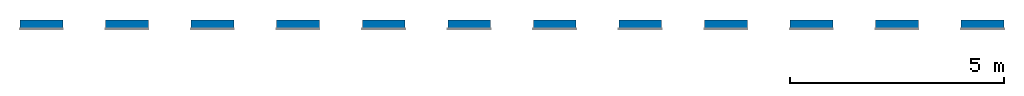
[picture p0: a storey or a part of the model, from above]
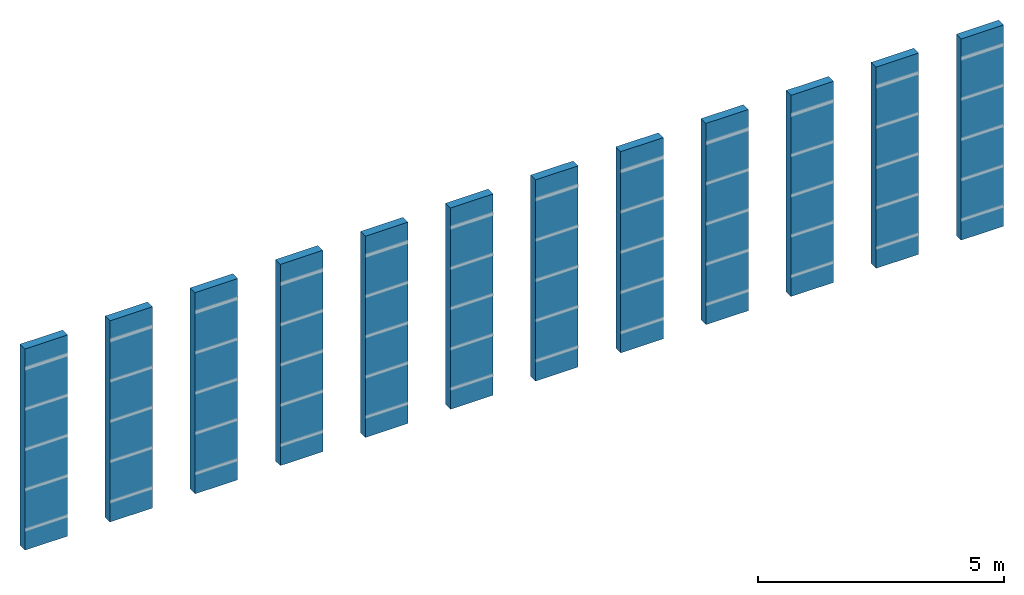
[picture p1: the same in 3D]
Properties of the parts of a building model (IFC2X3), part 1 of 4

# File
Description: ViewDefinition [CoordinationView_V2.0]
Time: 2025-06-20T14:48:50
Written by: The EXPRESS Data Manager Version 5.02.0100.07 : 28 Aug 2013
Made in: 21.1.90.15 - Exporter 21.1.90.15 - Alternate UI 21.1.90.15
Comment: STEP Physical File produced by: The EXPRESS Data Manager Version 5.02.0100.07 : 28 Aug 2013 * Module: EDMstepFileFactory/EDMstandAlone * Creation date: Fri Jun 20 14:48:50 2025 * Host: STB002 * Database: C:\Users\LARISS~1\AppData\Local\Temp\234e31d9-e186-458c-9206-d387dea7a233\7819710d-270b-444c-ba7b-598bd2ec56cc\ifc * Database version: 5507 * Database creation date: Fri Jun 20 14:48:48 2025 * Schema: IFC2X3 * Model: DataRepository.ifc * Model creation date: Fri Jun 20 14:48:49 2025 * Header model: DataRepository.ifc_HeaderModel * Header model creation date: Fri Jun 20 14:48:49 2025 * EDMuser: sdai-user * EDMgroup: sdai-group * License ID and type: 5605 : Permanent license. Expiry date: * EDMstepFileFactory options: 020000

# IfcSite, Default
RefLatitude: 42, 24, 53, 508911; RefLongitude: -71, -15, -29, -58837; RefElevation: 0 mm
Pset_ProductRequirements - Category: Project Information

# IfcBuilding
Pset_BuildingCommon - NumberOfStoreys: 1
Pset_ProductRequirements - Category: Project Information

# IfcBuildingStorey: Level:Level 1, Level 1
LongName: Level 1; Elevation: 0 mm
Pset_AirSideSystemInformation - Name: Level 1
Pset_ProductRequirements - Name: Level 1; Category: Levels

# IfcBuildingElementProxy: Wall Sweep:REVIGRÉS-OMNISTONE-RB-8X120-MATTRECT-BONE, Wall Sweep:REVIGRÉS-OMNISTONE-RB-8X120-MATTRECT-BONE:181677
In: Level 1
Type - Pset_ManufacturerTypeInformation - Manufacturer: REVIGRÉS
Type - Pset_ProductRequirements - Category: Wall Sweeps
Type - IFC.REVIGRÉS-Dados gerais-Wall Sweeps - Nome: REVIGRÉS-OMNISTONE-RB-8X120-MATT RECT-BONE; TipoProduto: Prensado a seco: grupo BIa UGL | Grés porcelânico técnico; NumeroDeRegistoDAP: EPD-REV-20240006-CCC1-EN; ReferenciaDAP: -; UrlDOP: -
Type - IFC.REVIGRÉS-Dados do fabricante-Wall Sweeps - FabricanteURL: https://www.revigres.pt/; ReferenciaModelo: Omnistone; Acabamento: MATT RECT; IdentificadorDoOperadorEconomico: 501840856; UrlFabricanteArtigo: https://www.revigres.pt/colecoes/omnistone; PaisOrigem: Portugal
Type - IFC.REVIGRÉS-Dados de desempenho-Wall Sweeps - Rectilinearidade: ± 0.2% máx.± 0.8 mm; Ortogonalidade: ± 0.2% máx.± 1.5 mm; PlanaridadeDaSuperficie: ± 0.3% máx. ± 1.8 mm; AbsorcaoDeAgua: < 0.05%; ModuloDeRuptura: > 45 N/mm130; ResistenciaAFlexao: ≥ 3500 N; ResistenciaAAbrasaoProfunda: < 120 mm131; DilatacaoTermicaLinear: ≤ 8,0x10-6 °C-1; ResistenciaAoChoqueTermico: Resiste; DurabilidadeResistenciaAoGeloDegelo: Resiste; ResistenciaAoEscorregamentoDIN51130: R10; ResistenciaAoEscorregamentoDIN51097: B; ResistenciaAoEscorregamentoENV51097: B; ResistenciaAoDeslizamentoENV12633: Class 2; ResistenciaAoEscorregamentoBS7976: >36; ResistenciaAoEscorregamentoANSIA1371: ≥0,42; ResistenciaAoEscorregamentoENV12633: Class 2; ResistenciaAoDeslizamentoBS7976: >36; ResistenciaAsManchas: Class 5; ResistenciaABaixasConcentracoesDeAcidosEAlcalis: Classe LA; ResistenciaAAltasConcentracoesDeAcidosEAlcalis: Classe HA; LibertacaoDeCadmio: 0; LibertacaoDeChumbo: 0
Type - IFC.REVIGRÉS-Dados de especificação-Wall Sweeps - VariacaoTonalidade: 3; NivelDeTrafego: 5; EPavimento: Não; ERevestimento: Sim; EExterno: Sim
Type - IFC.REVIGRÉS-Dados geométricos-Wall Sweeps - AlturaNominal: 9.8 mm; ComprimentoNominal: 8 mm; LarguraNominal: 118.6 mm
Type - IFC.REVIGRÉS-Dados de sustentabilidade-Wall Sweeps - ItemEParcialmenteReciclado: 0; PotencialPrivacaoDeAguaConsumoDeAguaPonderado: 4.5; EnergiaTermicaExportada: 0; ItemENovo: Sim; ItemEReciclado: Não; VidaÚtilEsperada: 50; SubstanciasPerigosas: Não; PotencialDeEsgotamentoAbioticoDosRecursosFosseis: 203; PotencialDeEsgotamentoAbioticoDosRecursosNaoFosseisMineraisEMetais: 0.000701; PotencialDeAquecimentoGlobalBiogenico: -0.48; CombustiveisFosseisComPotencialDeAquecimentoGlobal: 13.9; PotencialDeAquecimentoGlobalUsoDoSoloEMudancaDeUsoDoSolo: 0.0246; PotencialDeEutrofizacaoFraccaoDeNutrientesQueAtingemOCompartimentoFinalDeAguaDoce: 0.000189; PotencialDeEutrofizacaoFraccaoDeNutrientesQueAtingemOCompartimentoFinalMarinho: 0.0122; EnergiaRecuperada: 0.00739; ConsumoDeAguaDoce: 0.113; UtilizacaoLiquidaDeAguaDoce: 0.113; ResiduosPerigososEliminados: 0.00221; ResiduosNaoPerigososEliminados: 1.83; MassaTotalDeResiduosRadioactivosEliminados: 0.000394; EnergiaElectricaExportada: 1.55; MateriaisParaRecuperacaoDeEnergia: 0.00739; MateriaisParaReciclagem: 0.0253; UnidadeEPD: 1 m²
Pset_ProvisionForVoid - Shape: Undefined; Width: 1000 mm; Depth: 1000 mm
IFC.REVIGRÉS-Dados do fabricante-Wall Sweeps - Type: Wall Sweep: REVIGRÉS-OMNISTONE-RB-8X120-MATTRECT-BONE
IFC.REVIGRÉS-Dados de desempenho-Wall Sweeps - Type: Wall Sweep: REVIGRÉS-OMNISTONE-RB-8X120-MATTRECT-BONE
IFC.REVIGRÉS-Dados de especificação-Wall Sweeps - Type: Wall Sweep: REVIGRÉS-OMNISTONE-RB-8X120-MATTRECT-BONE
IFC.REVIGRÉS-Dados geométricos-Wall Sweeps - Type: Wall Sweep: REVIGRÉS-OMNISTONE-RB-8X120-MATTRECT-BONE
IFC.REVIGRÉS-Dados de sustentabilidade-Wall Sweeps - Type: Wall Sweep: REVIGRÉS-OMNISTONE-RB-8X120-MATTRECT-BONE

# IfcBuildingElementProxy: Wall Sweep:REVIGRÉS-OMNISTONE-RB-8X120-MATTRECT-ICE, Wall Sweep:REVIGRÉS-OMNISTONE-RB-8X120-MATTRECT-ICE:181689
In: Level 1
Type - Pset_ManufacturerTypeInformation - Manufacturer: REVIGRÉS
Type - Pset_ProductRequirements - Category: Wall Sweeps
Type - IFC.REVIGRÉS-Dados gerais-Wall Sweeps - Nome: REVIGRÉS-OMNISTONE-RB-8X120-MATT RECT-ICE; TipoProduto: Prensado a seco: grupo BIa UGL | Grés porcelânico técnico; NumeroDeRegistoDAP: EPD-REV-20240006-CCC1-EN; ReferenciaDAP: -; UrlDOP: -
Type - IFC.REVIGRÉS-Dados do fabricante-Wall Sweeps - FabricanteURL: https://www.revigres.pt/; ReferenciaModelo: Omnistone; Acabamento: MATT RECT; IdentificadorDoOperadorEconomico: 501840856; UrlFabricanteArtigo: https://www.revigres.pt/colecoes/omnistone; PaisOrigem: Portugal
Type - IFC.REVIGRÉS-Dados de desempenho-Wall Sweeps - Rectilinearidade: ± 0.2% máx.± 0.8 mm; Ortogonalidade: ± 0.2% máx.± 1.5 mm; PlanaridadeDaSuperficie: ± 0.3% máx. ± 1.8 mm; AbsorcaoDeAgua: < 0.05%; ModuloDeRuptura: > 45 N/mm130; ResistenciaAFlexao: ≥ 3500 N; ResistenciaAAbrasaoProfunda: < 120 mm131; DilatacaoTermicaLinear: ≤ 8,0x10-6 °C-1; ResistenciaAoChoqueTermico: Resiste; DurabilidadeResistenciaAoGeloDegelo: Resiste; ResistenciaAoEscorregamentoDIN51130: R10; ResistenciaAoEscorregamentoDIN51097: B; ResistenciaAoEscorregamentoENV51097: B; ResistenciaAoDeslizamentoENV12633: Class 2; ResistenciaAoEscorregamentoBS7976: >36; ResistenciaAoEscorregamentoANSIA1371: ≥0,42; ResistenciaAoEscorregamentoENV12633: Class 2; ResistenciaAoDeslizamentoBS7976: >36; ResistenciaAsManchas: Class 5; ResistenciaABaixasConcentracoesDeAcidosEAlcalis: Classe LA; ResistenciaAAltasConcentracoesDeAcidosEAlcalis: Classe HA; LibertacaoDeCadmio: 0; LibertacaoDeChumbo: 0
Type - IFC.REVIGRÉS-Dados de especificação-Wall Sweeps - VariacaoTonalidade: 3; NivelDeTrafego: 5; EPavimento: Não; ERevestimento: Sim; EExterno: Sim
Type - IFC.REVIGRÉS-Dados geométricos-Wall Sweeps - AlturaNominal: 9.8 mm; ComprimentoNominal: 8 mm; LarguraNominal: 118.6 mm
Type - IFC.REVIGRÉS-Dados de sustentabilidade-Wall Sweeps - ItemEParcialmenteReciclado: 0; PotencialPrivacaoDeAguaConsumoDeAguaPonderado: 4.5; EnergiaTermicaExportada: 0; ItemENovo: Sim; ItemEReciclado: Não; VidaÚtilEsperada: 50; SubstanciasPerigosas: Não; PotencialDeEsgotamentoAbioticoDosRecursosFosseis: 203; PotencialDeEsgotamentoAbioticoDosRecursosNaoFosseisMineraisEMetais: 0.000701; PotencialDeAquecimentoGlobalBiogenico: -0.48; CombustiveisFosseisComPotencialDeAquecimentoGlobal: 13.9; PotencialDeAquecimentoGlobalUsoDoSoloEMudancaDeUsoDoSolo: 0.0246; PotencialDeEutrofizacaoFraccaoDeNutrientesQueAtingemOCompartimentoFinalDeAguaDoce: 0.000189; PotencialDeEutrofizacaoFraccaoDeNutrientesQueAtingemOCompartimentoFinalMarinho: 0.0122; EnergiaRecuperada: 0.00739; ConsumoDeAguaDoce: 0.113; UtilizacaoLiquidaDeAguaDoce: 0.113; ResiduosPerigososEliminados: 0.00221; ResiduosNaoPerigososEliminados: 1.83; MassaTotalDeResiduosRadioactivosEliminados: 0.000394; EnergiaElectricaExportada: 1.55; MateriaisParaRecuperacaoDeEnergia: 0.00739; MateriaisParaReciclagem: 0.0253; UnidadeEPD: 1 m²
Pset_ProvisionForVoid - Shape: Undefined; Width: 1000 mm; Depth: 1000 mm
IFC.REVIGRÉS-Dados do fabricante-Wall Sweeps - Type: Wall Sweep: REVIGRÉS-OMNISTONE-RB-8X120-MATTRECT-ICE
IFC.REVIGRÉS-Dados de desempenho-Wall Sweeps - Type: Wall Sweep: REVIGRÉS-OMNISTONE-RB-8X120-MATTRECT-ICE
IFC.REVIGRÉS-Dados de especificação-Wall Sweeps - Type: Wall Sweep: REVIGRÉS-OMNISTONE-RB-8X120-MATTRECT-ICE
IFC.REVIGRÉS-Dados geométricos-Wall Sweeps - Type: Wall Sweep: REVIGRÉS-OMNISTONE-RB-8X120-MATTRECT-ICE
IFC.REVIGRÉS-Dados de sustentabilidade-Wall Sweeps - Type: Wall Sweep: REVIGRÉS-OMNISTONE-RB-8X120-MATTRECT-ICE

# IfcBuildingElementProxy: Wall Sweep:REVIGRÉS-OMNISTONE-RB-8X120-MATTRECT-IRON, Wall Sweep:REVIGRÉS-OMNISTONE-RB-8X120-MATTRECT-IRON:181701
In: Level 1
Type - Pset_ManufacturerTypeInformation - Manufacturer: REVIGRÉS
Type - Pset_ProductRequirements - Category: Wall Sweeps
Type - IFC.REVIGRÉS-Dados gerais-Wall Sweeps - Nome: REVIGRÉS-OMNISTONE-RB-8X120-MATT RECT-IRON; TipoProduto: Prensado a seco: grupo BIa UGL | Grés porcelânico técnico; NumeroDeRegistoDAP: EPD-REV-20240006-CCC1-EN; ReferenciaDAP: -; UrlDOP: -
Type - IFC.REVIGRÉS-Dados do fabricante-Wall Sweeps - FabricanteURL: https://www.revigres.pt/; ReferenciaModelo: Omnistone; Acabamento: MATT RECT; IdentificadorDoOperadorEconomico: 501840856; UrlFabricanteArtigo: https://www.revigres.pt/colecoes/omnistone; PaisOrigem: Portugal
Type - IFC.REVIGRÉS-Dados de desempenho-Wall Sweeps - Rectilinearidade: ± 0.2% máx.± 0.8 mm; Ortogonalidade: ± 0.2% máx.± 1.5 mm; PlanaridadeDaSuperficie: ± 0.3% máx. ± 1.8 mm; AbsorcaoDeAgua: < 0.05%; ModuloDeRuptura: > 45 N/mm130; ResistenciaAFlexao: ≥ 3500 N; ResistenciaAAbrasaoProfunda: < 120 mm131; DilatacaoTermicaLinear: ≤ 8,0x10-6 °C-1; ResistenciaAoChoqueTermico: Resiste; DurabilidadeResistenciaAoGeloDegelo: Resiste; ResistenciaAoEscorregamentoDIN51130: R10; ResistenciaAoEscorregamentoDIN51097: B; ResistenciaAoEscorregamentoENV51097: B; ResistenciaAoDeslizamentoENV12633: Class 2; ResistenciaAoEscorregamentoBS7976: >36; ResistenciaAoEscorregamentoANSIA1371: ≥0,42; ResistenciaAoEscorregamentoENV12633: Class 2; ResistenciaAoDeslizamentoBS7976: >36; ResistenciaAsManchas: Class 5; ResistenciaABaixasConcentracoesDeAcidosEAlcalis: Classe LA; ResistenciaAAltasConcentracoesDeAcidosEAlcalis: Classe HA; LibertacaoDeCadmio: 0; LibertacaoDeChumbo: 0
Type - IFC.REVIGRÉS-Dados de especificação-Wall Sweeps - VariacaoTonalidade: 3; NivelDeTrafego: 5; EPavimento: Não; ERevestimento: Sim; EExterno: Sim
Type - IFC.REVIGRÉS-Dados geométricos-Wall Sweeps - AlturaNominal: 9.8 mm; ComprimentoNominal: 8 mm; LarguraNominal: 118.6 mm
Type - IFC.REVIGRÉS-Dados de sustentabilidade-Wall Sweeps - PotencialPrivacaoDeAguaConsumoDeAguaPonderado: 4.5; EnergiaTermicaExportada: 0; ItemENovo: Sim; ItemEParcialmenteReciclado: 0.14; ItemEReciclado: Sim; VidaÚtilEsperada: 50; SubstanciasPerigosas: Não; PotencialDeEsgotamentoAbioticoDosRecursosFosseis: 203; PotencialDeEsgotamentoAbioticoDosRecursosNaoFosseisMineraisEMetais: 0.000701; PotencialDeAquecimentoGlobalBiogenico: -0.48; CombustiveisFosseisComPotencialDeAquecimentoGlobal: 13.9; PotencialDeAquecimentoGlobalUsoDoSoloEMudancaDeUsoDoSolo: 0.0246; PotencialDeEutrofizacaoFraccaoDeNutrientesQueAtingemOCompartimentoFinalDeAguaDoce: 0.000189; PotencialDeEutrofizacaoFraccaoDeNutrientesQueAtingemOCompartimentoFinalMarinho: 0.0122; EnergiaRecuperada: 0.00739; ConsumoDeAguaDoce: 0.113; UtilizacaoLiquidaDeAguaDoce: 0.113; ResiduosPerigososEliminados: 0.00221; ResiduosNaoPerigososEliminados: 1.83; MassaTotalDeResiduosRadioactivosEliminados: 0.000394; EnergiaElectricaExportada: 1.55; MateriaisParaRecuperacaoDeEnergia: 0.00739; MateriaisParaReciclagem: 0.0253; UnidadeEPD: 1 m²
Pset_ProvisionForVoid - Shape: Undefined; Width: 1000 mm; Depth: 1000 mm
IFC.REVIGRÉS-Dados do fabricante-Wall Sweeps - Type: Wall Sweep: REVIGRÉS-OMNISTONE-RB-8X120-MATTRECT-IRON
IFC.REVIGRÉS-Dados de desempenho-Wall Sweeps - Type: Wall Sweep: REVIGRÉS-OMNISTONE-RB-8X120-MATTRECT-IRON
IFC.REVIGRÉS-Dados de especificação-Wall Sweeps - Type: Wall Sweep: REVIGRÉS-OMNISTONE-RB-8X120-MATTRECT-IRON
IFC.REVIGRÉS-Dados geométricos-Wall Sweeps - Type: Wall Sweep: REVIGRÉS-OMNISTONE-RB-8X120-MATTRECT-IRON
IFC.REVIGRÉS-Dados de sustentabilidade-Wall Sweeps - Type: Wall Sweep: REVIGRÉS-OMNISTONE-RB-8X120-MATTRECT-IRON

# IfcBuildingElementProxy: Wall Sweep:REVIGRÉS-OMNISTONE-RB-8X120-MATTRECT-JET, Wall Sweep:REVIGRÉS-OMNISTONE-RB-8X120-MATTRECT-JET:181713
In: Level 1
Type - Pset_ManufacturerTypeInformation - Manufacturer: REVIGRÉS
Type - Pset_ProductRequirements - Category: Wall Sweeps
Type - IFC.REVIGRÉS-Dados gerais-Wall Sweeps - Nome: REVIGRÉS-OMNISTONE-RB-8X120-MATT RECT-JET; TipoProduto: Prensado a seco: grupo BIa UGL | Grés porcelânico técnico; NumeroDeRegistoDAP: EPD-REV-20240006-CCC1-EN; ReferenciaDAP: -; UrlDOP: -
Type - IFC.REVIGRÉS-Dados do fabricante-Wall Sweeps - FabricanteURL: https://www.revigres.pt/; ReferenciaModelo: Omnistone; Acabamento: MATT RECT; IdentificadorDoOperadorEconomico: 501840856; UrlFabricanteArtigo: https://www.revigres.pt/colecoes/omnistone; PaisOrigem: Portugal
Type - IFC.REVIGRÉS-Dados de desempenho-Wall Sweeps - Rectilinearidade: ± 0.2% máx.± 0.8 mm; Ortogonalidade: ± 0.2% máx.± 1.5 mm; PlanaridadeDaSuperficie: ± 0.3% máx. ± 1.8 mm; AbsorcaoDeAgua: < 0.05%; ModuloDeRuptura: > 45 N/mm130; ResistenciaAFlexao: ≥ 3500 N; ResistenciaAAbrasaoProfunda: < 120 mm131; DilatacaoTermicaLinear: ≤ 8,0x10-6 °C-1; ResistenciaAoChoqueTermico: Resiste; DurabilidadeResistenciaAoGeloDegelo: Resiste; ResistenciaAoEscorregamentoDIN51130: R10; ResistenciaAoEscorregamentoDIN51097: B; ResistenciaAoEscorregamentoENV51097: B; ResistenciaAoDeslizamentoENV12633: Class 2; ResistenciaAoEscorregamentoBS7976: >36; ResistenciaAoEscorregamentoANSIA1371: ≥0,42; ResistenciaAoEscorregamentoENV12633: Class 2; ResistenciaAoDeslizamentoBS7976: >36; ResistenciaAsManchas: Class 5; ResistenciaABaixasConcentracoesDeAcidosEAlcalis: Classe LA; ResistenciaAAltasConcentracoesDeAcidosEAlcalis: Classe HA; LibertacaoDeCadmio: 0; LibertacaoDeChumbo: 0
Type - IFC.REVIGRÉS-Dados de especificação-Wall Sweeps - VariacaoTonalidade: 3; NivelDeTrafego: 5; EPavimento: Não; ERevestimento: Sim; EExterno: Sim
Type - IFC.REVIGRÉS-Dados geométricos-Wall Sweeps - AlturaNominal: 9.8 mm; ComprimentoNominal: 8 mm; LarguraNominal: 118.6 mm
Type - IFC.REVIGRÉS-Dados de sustentabilidade-Wall Sweeps - ItemEParcialmenteReciclado: 0; PotencialPrivacaoDeAguaConsumoDeAguaPonderado: 4.5; EnergiaTermicaExportada: 0; ItemENovo: Sim; ItemEReciclado: Não; VidaÚtilEsperada: 50; SubstanciasPerigosas: Não; PotencialDeEsgotamentoAbioticoDosRecursosFosseis: 203; PotencialDeEsgotamentoAbioticoDosRecursosNaoFosseisMineraisEMetais: 0.000701; PotencialDeAquecimentoGlobalBiogenico: -0.48; CombustiveisFosseisComPotencialDeAquecimentoGlobal: 13.9; PotencialDeAquecimentoGlobalUsoDoSoloEMudancaDeUsoDoSolo: 0.0246; PotencialDeEutrofizacaoFraccaoDeNutrientesQueAtingemOCompartimentoFinalDeAguaDoce: 0.000189; PotencialDeEutrofizacaoFraccaoDeNutrientesQueAtingemOCompartimentoFinalMarinho: 0.0122; EnergiaRecuperada: 0.00739; ConsumoDeAguaDoce: 0.113; UtilizacaoLiquidaDeAguaDoce: 0.113; ResiduosPerigososEliminados: 0.00221; ResiduosNaoPerigososEliminados: 1.83; MassaTotalDeResiduosRadioactivosEliminados: 0.000394; EnergiaElectricaExportada: 1.55; MateriaisParaRecuperacaoDeEnergia: 0.00739; MateriaisParaReciclagem: 0.0253; UnidadeEPD: 1 m²
Pset_ProvisionForVoid - Shape: Undefined; Width: 1000 mm; Depth: 1000 mm
IFC.REVIGRÉS-Dados do fabricante-Wall Sweeps - Type: Wall Sweep: REVIGRÉS-OMNISTONE-RB-8X120-MATTRECT-JET
IFC.REVIGRÉS-Dados de desempenho-Wall Sweeps - Type: Wall Sweep: REVIGRÉS-OMNISTONE-RB-8X120-MATTRECT-JET
IFC.REVIGRÉS-Dados de especificação-Wall Sweeps - Type: Wall Sweep: REVIGRÉS-OMNISTONE-RB-8X120-MATTRECT-JET
IFC.REVIGRÉS-Dados geométricos-Wall Sweeps - Type: Wall Sweep: REVIGRÉS-OMNISTONE-RB-8X120-MATTRECT-JET
IFC.REVIGRÉS-Dados de sustentabilidade-Wall Sweeps - Type: Wall Sweep: REVIGRÉS-OMNISTONE-RB-8X120-MATTRECT-JET

# IfcBuildingElementProxy: Wall Sweep:REVIGRÉS-OMNISTONE-RB-8X120-MATTRECT-PLATINA, Wall Sweep:REVIGRÉS-OMNISTONE-RB-8X120-MATTRECT-PLATINA:181725
In: Level 1
Type - Pset_ManufacturerTypeInformation - Manufacturer: REVIGRÉS
Type - Pset_ProductRequirements - Category: Wall Sweeps
Type - IFC.REVIGRÉS-Dados gerais-Wall Sweeps - Nome: REVIGRÉS-OMNISTONE-RB-8X120-MATT RECT-PLATINA; TipoProduto: Prensado a seco: grupo BIa UGL | Grés porcelânico técnico; NumeroDeRegistoDAP: EPD-REV-20240006-CCC1-EN; ReferenciaDAP: -; UrlDOP: -
Type - IFC.REVIGRÉS-Dados do fabricante-Wall Sweeps - FabricanteURL: https://www.revigres.pt/; ReferenciaModelo: Omnistone; Acabamento: MATT RECT; IdentificadorDoOperadorEconomico: 501840856; UrlFabricanteArtigo: https://www.revigres.pt/colecoes/omnistone; PaisOrigem: Portugal
Type - IFC.REVIGRÉS-Dados de desempenho-Wall Sweeps - Rectilinearidade: ± 0.2% máx.± 0.8 mm; Ortogonalidade: ± 0.2% máx.± 1.5 mm; PlanaridadeDaSuperficie: ± 0.3% máx. ± 1.8 mm; AbsorcaoDeAgua: < 0.05%; ModuloDeRuptura: > 45 N/mm130; ResistenciaAFlexao: ≥ 3500 N; ResistenciaAAbrasaoProfunda: < 120 mm131; DilatacaoTermicaLinear: ≤ 8,0x10-6 °C-1; ResistenciaAoChoqueTermico: Resiste; DurabilidadeResistenciaAoGeloDegelo: Resiste; ResistenciaAoEscorregamentoDIN51130: R10; ResistenciaAoEscorregamentoDIN51097: B; ResistenciaAoEscorregamentoENV51097: B; ResistenciaAoDeslizamentoENV12633: Class 2; ResistenciaAoEscorregamentoBS7976: >36; ResistenciaAoEscorregamentoANSIA1371: ≥0,42; ResistenciaAoEscorregamentoENV12633: Class 2; ResistenciaAoDeslizamentoBS7976: >36; ResistenciaAsManchas: Class 5; ResistenciaABaixasConcentracoesDeAcidosEAlcalis: Classe LA; ResistenciaAAltasConcentracoesDeAcidosEAlcalis: Classe HA; LibertacaoDeCadmio: 0; LibertacaoDeChumbo: 0
Type - IFC.REVIGRÉS-Dados de especificação-Wall Sweeps - VariacaoTonalidade: 3; NivelDeTrafego: 5; EPavimento: Não; ERevestimento: Sim; EExterno: Sim
Type - IFC.REVIGRÉS-Dados geométricos-Wall Sweeps - AlturaNominal: 9.8 mm; ComprimentoNominal: 8 mm; LarguraNominal: 118.6 mm
Type - IFC.REVIGRÉS-Dados de sustentabilidade-Wall Sweeps - ItemEParcialmenteReciclado: 0; PotencialPrivacaoDeAguaConsumoDeAguaPonderado: 4.5; EnergiaTermicaExportada: 0; ItemENovo: Sim; ItemEReciclado: Não; VidaÚtilEsperada: 50; SubstanciasPerigosas: Não; PotencialDeEsgotamentoAbioticoDosRecursosFosseis: 203; PotencialDeEsgotamentoAbioticoDosRecursosNaoFosseisMineraisEMetais: 0.000701; PotencialDeAquecimentoGlobalBiogenico: -0.48; CombustiveisFosseisComPotencialDeAquecimentoGlobal: 13.9; PotencialDeAquecimentoGlobalUsoDoSoloEMudancaDeUsoDoSolo: 0.0246; PotencialDeEutrofizacaoFraccaoDeNutrientesQueAtingemOCompartimentoFinalDeAguaDoce: 0.000189; PotencialDeEutrofizacaoFraccaoDeNutrientesQueAtingemOCompartimentoFinalMarinho: 0.0122; EnergiaRecuperada: 0.00739; ConsumoDeAguaDoce: 0.113; UtilizacaoLiquidaDeAguaDoce: 0.113; ResiduosPerigososEliminados: 0.00221; ResiduosNaoPerigososEliminados: 1.83; MassaTotalDeResiduosRadioactivosEliminados: 0.000394; EnergiaElectricaExportada: 1.55; MateriaisParaRecuperacaoDeEnergia: 0.00739; MateriaisParaReciclagem: 0.0253; UnidadeEPD: 1 m²
Pset_ProvisionForVoid - Shape: Undefined; Width: 1000 mm; Depth: 1000 mm
IFC.REVIGRÉS-Dados do fabricante-Wall Sweeps - Type: Wall Sweep: REVIGRÉS-OMNISTONE-RB-8X120-MATTRECT-PLATINA
IFC.REVIGRÉS-Dados de desempenho-Wall Sweeps - Type: Wall Sweep: REVIGRÉS-OMNISTONE-RB-8X120-MATTRECT-PLATINA
IFC.REVIGRÉS-Dados de especificação-Wall Sweeps - Type: Wall Sweep: REVIGRÉS-OMNISTONE-RB-8X120-MATTRECT-PLATINA
IFC.REVIGRÉS-Dados geométricos-Wall Sweeps - Type: Wall Sweep: REVIGRÉS-OMNISTONE-RB-8X120-MATTRECT-PLATINA
IFC.REVIGRÉS-Dados de sustentabilidade-Wall Sweeps - Type: Wall Sweep: REVIGRÉS-OMNISTONE-RB-8X120-MATTRECT-PLATINA

# IfcBuildingElementProxy: Wall Sweep:REVIGRÉS-OMNISTONE-RB-8X120-MATTRECT-ROPE, Wall Sweep:REVIGRÉS-OMNISTONE-RB-8X120-MATTRECT-ROPE:181737
In: Level 1
Type - Pset_ManufacturerTypeInformation - Manufacturer: REVIGRÉS
Type - Pset_ProductRequirements - Category: Wall Sweeps
Type - IFC.REVIGRÉS-Dados gerais-Wall Sweeps - Nome: REVIGRÉS-OMNISTONE-RB-8X120-MATT RECT-ROPE; TipoProduto: Prensado a seco: grupo BIa UGL | Grés porcelânico técnico; NumeroDeRegistoDAP: EPD-REV-20240006-CCC1-EN; ReferenciaDAP: -; UrlDOP: -
Type - IFC.REVIGRÉS-Dados do fabricante-Wall Sweeps - FabricanteURL: https://www.revigres.pt/; ReferenciaModelo: Omnistone; Acabamento: MATT RECT; IdentificadorDoOperadorEconomico: 501840856; UrlFabricanteArtigo: https://www.revigres.pt/colecoes/omnistone; PaisOrigem: Portugal
Type - IFC.REVIGRÉS-Dados de desempenho-Wall Sweeps - Rectilinearidade: ± 0.2% máx.± 0.8 mm; Ortogonalidade: ± 0.2% máx.± 1.5 mm; PlanaridadeDaSuperficie: ± 0.3% máx. ± 1.8 mm; AbsorcaoDeAgua: < 0.05%; ModuloDeRuptura: > 45 N/mm130; ResistenciaAFlexao: ≥ 3500 N; ResistenciaAAbrasaoProfunda: < 120 mm131; DilatacaoTermicaLinear: ≤ 8,0x10-6 °C-1; ResistenciaAoChoqueTermico: Resiste; DurabilidadeResistenciaAoGeloDegelo: Resiste; ResistenciaAoEscorregamentoDIN51130: R10; ResistenciaAoEscorregamentoDIN51097: B; ResistenciaAoEscorregamentoENV51097: B; ResistenciaAoDeslizamentoENV12633: Class 2; ResistenciaAoEscorregamentoBS7976: >36; ResistenciaAoEscorregamentoANSIA1371: ≥0,42; ResistenciaAoEscorregamentoENV12633: Class 2; ResistenciaAoDeslizamentoBS7976: >36; ResistenciaAsManchas: Class 5; ResistenciaABaixasConcentracoesDeAcidosEAlcalis: Classe LA; ResistenciaAAltasConcentracoesDeAcidosEAlcalis: Classe HA; LibertacaoDeCadmio: 0; LibertacaoDeChumbo: 0
Type - IFC.REVIGRÉS-Dados de especificação-Wall Sweeps - VariacaoTonalidade: 3; NivelDeTrafego: 5; EPavimento: Não; ERevestimento: Sim; EExterno: Sim
Type - IFC.REVIGRÉS-Dados geométricos-Wall Sweeps - AlturaNominal: 9.8 mm; ComprimentoNominal: 8 mm; LarguraNominal: 118.6 mm
Type - IFC.REVIGRÉS-Dados de sustentabilidade-Wall Sweeps - ItemEParcialmenteReciclado: 0; PotencialPrivacaoDeAguaConsumoDeAguaPonderado: 4.5; EnergiaTermicaExportada: 0; ItemENovo: Sim; ItemEReciclado: Não; VidaÚtilEsperada: 50; SubstanciasPerigosas: Não; PotencialDeEsgotamentoAbioticoDosRecursosFosseis: 203; PotencialDeEsgotamentoAbioticoDosRecursosNaoFosseisMineraisEMetais: 0.000701; PotencialDeAquecimentoGlobalBiogenico: -0.48; CombustiveisFosseisComPotencialDeAquecimentoGlobal: 13.9; PotencialDeAquecimentoGlobalUsoDoSoloEMudancaDeUsoDoSolo: 0.0246; PotencialDeEutrofizacaoFraccaoDeNutrientesQueAtingemOCompartimentoFinalDeAguaDoce: 0.000189; PotencialDeEutrofizacaoFraccaoDeNutrientesQueAtingemOCompartimentoFinalMarinho: 0.0122; EnergiaRecuperada: 0.00739; ConsumoDeAguaDoce: 0.113; UtilizacaoLiquidaDeAguaDoce: 0.113; ResiduosPerigososEliminados: 0.00221; ResiduosNaoPerigososEliminados: 1.83; MassaTotalDeResiduosRadioactivosEliminados: 0.000394; EnergiaElectricaExportada: 1.55; MateriaisParaRecuperacaoDeEnergia: 0.00739; MateriaisParaReciclagem: 0.0253; UnidadeEPD: 1 m²
Pset_ProvisionForVoid - Shape: Undefined; Width: 1000 mm; Depth: 1000 mm
IFC.REVIGRÉS-Dados do fabricante-Wall Sweeps - Type: Wall Sweep: REVIGRÉS-OMNISTONE-RB-8X120-MATTRECT-ROPE
IFC.REVIGRÉS-Dados de desempenho-Wall Sweeps - Type: Wall Sweep: REVIGRÉS-OMNISTONE-RB-8X120-MATTRECT-ROPE
IFC.REVIGRÉS-Dados de especificação-Wall Sweeps - Type: Wall Sweep: REVIGRÉS-OMNISTONE-RB-8X120-MATTRECT-ROPE
IFC.REVIGRÉS-Dados geométricos-Wall Sweeps - Type: Wall Sweep: REVIGRÉS-OMNISTONE-RB-8X120-MATTRECT-ROPE
IFC.REVIGRÉS-Dados de sustentabilidade-Wall Sweeps - Type: Wall Sweep: REVIGRÉS-OMNISTONE-RB-8X120-MATTRECT-ROPE

# IfcBuildingElementProxy: Wall Sweep:REVIGRÉS-OMNISTONE-RB-8X120-SOFT-BONE, Wall Sweep:REVIGRÉS-OMNISTONE-RB-8X120-SOFT-BONE:181683
In: Level 1
Type - Pset_ManufacturerTypeInformation - Manufacturer: REVIGRÉS
Type - Pset_ProductRequirements - Category: Wall Sweeps
Type - IFC.REVIGRÉS-Dados gerais-Wall Sweeps - Nome: REVIGRÉS-OMNISTONE-RB-8X120-SOFT-BONE; TipoProduto: Prensado a seco: grupo BIa UGL | Grés porcelânico técnico; NumeroDeRegistoDAP: EPD-REV-20240006-CCC1-EN; ReferenciaDAP: -; UrlDOP: -
Type - IFC.REVIGRÉS-Dados do fabricante-Wall Sweeps - FabricanteURL: https://www.revigres.pt/; ReferenciaModelo: Omnistone; Acabamento: SOFT; IdentificadorDoOperadorEconomico: 501840856; UrlFabricanteArtigo: https://www.revigres.pt/colecoes/omnistone; PaisOrigem: Portugal
Type - IFC.REVIGRÉS-Dados de desempenho-Wall Sweeps - Rectilinearidade: ± 0.2% máx.± 0.8 mm; Ortogonalidade: ± 0.2% máx.± 1.5 mm; PlanaridadeDaSuperficie: ± 0.3% máx. ± 1.8 mm; AbsorcaoDeAgua: < 0.05%; ModuloDeRuptura: > 45 N/mm130; ResistenciaAFlexao: ≥ 3500 N; ResistenciaAAbrasaoProfunda: < 120 mm131; DilatacaoTermicaLinear: ≤ 8,0x10-6 °C-1; ResistenciaAoChoqueTermico: Resiste; DurabilidadeResistenciaAoGeloDegelo: Resiste; ResistenciaAsManchas: Class 5; ResistenciaABaixasConcentracoesDeAcidosEAlcalis: Classe LA; ResistenciaAAltasConcentracoesDeAcidosEAlcalis: Classe HA; LibertacaoDeCadmio: 0; LibertacaoDeChumbo: 0
Type - IFC.REVIGRÉS-Dados de especificação-Wall Sweeps - VariacaoTonalidade: 3; NivelDeTrafego: 5; EPavimento: Não; ERevestimento: Sim; EExterno: Sim
Type - IFC.REVIGRÉS-Dados geométricos-Wall Sweeps - AlturaNominal: 9.8 mm; ComprimentoNominal: 8 mm; LarguraNominal: 118.6 mm
Type - IFC.REVIGRÉS-Dados de sustentabilidade-Wall Sweeps - ItemEParcialmenteReciclado: 0; PotencialPrivacaoDeAguaConsumoDeAguaPonderado: 4.5; EnergiaTermicaExportada: 0; ItemENovo: Sim; ItemEReciclado: Não; VidaÚtilEsperada: 50; SubstanciasPerigosas: Não; PotencialDeEsgotamentoAbioticoDosRecursosFosseis: 203; PotencialDeEsgotamentoAbioticoDosRecursosNaoFosseisMineraisEMetais: 0.000701; PotencialDeAquecimentoGlobalBiogenico: -0.48; CombustiveisFosseisComPotencialDeAquecimentoGlobal: 13.9; PotencialDeAquecimentoGlobalUsoDoSoloEMudancaDeUsoDoSolo: 0.0246; PotencialDeEutrofizacaoFraccaoDeNutrientesQueAtingemOCompartimentoFinalDeAguaDoce: 0.000189; PotencialDeEutrofizacaoFraccaoDeNutrientesQueAtingemOCompartimentoFinalMarinho: 0.0122; EnergiaRecuperada: 0.00739; ConsumoDeAguaDoce: 0.113; UtilizacaoLiquidaDeAguaDoce: 0.113; ResiduosPerigososEliminados: 0.00221; ResiduosNaoPerigososEliminados: 1.83; MassaTotalDeResiduosRadioactivosEliminados: 0.000394; EnergiaElectricaExportada: 1.55; MateriaisParaRecuperacaoDeEnergia: 0.00739; MateriaisParaReciclagem: 0.0253; UnidadeEPD: 1 m²
Pset_ProvisionForVoid - Shape: Undefined; Width: 1000 mm; Depth: 1000 mm
IFC.REVIGRÉS-Dados do fabricante-Wall Sweeps - Type: Wall Sweep: REVIGRÉS-OMNISTONE-RB-8X120-SOFT-BONE
IFC.REVIGRÉS-Dados de desempenho-Wall Sweeps - Type: Wall Sweep: REVIGRÉS-OMNISTONE-RB-8X120-SOFT-BONE
IFC.REVIGRÉS-Dados de especificação-Wall Sweeps - Type: Wall Sweep: REVIGRÉS-OMNISTONE-RB-8X120-SOFT-BONE
IFC.REVIGRÉS-Dados geométricos-Wall Sweeps - Type: Wall Sweep: REVIGRÉS-OMNISTONE-RB-8X120-SOFT-BONE
IFC.REVIGRÉS-Dados de sustentabilidade-Wall Sweeps - Type: Wall Sweep: REVIGRÉS-OMNISTONE-RB-8X120-SOFT-BONE

# IfcBuildingElementProxy: Wall Sweep:REVIGRÉS-OMNISTONE-RB-8X120-SOFT-ICE, Wall Sweep:REVIGRÉS-OMNISTONE-RB-8X120-SOFT-ICE:181695
In: Level 1
Type - Pset_ManufacturerTypeInformation - Manufacturer: REVIGRÉS
Type - Pset_ProductRequirements - Category: Wall Sweeps
Type - IFC.REVIGRÉS-Dados gerais-Wall Sweeps - Nome: REVIGRÉS-OMNISTONE-RB-8X120-SOFT-ICE; TipoProduto: Prensado a seco: grupo BIa UGL | Grés porcelânico técnico; NumeroDeRegistoDAP: EPD-REV-20240006-CCC1-EN; ReferenciaDAP: -; UrlDOP: -
Type - IFC.REVIGRÉS-Dados do fabricante-Wall Sweeps - FabricanteURL: https://www.revigres.pt/; ReferenciaModelo: Omnistone; Acabamento: SOFT; IdentificadorDoOperadorEconomico: 501840856; UrlFabricanteArtigo: https://www.revigres.pt/colecoes/omnistone; PaisOrigem: Portugal
Type - IFC.REVIGRÉS-Dados de desempenho-Wall Sweeps - Rectilinearidade: ± 0.2% máx.± 0.8 mm; Ortogonalidade: ± 0.2% máx.± 1.5 mm; PlanaridadeDaSuperficie: ± 0.3% máx. ± 1.8 mm; AbsorcaoDeAgua: < 0.05%; ModuloDeRuptura: > 45 N/mm130; ResistenciaAFlexao: ≥ 3500 N; ResistenciaAAbrasaoProfunda: < 120 mm131; DilatacaoTermicaLinear: ≤ 8,0x10-6 °C-1; ResistenciaAoChoqueTermico: Resiste; DurabilidadeResistenciaAoGeloDegelo: Resiste; ResistenciaAsManchas: Class 5; ResistenciaABaixasConcentracoesDeAcidosEAlcalis: Classe LA; ResistenciaAAltasConcentracoesDeAcidosEAlcalis: Classe HA; LibertacaoDeCadmio: 0; LibertacaoDeChumbo: 0
Type - IFC.REVIGRÉS-Dados de especificação-Wall Sweeps - VariacaoTonalidade: 3; NivelDeTrafego: 5; EPavimento: Não; ERevestimento: Sim; EExterno: Sim
Type - IFC.REVIGRÉS-Dados geométricos-Wall Sweeps - AlturaNominal: 9.8 mm; ComprimentoNominal: 8 mm; LarguraNominal: 118.6 mm
Type - IFC.REVIGRÉS-Dados de sustentabilidade-Wall Sweeps - ItemEParcialmenteReciclado: 0; PotencialPrivacaoDeAguaConsumoDeAguaPonderado: 4.5; EnergiaTermicaExportada: 0; ItemENovo: Sim; ItemEReciclado: Não; VidaÚtilEsperada: 50; SubstanciasPerigosas: Não; PotencialDeEsgotamentoAbioticoDosRecursosFosseis: 203; PotencialDeEsgotamentoAbioticoDosRecursosNaoFosseisMineraisEMetais: 0.000701; PotencialDeAquecimentoGlobalBiogenico: -0.48; CombustiveisFosseisComPotencialDeAquecimentoGlobal: 13.9; PotencialDeAquecimentoGlobalUsoDoSoloEMudancaDeUsoDoSolo: 0.0246; PotencialDeEutrofizacaoFraccaoDeNutrientesQueAtingemOCompartimentoFinalDeAguaDoce: 0.000189; PotencialDeEutrofizacaoFraccaoDeNutrientesQueAtingemOCompartimentoFinalMarinho: 0.0122; EnergiaRecuperada: 0.00739; ConsumoDeAguaDoce: 0.113; UtilizacaoLiquidaDeAguaDoce: 0.113; ResiduosPerigososEliminados: 0.00221; ResiduosNaoPerigososEliminados: 1.83; MassaTotalDeResiduosRadioactivosEliminados: 0.000394; EnergiaElectricaExportada: 1.55; MateriaisParaRecuperacaoDeEnergia: 0.00739; MateriaisParaReciclagem: 0.0253; UnidadeEPD: 1 m²
Pset_ProvisionForVoid - Shape: Undefined; Width: 1000 mm; Depth: 1000 mm
IFC.REVIGRÉS-Dados do fabricante-Wall Sweeps - Type: Wall Sweep: REVIGRÉS-OMNISTONE-RB-8X120-SOFT-ICE
IFC.REVIGRÉS-Dados de desempenho-Wall Sweeps - Type: Wall Sweep: REVIGRÉS-OMNISTONE-RB-8X120-SOFT-ICE
IFC.REVIGRÉS-Dados de especificação-Wall Sweeps - Type: Wall Sweep: REVIGRÉS-OMNISTONE-RB-8X120-SOFT-ICE
IFC.REVIGRÉS-Dados geométricos-Wall Sweeps - Type: Wall Sweep: REVIGRÉS-OMNISTONE-RB-8X120-SOFT-ICE
IFC.REVIGRÉS-Dados de sustentabilidade-Wall Sweeps - Type: Wall Sweep: REVIGRÉS-OMNISTONE-RB-8X120-SOFT-ICE

# IfcBuildingElementProxy: Wall Sweep:REVIGRÉS-OMNISTONE-RB-8X120-SOFT-IRON, Wall Sweep:REVIGRÉS-OMNISTONE-RB-8X120-SOFT-IRON:181707
In: Level 1
Type - Pset_ManufacturerTypeInformation - Manufacturer: REVIGRÉS
Type - Pset_ProductRequirements - Category: Wall Sweeps
Type - IFC.REVIGRÉS-Dados gerais-Wall Sweeps - Nome: REVIGRÉS-OMNISTONE-RB-8X120-SOFT-IRON; TipoProduto: Prensado a seco: grupo BIa UGL | Grés porcelânico técnico; NumeroDeRegistoDAP: EPD-REV-20240006-CCC1-EN; ReferenciaDAP: -; UrlDOP: -
Type - IFC.REVIGRÉS-Dados do fabricante-Wall Sweeps - FabricanteURL: https://www.revigres.pt/; ReferenciaModelo: Omnistone; Acabamento: SOFT; IdentificadorDoOperadorEconomico: 501840856; UrlFabricanteArtigo: https://www.revigres.pt/colecoes/omnistone; PaisOrigem: Portugal
Type - IFC.REVIGRÉS-Dados de desempenho-Wall Sweeps - Rectilinearidade: ± 0.2% máx.± 0.8 mm; Ortogonalidade: ± 0.2% máx.± 1.5 mm; PlanaridadeDaSuperficie: ± 0.3% máx. ± 1.8 mm; AbsorcaoDeAgua: < 0.05%; ModuloDeRuptura: > 45 N/mm130; ResistenciaAFlexao: ≥ 3500 N; ResistenciaAAbrasaoProfunda: < 120 mm131; DilatacaoTermicaLinear: ≤ 8,0x10-6 °C-1; ResistenciaAoChoqueTermico: Resiste; DurabilidadeResistenciaAoGeloDegelo: Resiste; ResistenciaAsManchas: Class 5; ResistenciaABaixasConcentracoesDeAcidosEAlcalis: Classe LA; ResistenciaAAltasConcentracoesDeAcidosEAlcalis: Classe HA; LibertacaoDeCadmio: 0; LibertacaoDeChumbo: 0
Type - IFC.REVIGRÉS-Dados de especificação-Wall Sweeps - VariacaoTonalidade: 3; NivelDeTrafego: 5; EPavimento: Não; ERevestimento: Sim; EExterno: Sim
Type - IFC.REVIGRÉS-Dados geométricos-Wall Sweeps - AlturaNominal: 9.8 mm; ComprimentoNominal: 8 mm; LarguraNominal: 118.6 mm
Type - IFC.REVIGRÉS-Dados de sustentabilidade-Wall Sweeps - PotencialPrivacaoDeAguaConsumoDeAguaPonderado: 4.5; EnergiaTermicaExportada: 0; ItemENovo: Sim; ItemEParcialmenteReciclado: 0.14; ItemEReciclado: Sim; VidaÚtilEsperada: 50; SubstanciasPerigosas: Não; PotencialDeEsgotamentoAbioticoDosRecursosFosseis: 203; PotencialDeEsgotamentoAbioticoDosRecursosNaoFosseisMineraisEMetais: 0.000701; PotencialDeAquecimentoGlobalBiogenico: -0.48; CombustiveisFosseisComPotencialDeAquecimentoGlobal: 13.9; PotencialDeAquecimentoGlobalUsoDoSoloEMudancaDeUsoDoSolo: 0.0246; PotencialDeEutrofizacaoFraccaoDeNutrientesQueAtingemOCompartimentoFinalDeAguaDoce: 0.000189; PotencialDeEutrofizacaoFraccaoDeNutrientesQueAtingemOCompartimentoFinalMarinho: 0.0122; EnergiaRecuperada: 0.00739; ConsumoDeAguaDoce: 0.113; UtilizacaoLiquidaDeAguaDoce: 0.113; ResiduosPerigososEliminados: 0.00221; ResiduosNaoPerigososEliminados: 1.83; MassaTotalDeResiduosRadioactivosEliminados: 0.000394; EnergiaElectricaExportada: 1.55; MateriaisParaRecuperacaoDeEnergia: 0.00739; MateriaisParaReciclagem: 0.0253; UnidadeEPD: 1 m²
Pset_ProvisionForVoid - Shape: Undefined; Width: 1000 mm; Depth: 1000 mm
IFC.REVIGRÉS-Dados do fabricante-Wall Sweeps - Type: Wall Sweep: REVIGRÉS-OMNISTONE-RB-8X120-SOFT-IRON
IFC.REVIGRÉS-Dados de desempenho-Wall Sweeps - Type: Wall Sweep: REVIGRÉS-OMNISTONE-RB-8X120-SOFT-IRON
IFC.REVIGRÉS-Dados de especificação-Wall Sweeps - Type: Wall Sweep: REVIGRÉS-OMNISTONE-RB-8X120-SOFT-IRON
IFC.REVIGRÉS-Dados geométricos-Wall Sweeps - Type: Wall Sweep: REVIGRÉS-OMNISTONE-RB-8X120-SOFT-IRON
IFC.REVIGRÉS-Dados de sustentabilidade-Wall Sweeps - Type: Wall Sweep: REVIGRÉS-OMNISTONE-RB-8X120-SOFT-IRON

# IfcBuildingElementProxy: Wall Sweep:REVIGRÉS-OMNISTONE-RB-8X120-SOFT-JET, Wall Sweep:REVIGRÉS-OMNISTONE-RB-8X120-SOFT-JET:181719
In: Level 1
Type - Pset_ManufacturerTypeInformation - Manufacturer: REVIGRÉS
Type - Pset_ProductRequirements - Category: Wall Sweeps
Type - IFC.REVIGRÉS-Dados gerais-Wall Sweeps - Nome: REVIGRÉS-OMNISTONE-RB-8X120-SOFT-JET; TipoProduto: Prensado a seco: grupo BIa UGL | Grés porcelânico técnico; NumeroDeRegistoDAP: EPD-REV-20240006-CCC1-EN; ReferenciaDAP: -; UrlDOP: -
Type - IFC.REVIGRÉS-Dados do fabricante-Wall Sweeps - FabricanteURL: https://www.revigres.pt/; ReferenciaModelo: Omnistone; Acabamento: SOFT; IdentificadorDoOperadorEconomico: 501840856; UrlFabricanteArtigo: https://www.revigres.pt/colecoes/omnistone; PaisOrigem: Portugal
Type - IFC.REVIGRÉS-Dados de desempenho-Wall Sweeps - Rectilinearidade: ± 0.2% máx.± 0.8 mm; Ortogonalidade: ± 0.2% máx.± 1.5 mm; PlanaridadeDaSuperficie: ± 0.3% máx. ± 1.8 mm; AbsorcaoDeAgua: < 0.05%; ModuloDeRuptura: > 45 N/mm130; ResistenciaAFlexao: ≥ 3500 N; ResistenciaAAbrasaoProfunda: < 120 mm131; DilatacaoTermicaLinear: ≤ 8,0x10-6 °C-1; ResistenciaAoChoqueTermico: Resiste; DurabilidadeResistenciaAoGeloDegelo: Resiste; ResistenciaAsManchas: Class 5; ResistenciaABaixasConcentracoesDeAcidosEAlcalis: Classe LA; ResistenciaAAltasConcentracoesDeAcidosEAlcalis: Classe HA; LibertacaoDeCadmio: 0; LibertacaoDeChumbo: 0
Type - IFC.REVIGRÉS-Dados de especificação-Wall Sweeps - VariacaoTonalidade: 3; NivelDeTrafego: 5; EPavimento: Não; ERevestimento: Sim; EExterno: Sim
Type - IFC.REVIGRÉS-Dados geométricos-Wall Sweeps - AlturaNominal: 9.8 mm; ComprimentoNominal: 8 mm; LarguraNominal: 118.6 mm
Type - IFC.REVIGRÉS-Dados de sustentabilidade-Wall Sweeps - ItemEParcialmenteReciclado: 0; PotencialPrivacaoDeAguaConsumoDeAguaPonderado: 4.5; EnergiaTermicaExportada: 0; ItemENovo: Sim; ItemEReciclado: Não; VidaÚtilEsperada: 50; SubstanciasPerigosas: Não; PotencialDeEsgotamentoAbioticoDosRecursosFosseis: 203; PotencialDeEsgotamentoAbioticoDosRecursosNaoFosseisMineraisEMetais: 0.000701; PotencialDeAquecimentoGlobalBiogenico: -0.48; CombustiveisFosseisComPotencialDeAquecimentoGlobal: 13.9; PotencialDeAquecimentoGlobalUsoDoSoloEMudancaDeUsoDoSolo: 0.0246; PotencialDeEutrofizacaoFraccaoDeNutrientesQueAtingemOCompartimentoFinalDeAguaDoce: 0.000189; PotencialDeEutrofizacaoFraccaoDeNutrientesQueAtingemOCompartimentoFinalMarinho: 0.0122; EnergiaRecuperada: 0.00739; ConsumoDeAguaDoce: 0.113; UtilizacaoLiquidaDeAguaDoce: 0.113; ResiduosPerigososEliminados: 0.00221; ResiduosNaoPerigososEliminados: 1.83; MassaTotalDeResiduosRadioactivosEliminados: 0.000394; EnergiaElectricaExportada: 1.55; MateriaisParaRecuperacaoDeEnergia: 0.00739; MateriaisParaReciclagem: 0.0253; UnidadeEPD: 1 m²
Pset_ProvisionForVoid - Shape: Undefined; Width: 1000 mm; Depth: 1000 mm
IFC.REVIGRÉS-Dados do fabricante-Wall Sweeps - Type: Wall Sweep: REVIGRÉS-OMNISTONE-RB-8X120-SOFT-JET
IFC.REVIGRÉS-Dados de desempenho-Wall Sweeps - Type: Wall Sweep: REVIGRÉS-OMNISTONE-RB-8X120-SOFT-JET
IFC.REVIGRÉS-Dados de especificação-Wall Sweeps - Type: Wall Sweep: REVIGRÉS-OMNISTONE-RB-8X120-SOFT-JET
IFC.REVIGRÉS-Dados geométricos-Wall Sweeps - Type: Wall Sweep: REVIGRÉS-OMNISTONE-RB-8X120-SOFT-JET
IFC.REVIGRÉS-Dados de sustentabilidade-Wall Sweeps - Type: Wall Sweep: REVIGRÉS-OMNISTONE-RB-8X120-SOFT-JET

# IfcBuildingElementProxy: Wall Sweep:REVIGRÉS-OMNISTONE-RB-8X120-SOFT-PLATINA, Wall Sweep:REVIGRÉS-OMNISTONE-RB-8X120-SOFT-PLATINA:181731
In: Level 1
Type - Pset_ManufacturerTypeInformation - Manufacturer: REVIGRÉS
Type - Pset_ProductRequirements - Category: Wall Sweeps
Type - IFC.REVIGRÉS-Dados gerais-Wall Sweeps - Nome: REVIGRÉS-OMNISTONE-RB-8X120-SOFT-PLATINA; TipoProduto: Prensado a seco: grupo BIa UGL | Grés porcelânico técnico; NumeroDeRegistoDAP: EPD-REV-20240006-CCC1-EN; ReferenciaDAP: -; UrlDOP: -
Type - IFC.REVIGRÉS-Dados do fabricante-Wall Sweeps - FabricanteURL: https://www.revigres.pt/; ReferenciaModelo: Omnistone; Acabamento: SOFT; IdentificadorDoOperadorEconomico: 501840856; UrlFabricanteArtigo: https://www.revigres.pt/colecoes/omnistone; PaisOrigem: Portugal
Type - IFC.REVIGRÉS-Dados de desempenho-Wall Sweeps - Rectilinearidade: ± 0.2% máx.± 0.8 mm; Ortogonalidade: ± 0.2% máx.± 1.5 mm; PlanaridadeDaSuperficie: ± 0.3% máx. ± 1.8 mm; AbsorcaoDeAgua: < 0.05%; ModuloDeRuptura: > 45 N/mm130; ResistenciaAFlexao: ≥ 3500 N; ResistenciaAAbrasaoProfunda: < 120 mm131; DilatacaoTermicaLinear: ≤ 8,0x10-6 °C-1; ResistenciaAoChoqueTermico: Resiste; DurabilidadeResistenciaAoGeloDegelo: Resiste; ResistenciaAsManchas: Class 5; ResistenciaABaixasConcentracoesDeAcidosEAlcalis: Classe LA; ResistenciaAAltasConcentracoesDeAcidosEAlcalis: Classe HA; LibertacaoDeCadmio: 0; LibertacaoDeChumbo: 0
Type - IFC.REVIGRÉS-Dados de especificação-Wall Sweeps - VariacaoTonalidade: 3; NivelDeTrafego: 5; EPavimento: Não; ERevestimento: Sim; EExterno: Sim
Type - IFC.REVIGRÉS-Dados geométricos-Wall Sweeps - AlturaNominal: 9.8 mm; ComprimentoNominal: 8 mm; LarguraNominal: 118.6 mm
Type - IFC.REVIGRÉS-Dados de sustentabilidade-Wall Sweeps - ItemEParcialmenteReciclado: 0; PotencialPrivacaoDeAguaConsumoDeAguaPonderado: 4.5; EnergiaTermicaExportada: 0; ItemENovo: Sim; ItemEReciclado: Não; VidaÚtilEsperada: 50; SubstanciasPerigosas: Não; PotencialDeEsgotamentoAbioticoDosRecursosFosseis: 203; PotencialDeEsgotamentoAbioticoDosRecursosNaoFosseisMineraisEMetais: 0.000701; PotencialDeAquecimentoGlobalBiogenico: -0.48; CombustiveisFosseisComPotencialDeAquecimentoGlobal: 13.9; PotencialDeAquecimentoGlobalUsoDoSoloEMudancaDeUsoDoSolo: 0.0246; PotencialDeEutrofizacaoFraccaoDeNutrientesQueAtingemOCompartimentoFinalDeAguaDoce: 0.000189; PotencialDeEutrofizacaoFraccaoDeNutrientesQueAtingemOCompartimentoFinalMarinho: 0.0122; EnergiaRecuperada: 0.00739; ConsumoDeAguaDoce: 0.113; UtilizacaoLiquidaDeAguaDoce: 0.113; ResiduosPerigososEliminados: 0.00221; ResiduosNaoPerigososEliminados: 1.83; MassaTotalDeResiduosRadioactivosEliminados: 0.000394; EnergiaElectricaExportada: 1.55; MateriaisParaRecuperacaoDeEnergia: 0.00739; MateriaisParaReciclagem: 0.0253; UnidadeEPD: 1 m²
Pset_ProvisionForVoid - Shape: Undefined; Width: 1000 mm; Depth: 1000 mm
IFC.REVIGRÉS-Dados do fabricante-Wall Sweeps - Type: Wall Sweep: REVIGRÉS-OMNISTONE-RB-8X120-SOFT-PLATINA
IFC.REVIGRÉS-Dados de desempenho-Wall Sweeps - Type: Wall Sweep: REVIGRÉS-OMNISTONE-RB-8X120-SOFT-PLATINA
IFC.REVIGRÉS-Dados de especificação-Wall Sweeps - Type: Wall Sweep: REVIGRÉS-OMNISTONE-RB-8X120-SOFT-PLATINA
IFC.REVIGRÉS-Dados geométricos-Wall Sweeps - Type: Wall Sweep: REVIGRÉS-OMNISTONE-RB-8X120-SOFT-PLATINA
IFC.REVIGRÉS-Dados de sustentabilidade-Wall Sweeps - Type: Wall Sweep: REVIGRÉS-OMNISTONE-RB-8X120-SOFT-PLATINA

# IfcBuildingElementProxy: Wall Sweep:REVIGRÉS-OMNISTONE-RB-8X120-SOFT-ROPE, Wall Sweep:REVIGRÉS-OMNISTONE-RB-8X120-SOFT-ROPE:181743
In: Level 1
Type - Pset_ManufacturerTypeInformation - Manufacturer: REVIGRÉS
Type - Pset_ProductRequirements - Category: Wall Sweeps
Type - IFC.REVIGRÉS-Dados gerais-Wall Sweeps - Nome: REVIGRÉS-OMNISTONE-RB-8X120-SOFT-ROPE; TipoProduto: Prensado a seco: grupo BIa UGL | Grés porcelânico técnico; NumeroDeRegistoDAP: EPD-REV-20240006-CCC1-EN; ReferenciaDAP: -; UrlDOP: -
Type - IFC.REVIGRÉS-Dados do fabricante-Wall Sweeps - FabricanteURL: https://www.revigres.pt/; ReferenciaModelo: Omnistone; Acabamento: SOFT; IdentificadorDoOperadorEconomico: 501840856; UrlFabricanteArtigo: https://www.revigres.pt/colecoes/omnistone; PaisOrigem: Portugal
Type - IFC.REVIGRÉS-Dados de desempenho-Wall Sweeps - Rectilinearidade: ± 0.2% máx.± 0.8 mm; Ortogonalidade: ± 0.2% máx.± 1.5 mm; PlanaridadeDaSuperficie: ± 0.3% máx. ± 1.8 mm; AbsorcaoDeAgua: < 0.05%; ModuloDeRuptura: > 45 N/mm130; ResistenciaAFlexao: ≥ 3500 N; ResistenciaAAbrasaoProfunda: < 120 mm131; DilatacaoTermicaLinear: ≤ 8,0x10-6 °C-1; ResistenciaAoChoqueTermico: Resiste; DurabilidadeResistenciaAoGeloDegelo: Resiste; ResistenciaAsManchas: Class 5; ResistenciaABaixasConcentracoesDeAcidosEAlcalis: Classe LA; ResistenciaAAltasConcentracoesDeAcidosEAlcalis: Classe HA; LibertacaoDeCadmio: 0; LibertacaoDeChumbo: 0
Type - IFC.REVIGRÉS-Dados de especificação-Wall Sweeps - VariacaoTonalidade: 3; NivelDeTrafego: 5; EPavimento: Não; ERevestimento: Sim; EExterno: Sim
Type - IFC.REVIGRÉS-Dados geométricos-Wall Sweeps - AlturaNominal: 9.8 mm; ComprimentoNominal: 8 mm; LarguraNominal: 118.6 mm
Type - IFC.REVIGRÉS-Dados de sustentabilidade-Wall Sweeps - ItemEParcialmenteReciclado: 0; PotencialPrivacaoDeAguaConsumoDeAguaPonderado: 4.5; EnergiaTermicaExportada: 0; ItemENovo: Sim; ItemEReciclado: Não; VidaÚtilEsperada: 50; SubstanciasPerigosas: Não; PotencialDeEsgotamentoAbioticoDosRecursosFosseis: 203; PotencialDeEsgotamentoAbioticoDosRecursosNaoFosseisMineraisEMetais: 0.000701; PotencialDeAquecimentoGlobalBiogenico: -0.48; CombustiveisFosseisComPotencialDeAquecimentoGlobal: 13.9; PotencialDeAquecimentoGlobalUsoDoSoloEMudancaDeUsoDoSolo: 0.0246; PotencialDeEutrofizacaoFraccaoDeNutrientesQueAtingemOCompartimentoFinalDeAguaDoce: 0.000189; PotencialDeEutrofizacaoFraccaoDeNutrientesQueAtingemOCompartimentoFinalMarinho: 0.0122; EnergiaRecuperada: 0.00739; ConsumoDeAguaDoce: 0.113; UtilizacaoLiquidaDeAguaDoce: 0.113; ResiduosPerigososEliminados: 0.00221; ResiduosNaoPerigososEliminados: 1.83; MassaTotalDeResiduosRadioactivosEliminados: 0.000394; EnergiaElectricaExportada: 1.55; MateriaisParaRecuperacaoDeEnergia: 0.00739; MateriaisParaReciclagem: 0.0253; UnidadeEPD: 1 m²
Pset_ProvisionForVoid - Shape: Undefined; Width: 1000 mm; Depth: 1000 mm
IFC.REVIGRÉS-Dados do fabricante-Wall Sweeps - Type: Wall Sweep: REVIGRÉS-OMNISTONE-RB-8X120-SOFT-ROPE
IFC.REVIGRÉS-Dados de desempenho-Wall Sweeps - Type: Wall Sweep: REVIGRÉS-OMNISTONE-RB-8X120-SOFT-ROPE
IFC.REVIGRÉS-Dados de especificação-Wall Sweeps - Type: Wall Sweep: REVIGRÉS-OMNISTONE-RB-8X120-SOFT-ROPE
IFC.REVIGRÉS-Dados geométricos-Wall Sweeps - Type: Wall Sweep: REVIGRÉS-OMNISTONE-RB-8X120-SOFT-ROPE
IFC.REVIGRÉS-Dados de sustentabilidade-Wall Sweeps - Type: Wall Sweep: REVIGRÉS-OMNISTONE-RB-8X120-SOFT-ROPE

# IfcBuildingElementProxy: Wall Sweep:REVIGRÉS-OMNISTONE-RB-8X45-MATTRECT-BONE, Wall Sweep:REVIGRÉS-OMNISTONE-RB-8X45-MATTRECT-BONE:181576
In: Level 1
Type - Pset_ManufacturerTypeInformation - Manufacturer: REVIGRÉS
Type - Pset_ProductRequirements - Category: Wall Sweeps
Type - IFC.REVIGRÉS-Dados gerais-Wall Sweeps - Nome: REVIGRÉS-OMNISTONE-RB-8X45-MATT RECT-BONE; TipoProduto: Prensado a seco: grupo BIa UGL | Grés porcelânico técnico; NumeroDeRegistoDAP: EPD-REV-20240006-CCC1-EN; ReferenciaDAP: -; UrlDOP: -
Type - IFC.REVIGRÉS-Dados do fabricante-Wall Sweeps - FabricanteURL: https://www.revigres.pt/; ReferenciaModelo: Omnistone; Acabamento: MATT RECT; IdentificadorDoOperadorEconomico: 501840856; UrlFabricanteArtigo: https://www.revigres.pt/colecoes/omnistone; PaisOrigem: Portugal
Type - IFC.REVIGRÉS-Dados de desempenho-Wall Sweeps - Rectilinearidade: ± 0.2% máx.± 0.8 mm; Ortogonalidade: ± 0.2% máx.± 1.5 mm; PlanaridadeDaSuperficie: ± 0.3% máx. ± 1.8 mm; AbsorcaoDeAgua: < 0.05%; ModuloDeRuptura: > 45 N/mm²; ResistenciaAFlexao: ≥ 3500 N; ResistenciaAAbrasaoProfunda: < 120 mm³; DilatacaoTermicaLinear: ≤ 8,0x10-6 °C-1; ResistenciaAoChoqueTermico: Resiste; DurabilidadeResistenciaAoGeloDegelo: Resiste; ResistenciaAoEscorregamentoDIN51130: R10; ResistenciaAoEscorregamentoDIN51097: B; ResistenciaAoEscorregamentoENV51097: B; ResistenciaAoDeslizamentoENV12633: Class 2; ResistenciaAoEscorregamentoBS7976: >36; ResistenciaAoEscorregamentoANSIA1371: ≥0,42; ResistenciaAoEscorregamentoENV12633: Class 2; ResistenciaAoDeslizamentoBS7976: >36; ResistenciaAsManchas: Class 5; ResistenciaABaixasConcentracoesDeAcidosEAlcalis: Classe LA; ResistenciaAAltasConcentracoesDeAcidosEAlcalis: Classe HA; LibertacaoDeCadmio: 0; LibertacaoDeChumbo: 0
Type - IFC.REVIGRÉS-Dados de especificação-Wall Sweeps - VariacaoTonalidade: 3; NivelDeTrafego: 5; EPavimento: Não; ERevestimento: Sim; EExterno: Sim
Type - IFC.REVIGRÉS-Dados geométricos-Wall Sweeps - AlturaNominal: 10.5 mm; ComprimentoNominal: 8 mm; LarguraNominal: 44.35 mm
Type - IFC.REVIGRÉS-Dados de sustentabilidade-Wall Sweeps - ItemEParcialmenteReciclado: 0; PotencialPrivacaoDeAguaConsumoDeAguaPonderado: 4.5; EnergiaTermicaExportada: 0; ItemENovo: Sim; ItemEReciclado: Não; VidaÚtilEsperada: 50; SubstanciasPerigosas: Não; PotencialDeEsgotamentoAbioticoDosRecursosFosseis: 203; PotencialDeEsgotamentoAbioticoDosRecursosNaoFosseisMineraisEMetais: 0.000701; PotencialDeAquecimentoGlobalBiogenico: -0.48; CombustiveisFosseisComPotencialDeAquecimentoGlobal: 13.9; PotencialDeAquecimentoGlobalUsoDoSoloEMudancaDeUsoDoSolo: 0.0246; PotencialDeEutrofizacaoFraccaoDeNutrientesQueAtingemOCompartimentoFinalDeAguaDoce: 0.000189; PotencialDeEutrofizacaoFraccaoDeNutrientesQueAtingemOCompartimentoFinalMarinho: 0.0122; EnergiaRecuperada: 0.00739; ConsumoDeAguaDoce: 0.113; UtilizacaoLiquidaDeAguaDoce: 0.113; ResiduosPerigososEliminados: 0.00221; ResiduosNaoPerigososEliminados: 1.83; MassaTotalDeResiduosRadioactivosEliminados: 0.000394; EnergiaElectricaExportada: 1.55; MateriaisParaRecuperacaoDeEnergia: 0.00739; MateriaisParaReciclagem: 0.0253; UnidadeEPD: 1 m²
Pset_ProvisionForVoid - Shape: Undefined; Width: 1000 mm; Depth: 1000 mm
IFC.REVIGRÉS-Dados do fabricante-Wall Sweeps - Type: Wall Sweep: REVIGRÉS-OMNISTONE-RB-8X45-MATTRECT-BONE
IFC.REVIGRÉS-Dados de desempenho-Wall Sweeps - Type: Wall Sweep: REVIGRÉS-OMNISTONE-RB-8X45-MATTRECT-BONE
IFC.REVIGRÉS-Dados de especificação-Wall Sweeps - Type: Wall Sweep: REVIGRÉS-OMNISTONE-RB-8X45-MATTRECT-BONE
IFC.REVIGRÉS-Dados geométricos-Wall Sweeps - Type: Wall Sweep: REVIGRÉS-OMNISTONE-RB-8X45-MATTRECT-BONE
IFC.REVIGRÉS-Dados de sustentabilidade-Wall Sweeps - Type: Wall Sweep: REVIGRÉS-OMNISTONE-RB-8X45-MATTRECT-BONE

# IfcBuildingElementProxy: Wall Sweep:REVIGRÉS-OMNISTONE-RB-8X45-MATTRECT-ICE, Wall Sweep:REVIGRÉS-OMNISTONE-RB-8X45-MATTRECT-ICE:181686
In: Level 1
Type - Pset_ManufacturerTypeInformation - Manufacturer: REVIGRÉS
Type - Pset_ProductRequirements - Category: Wall Sweeps
Type - IFC.REVIGRÉS-Dados gerais-Wall Sweeps - Nome: REVIGRÉS-OMNISTONE-RB-8X45-MATT RECT-ICE; TipoProduto: Prensado a seco: grupo BIa UGL | Grés porcelânico técnico; NumeroDeRegistoDAP: EPD-REV-20240006-CCC1-EN; ReferenciaDAP: -; UrlDOP: -
Type - IFC.REVIGRÉS-Dados do fabricante-Wall Sweeps - FabricanteURL: https://www.revigres.pt/; ReferenciaModelo: Omnistone; Acabamento: MATT RECT; IdentificadorDoOperadorEconomico: 501840856; UrlFabricanteArtigo: https://www.revigres.pt/colecoes/omnistone; PaisOrigem: Portugal
Type - IFC.REVIGRÉS-Dados de desempenho-Wall Sweeps - Rectilinearidade: ± 0.2% máx.± 0.8 mm; Ortogonalidade: ± 0.2% máx.± 1.5 mm; PlanaridadeDaSuperficie: ± 0.3% máx. ± 1.8 mm; AbsorcaoDeAgua: < 0.05%; ModuloDeRuptura: > 45 N/mm²; ResistenciaAFlexao: ≥ 3500 N; ResistenciaAAbrasaoProfunda: < 120 mm³; DilatacaoTermicaLinear: ≤ 8,0x10-6 °C-1; ResistenciaAoChoqueTermico: Resiste; DurabilidadeResistenciaAoGeloDegelo: Resiste; ResistenciaAoEscorregamentoDIN51130: R10; ResistenciaAoEscorregamentoDIN51097: B; ResistenciaAoEscorregamentoENV51097: B; ResistenciaAoDeslizamentoENV12633: Class 2; ResistenciaAoEscorregamentoBS7976: >36; ResistenciaAoEscorregamentoANSIA1371: ≥0,42; ResistenciaAoEscorregamentoENV12633: Class 2; ResistenciaAoDeslizamentoBS7976: >36; ResistenciaAsManchas: Class 5; ResistenciaABaixasConcentracoesDeAcidosEAlcalis: Classe LA; ResistenciaAAltasConcentracoesDeAcidosEAlcalis: Classe HA; LibertacaoDeCadmio: 0; LibertacaoDeChumbo: 0
Type - IFC.REVIGRÉS-Dados de especificação-Wall Sweeps - VariacaoTonalidade: 3; NivelDeTrafego: 5; EPavimento: Não; ERevestimento: Sim; EExterno: Sim
Type - IFC.REVIGRÉS-Dados geométricos-Wall Sweeps - AlturaNominal: 10.5 mm; ComprimentoNominal: 8 mm; LarguraNominal: 44.35 mm
Type - IFC.REVIGRÉS-Dados de sustentabilidade-Wall Sweeps - ItemEParcialmenteReciclado: 0; PotencialPrivacaoDeAguaConsumoDeAguaPonderado: 4.5; EnergiaTermicaExportada: 0; ItemENovo: Sim; ItemEReciclado: Não; VidaÚtilEsperada: 50; SubstanciasPerigosas: Não; PotencialDeEsgotamentoAbioticoDosRecursosFosseis: 203; PotencialDeEsgotamentoAbioticoDosRecursosNaoFosseisMineraisEMetais: 0.000701; PotencialDeAquecimentoGlobalBiogenico: -0.48; CombustiveisFosseisComPotencialDeAquecimentoGlobal: 13.9; PotencialDeAquecimentoGlobalUsoDoSoloEMudancaDeUsoDoSolo: 0.0246; PotencialDeEutrofizacaoFraccaoDeNutrientesQueAtingemOCompartimentoFinalDeAguaDoce: 0.000189; PotencialDeEutrofizacaoFraccaoDeNutrientesQueAtingemOCompartimentoFinalMarinho: 0.0122; EnergiaRecuperada: 0.00739; ConsumoDeAguaDoce: 0.113; UtilizacaoLiquidaDeAguaDoce: 0.113; ResiduosPerigososEliminados: 0.00221; ResiduosNaoPerigososEliminados: 1.83; MassaTotalDeResiduosRadioactivosEliminados: 0.000394; EnergiaElectricaExportada: 1.55; MateriaisParaRecuperacaoDeEnergia: 0.00739; MateriaisParaReciclagem: 0.0253; UnidadeEPD: 1 m²
Pset_ProvisionForVoid - Shape: Undefined; Width: 1000 mm; Depth: 1000 mm
IFC.REVIGRÉS-Dados do fabricante-Wall Sweeps - Type: Wall Sweep: REVIGRÉS-OMNISTONE-RB-8X45-MATTRECT-ICE
IFC.REVIGRÉS-Dados de desempenho-Wall Sweeps - Type: Wall Sweep: REVIGRÉS-OMNISTONE-RB-8X45-MATTRECT-ICE
IFC.REVIGRÉS-Dados de especificação-Wall Sweeps - Type: Wall Sweep: REVIGRÉS-OMNISTONE-RB-8X45-MATTRECT-ICE
IFC.REVIGRÉS-Dados geométricos-Wall Sweeps - Type: Wall Sweep: REVIGRÉS-OMNISTONE-RB-8X45-MATTRECT-ICE
IFC.REVIGRÉS-Dados de sustentabilidade-Wall Sweeps - Type: Wall Sweep: REVIGRÉS-OMNISTONE-RB-8X45-MATTRECT-ICE

# IfcBuildingElementProxy: Wall Sweep:REVIGRÉS-OMNISTONE-RB-8X45-MATTRECT-IRON, Wall Sweep:REVIGRÉS-OMNISTONE-RB-8X45-MATTRECT-IRON:181698
In: Level 1
Type - Pset_ManufacturerTypeInformation - Manufacturer: REVIGRÉS
Type - Pset_ProductRequirements - Category: Wall Sweeps
Type - IFC.REVIGRÉS-Dados gerais-Wall Sweeps - Nome: REVIGRÉS-OMNISTONE-RB-8X45-MATT RECT-IRON; TipoProduto: Prensado a seco: grupo BIa UGL | Grés porcelânico técnico; NumeroDeRegistoDAP: EPD-REV-20240006-CCC1-EN; ReferenciaDAP: -; UrlDOP: -
Type - IFC.REVIGRÉS-Dados do fabricante-Wall Sweeps - FabricanteURL: https://www.revigres.pt/; ReferenciaModelo: Omnistone; Acabamento: MATT RECT; IdentificadorDoOperadorEconomico: 501840856; UrlFabricanteArtigo: https://www.revigres.pt/colecoes/omnistone; PaisOrigem: Portugal
Type - IFC.REVIGRÉS-Dados de desempenho-Wall Sweeps - Rectilinearidade: ± 0.2% máx.± 0.8 mm; Ortogonalidade: ± 0.2% máx.± 1.5 mm; PlanaridadeDaSuperficie: ± 0.3% máx. ± 1.8 mm; AbsorcaoDeAgua: < 0.05%; ModuloDeRuptura: > 45 N/mm²; ResistenciaAFlexao: ≥ 3500 N; ResistenciaAAbrasaoProfunda: < 120 mm³; DilatacaoTermicaLinear: ≤ 8,0x10-6 °C-1; ResistenciaAoChoqueTermico: Resiste; DurabilidadeResistenciaAoGeloDegelo: Resiste; ResistenciaAoEscorregamentoDIN51130: R10; ResistenciaAoEscorregamentoDIN51097: B; ResistenciaAoEscorregamentoENV51097: B; ResistenciaAoDeslizamentoENV12633: Class 2; ResistenciaAoEscorregamentoBS7976: >36; ResistenciaAoEscorregamentoANSIA1371: ≥0,42; ResistenciaAoEscorregamentoENV12633: Class 2; ResistenciaAoDeslizamentoBS7976: >36; ResistenciaAsManchas: Class 5; ResistenciaABaixasConcentracoesDeAcidosEAlcalis: Classe LA; ResistenciaAAltasConcentracoesDeAcidosEAlcalis: Classe HA; LibertacaoDeCadmio: 0; LibertacaoDeChumbo: 0
Type - IFC.REVIGRÉS-Dados de especificação-Wall Sweeps - VariacaoTonalidade: 3; NivelDeTrafego: 5; EPavimento: Não; ERevestimento: Sim; EExterno: Sim
Type - IFC.REVIGRÉS-Dados geométricos-Wall Sweeps - AlturaNominal: 10.5 mm; ComprimentoNominal: 8 mm; LarguraNominal: 44.35 mm
Type - IFC.REVIGRÉS-Dados de sustentabilidade-Wall Sweeps - PotencialPrivacaoDeAguaConsumoDeAguaPonderado: 4.5; EnergiaTermicaExportada: 0; ItemENovo: Sim; ItemEParcialmenteReciclado: 0.14; ItemEReciclado: Sim; VidaÚtilEsperada: 50; SubstanciasPerigosas: Não; PotencialDeEsgotamentoAbioticoDosRecursosFosseis: 203; PotencialDeEsgotamentoAbioticoDosRecursosNaoFosseisMineraisEMetais: 0.000701; PotencialDeAquecimentoGlobalBiogenico: -0.48; CombustiveisFosseisComPotencialDeAquecimentoGlobal: 13.9; PotencialDeAquecimentoGlobalUsoDoSoloEMudancaDeUsoDoSolo: 0.0246; PotencialDeEutrofizacaoFraccaoDeNutrientesQueAtingemOCompartimentoFinalDeAguaDoce: 0.000189; PotencialDeEutrofizacaoFraccaoDeNutrientesQueAtingemOCompartimentoFinalMarinho: 0.0122; EnergiaRecuperada: 0.00739; ConsumoDeAguaDoce: 0.113; UtilizacaoLiquidaDeAguaDoce: 0.113; ResiduosPerigososEliminados: 0.00221; ResiduosNaoPerigososEliminados: 1.83; MassaTotalDeResiduosRadioactivosEliminados: 0.000394; EnergiaElectricaExportada: 1.55; MateriaisParaRecuperacaoDeEnergia: 0.00739; MateriaisParaReciclagem: 0.0253; UnidadeEPD: 1 m²
Pset_ProvisionForVoid - Shape: Undefined; Width: 1000 mm; Depth: 1000 mm
IFC.REVIGRÉS-Dados do fabricante-Wall Sweeps - Type: Wall Sweep: REVIGRÉS-OMNISTONE-RB-8X45-MATTRECT-IRON
IFC.REVIGRÉS-Dados de desempenho-Wall Sweeps - Type: Wall Sweep: REVIGRÉS-OMNISTONE-RB-8X45-MATTRECT-IRON
IFC.REVIGRÉS-Dados de especificação-Wall Sweeps - Type: Wall Sweep: REVIGRÉS-OMNISTONE-RB-8X45-MATTRECT-IRON
IFC.REVIGRÉS-Dados geométricos-Wall Sweeps - Type: Wall Sweep: REVIGRÉS-OMNISTONE-RB-8X45-MATTRECT-IRON
IFC.REVIGRÉS-Dados de sustentabilidade-Wall Sweeps - Type: Wall Sweep: REVIGRÉS-OMNISTONE-RB-8X45-MATTRECT-IRON

# IfcBuildingElementProxy: Wall Sweep:REVIGRÉS-OMNISTONE-RB-8X45-MATTRECT-JET, Wall Sweep:REVIGRÉS-OMNISTONE-RB-8X45-MATTRECT-JET:181710
In: Level 1
Type - Pset_ManufacturerTypeInformation - Manufacturer: REVIGRÉS
Type - Pset_ProductRequirements - Category: Wall Sweeps
Type - IFC.REVIGRÉS-Dados gerais-Wall Sweeps - Nome: REVIGRÉS-OMNISTONE-RB-8X45-MATT RECT-JET; TipoProduto: Prensado a seco: grupo BIa UGL | Grés porcelânico técnico; NumeroDeRegistoDAP: EPD-REV-20240006-CCC1-EN; ReferenciaDAP: -; UrlDOP: -
Type - IFC.REVIGRÉS-Dados do fabricante-Wall Sweeps - FabricanteURL: https://www.revigres.pt/; ReferenciaModelo: Omnistone; Acabamento: MATT RECT; IdentificadorDoOperadorEconomico: 501840856; UrlFabricanteArtigo: https://www.revigres.pt/colecoes/omnistone; PaisOrigem: Portugal
Type - IFC.REVIGRÉS-Dados de desempenho-Wall Sweeps - Rectilinearidade: ± 0.2% máx.± 0.8 mm; Ortogonalidade: ± 0.2% máx.± 1.5 mm; PlanaridadeDaSuperficie: ± 0.3% máx. ± 1.8 mm; AbsorcaoDeAgua: < 0.05%; ModuloDeRuptura: > 45 N/mm²; ResistenciaAFlexao: ≥ 3500 N; ResistenciaAAbrasaoProfunda: < 120 mm³; DilatacaoTermicaLinear: ≤ 8,0x10-6 °C-1; ResistenciaAoChoqueTermico: Resiste; DurabilidadeResistenciaAoGeloDegelo: Resiste; ResistenciaAoEscorregamentoDIN51130: R10; ResistenciaAoEscorregamentoDIN51097: B; ResistenciaAoEscorregamentoENV51097: B; ResistenciaAoDeslizamentoENV12633: Class 2; ResistenciaAoEscorregamentoBS7976: >36; ResistenciaAoEscorregamentoANSIA1371: ≥0,42; ResistenciaAoEscorregamentoENV12633: Class 2; ResistenciaAoDeslizamentoBS7976: >36; ResistenciaAsManchas: Class 5; ResistenciaABaixasConcentracoesDeAcidosEAlcalis: Classe LA; ResistenciaAAltasConcentracoesDeAcidosEAlcalis: Classe HA; LibertacaoDeCadmio: 0; LibertacaoDeChumbo: 0
Type - IFC.REVIGRÉS-Dados de especificação-Wall Sweeps - VariacaoTonalidade: 3; NivelDeTrafego: 5; EPavimento: Não; ERevestimento: Sim; EExterno: Sim
Type - IFC.REVIGRÉS-Dados geométricos-Wall Sweeps - AlturaNominal: 10.5 mm; ComprimentoNominal: 8 mm; LarguraNominal: 44.35 mm
Type - IFC.REVIGRÉS-Dados de sustentabilidade-Wall Sweeps - ItemEParcialmenteReciclado: 0; PotencialPrivacaoDeAguaConsumoDeAguaPonderado: 4.5; EnergiaTermicaExportada: 0; ItemENovo: Sim; ItemEReciclado: Não; VidaÚtilEsperada: 50; SubstanciasPerigosas: Não; PotencialDeEsgotamentoAbioticoDosRecursosFosseis: 203; PotencialDeEsgotamentoAbioticoDosRecursosNaoFosseisMineraisEMetais: 0.000701; PotencialDeAquecimentoGlobalBiogenico: -0.48; CombustiveisFosseisComPotencialDeAquecimentoGlobal: 13.9; PotencialDeAquecimentoGlobalUsoDoSoloEMudancaDeUsoDoSolo: 0.0246; PotencialDeEutrofizacaoFraccaoDeNutrientesQueAtingemOCompartimentoFinalDeAguaDoce: 0.000189; PotencialDeEutrofizacaoFraccaoDeNutrientesQueAtingemOCompartimentoFinalMarinho: 0.0122; EnergiaRecuperada: 0.00739; ConsumoDeAguaDoce: 0.113; UtilizacaoLiquidaDeAguaDoce: 0.113; ResiduosPerigososEliminados: 0.00221; ResiduosNaoPerigososEliminados: 1.83; MassaTotalDeResiduosRadioactivosEliminados: 0.000394; EnergiaElectricaExportada: 1.55; MateriaisParaRecuperacaoDeEnergia: 0.00739; MateriaisParaReciclagem: 0.0253; UnidadeEPD: 1 m²
Pset_ProvisionForVoid - Shape: Undefined; Width: 1000 mm; Depth: 1000 mm
IFC.REVIGRÉS-Dados do fabricante-Wall Sweeps - Type: Wall Sweep: REVIGRÉS-OMNISTONE-RB-8X45-MATTRECT-JET
IFC.REVIGRÉS-Dados de desempenho-Wall Sweeps - Type: Wall Sweep: REVIGRÉS-OMNISTONE-RB-8X45-MATTRECT-JET
IFC.REVIGRÉS-Dados de especificação-Wall Sweeps - Type: Wall Sweep: REVIGRÉS-OMNISTONE-RB-8X45-MATTRECT-JET
IFC.REVIGRÉS-Dados geométricos-Wall Sweeps - Type: Wall Sweep: REVIGRÉS-OMNISTONE-RB-8X45-MATTRECT-JET
IFC.REVIGRÉS-Dados de sustentabilidade-Wall Sweeps - Type: Wall Sweep: REVIGRÉS-OMNISTONE-RB-8X45-MATTRECT-JET

# IfcBuildingElementProxy: Wall Sweep:REVIGRÉS-OMNISTONE-RB-8X45-MATTRECT-PLATINA, Wall Sweep:REVIGRÉS-OMNISTONE-RB-8X45-MATTRECT-PLATINA:181722
In: Level 1
Type - Pset_ManufacturerTypeInformation - Manufacturer: REVIGRÉS
Type - Pset_ProductRequirements - Category: Wall Sweeps
Type - IFC.REVIGRÉS-Dados gerais-Wall Sweeps - Nome: REVIGRÉS-OMNISTONE-RB-8X45-MATT RECT-PLATINA; TipoProduto: Prensado a seco: grupo BIa UGL | Grés porcelânico técnico; NumeroDeRegistoDAP: EPD-REV-20240006-CCC1-EN; ReferenciaDAP: -; UrlDOP: -
Type - IFC.REVIGRÉS-Dados do fabricante-Wall Sweeps - FabricanteURL: https://www.revigres.pt/; ReferenciaModelo: Omnistone; Acabamento: MATT RECT; IdentificadorDoOperadorEconomico: 501840856; UrlFabricanteArtigo: https://www.revigres.pt/colecoes/omnistone; PaisOrigem: Portugal
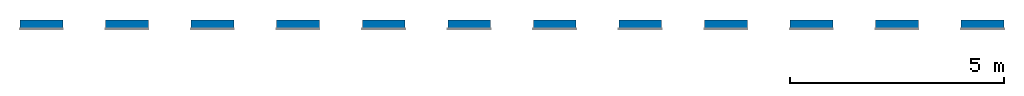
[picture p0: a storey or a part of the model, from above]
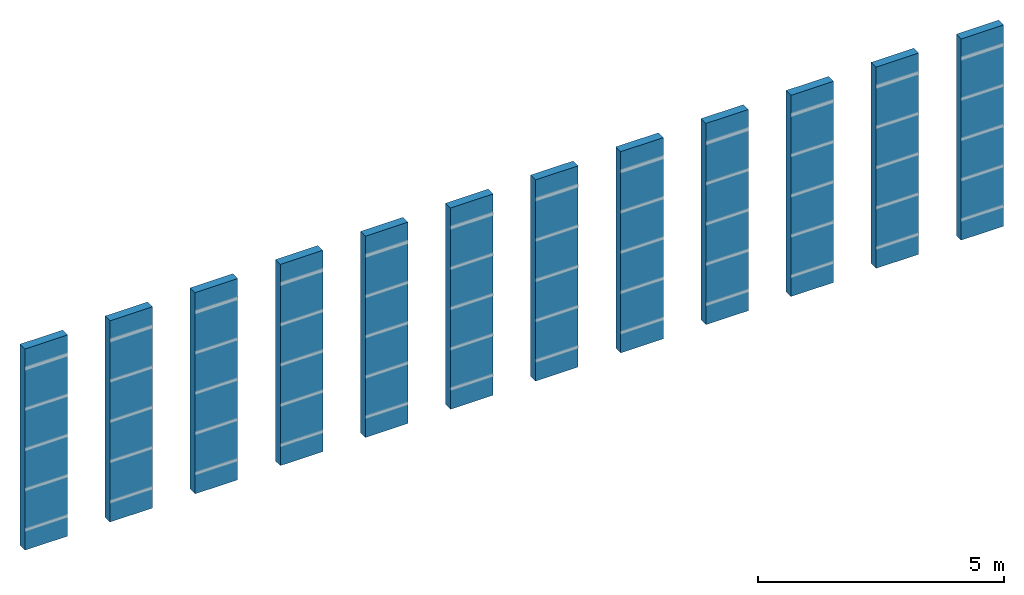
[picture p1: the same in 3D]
Properties of the parts of a building model (IFC2X3), part 3 of 4

# IfcBuildingElementProxy: Wall Sweep:REVIGRÉS-OMNISTONE-RB-8X60-SOFT-JET, Wall Sweep:REVIGRÉS-OMNISTONE-RB-8X60-SOFT-JET:181717
Type - IFC.REVIGRÉS-Dados do fabricante-Wall Sweeps - FabricanteURL: https://www.revigres.pt/; ReferenciaModelo: Omnistone; Acabamento: SOFT; IdentificadorDoOperadorEconomico: 501840856; UrlFabricanteArtigo: https://www.revigres.pt/colecoes/omnistone; PaisOrigem: Portugal
Type - IFC.REVIGRÉS-Dados de desempenho-Wall Sweeps - Rectilinearidade: ± 0.2% máx.± 0.8 mm; Ortogonalidade: ± 0.2% máx.± 1.5 mm; PlanaridadeDaSuperficie: ± 0.3% máx. ± 1.8 mm; AbsorcaoDeAgua: < 0.05%; ModuloDeRuptura: > 45 N/mm130; ResistenciaAFlexao: ≥ 3500 N; ResistenciaAAbrasaoProfunda: < 120 mm131; DilatacaoTermicaLinear: ≤ 8,0x10-6 °C-1; ResistenciaAoChoqueTermico: Resiste; DurabilidadeResistenciaAoGeloDegelo: Resiste; ResistenciaAsManchas: Class 5; ResistenciaABaixasConcentracoesDeAcidosEAlcalis: Classe LA; ResistenciaAAltasConcentracoesDeAcidosEAlcalis: Classe HA; LibertacaoDeCadmio: 0; LibertacaoDeChumbo: 0
Type - IFC.REVIGRÉS-Dados de especificação-Wall Sweeps - VariacaoTonalidade: 3; NivelDeTrafego: 5; EPavimento: Não; ERevestimento: Sim; EExterno: Sim
Type - IFC.REVIGRÉS-Dados geométricos-Wall Sweeps - AlturaNominal: 9.8 mm; ComprimentoNominal: 8 mm; LarguraNominal: 59.2 mm
Type - IFC.REVIGRÉS-Dados de sustentabilidade-Wall Sweeps - ItemEParcialmenteReciclado: 0; PotencialPrivacaoDeAguaConsumoDeAguaPonderado: 4.5; EnergiaTermicaExportada: 0; ItemENovo: Sim; ItemEReciclado: Não; VidaÚtilEsperada: 50; SubstanciasPerigosas: Não; PotencialDeEsgotamentoAbioticoDosRecursosFosseis: 203; PotencialDeEsgotamentoAbioticoDosRecursosNaoFosseisMineraisEMetais: 0.000701; PotencialDeAquecimentoGlobalBiogenico: -0.48; CombustiveisFosseisComPotencialDeAquecimentoGlobal: 13.9; PotencialDeAquecimentoGlobalUsoDoSoloEMudancaDeUsoDoSolo: 0.0246; PotencialDeEutrofizacaoFraccaoDeNutrientesQueAtingemOCompartimentoFinalDeAguaDoce: 0.000189; PotencialDeEutrofizacaoFraccaoDeNutrientesQueAtingemOCompartimentoFinalMarinho: 0.0122; EnergiaRecuperada: 0.00739; ConsumoDeAguaDoce: 0.113; UtilizacaoLiquidaDeAguaDoce: 0.113; ResiduosPerigososEliminados: 0.00221; ResiduosNaoPerigososEliminados: 1.83; MassaTotalDeResiduosRadioactivosEliminados: 0.000394; EnergiaElectricaExportada: 1.55; MateriaisParaRecuperacaoDeEnergia: 0.00739; MateriaisParaReciclagem: 0.0253; UnidadeEPD: 1 m²
Pset_ProvisionForVoid - Shape: Undefined; Width: 1000 mm; Depth: 1000 mm
IFC.REVIGRÉS-Dados do fabricante-Wall Sweeps - Type: Wall Sweep: REVIGRÉS-OMNISTONE-RB-8X60-SOFT-JET
IFC.REVIGRÉS-Dados de desempenho-Wall Sweeps - Type: Wall Sweep: REVIGRÉS-OMNISTONE-RB-8X60-SOFT-JET
IFC.REVIGRÉS-Dados de especificação-Wall Sweeps - Type: Wall Sweep: REVIGRÉS-OMNISTONE-RB-8X60-SOFT-JET
IFC.REVIGRÉS-Dados geométricos-Wall Sweeps - Type: Wall Sweep: REVIGRÉS-OMNISTONE-RB-8X60-SOFT-JET
IFC.REVIGRÉS-Dados de sustentabilidade-Wall Sweeps - Type: Wall Sweep: REVIGRÉS-OMNISTONE-RB-8X60-SOFT-JET

# IfcBuildingElementProxy: Wall Sweep:REVIGRÉS-OMNISTONE-RB-8X60-SOFT-PLATINA, Wall Sweep:REVIGRÉS-OMNISTONE-RB-8X60-SOFT-PLATINA:181729
In: Level 1
Type - Pset_ManufacturerTypeInformation - Manufacturer: REVIGRÉS
Type - Pset_ProductRequirements - Category: Wall Sweeps
Type - IFC.REVIGRÉS-Dados gerais-Wall Sweeps - Nome: REVIGRÉS-OMNISTONE-RB-8X60-SOFT-PLATINA; TipoProduto: Prensado a seco: grupo BIa UGL | Grés porcelânico técnico; NumeroDeRegistoDAP: EPD-REV-20240006-CCC1-EN; ReferenciaDAP: -; UrlDOP: -
Type - IFC.REVIGRÉS-Dados do fabricante-Wall Sweeps - FabricanteURL: https://www.revigres.pt/; ReferenciaModelo: Omnistone; Acabamento: SOFT; IdentificadorDoOperadorEconomico: 501840856; UrlFabricanteArtigo: https://www.revigres.pt/colecoes/omnistone; PaisOrigem: Portugal
Type - IFC.REVIGRÉS-Dados de desempenho-Wall Sweeps - Rectilinearidade: ± 0.2% máx.± 0.8 mm; Ortogonalidade: ± 0.2% máx.± 1.5 mm; PlanaridadeDaSuperficie: ± 0.3% máx. ± 1.8 mm; AbsorcaoDeAgua: < 0.05%; ModuloDeRuptura: > 45 N/mm130; ResistenciaAFlexao: ≥ 3500 N; ResistenciaAAbrasaoProfunda: < 120 mm131; DilatacaoTermicaLinear: ≤ 8,0x10-6 °C-1; ResistenciaAoChoqueTermico: Resiste; DurabilidadeResistenciaAoGeloDegelo: Resiste; ResistenciaAsManchas: Class 5; ResistenciaABaixasConcentracoesDeAcidosEAlcalis: Classe LA; ResistenciaAAltasConcentracoesDeAcidosEAlcalis: Classe HA; LibertacaoDeCadmio: 0; LibertacaoDeChumbo: 0
Type - IFC.REVIGRÉS-Dados de especificação-Wall Sweeps - VariacaoTonalidade: 3; NivelDeTrafego: 5; EPavimento: Não; ERevestimento: Sim; EExterno: Sim
Type - IFC.REVIGRÉS-Dados geométricos-Wall Sweeps - AlturaNominal: 9.8 mm; ComprimentoNominal: 8 mm; LarguraNominal: 59.2 mm
Type - IFC.REVIGRÉS-Dados de sustentabilidade-Wall Sweeps - ItemEParcialmenteReciclado: 0; PotencialPrivacaoDeAguaConsumoDeAguaPonderado: 4.5; EnergiaTermicaExportada: 0; ItemENovo: Sim; ItemEReciclado: Não; VidaÚtilEsperada: 50; SubstanciasPerigosas: Não; PotencialDeEsgotamentoAbioticoDosRecursosFosseis: 203; PotencialDeEsgotamentoAbioticoDosRecursosNaoFosseisMineraisEMetais: 0.000701; PotencialDeAquecimentoGlobalBiogenico: -0.48; CombustiveisFosseisComPotencialDeAquecimentoGlobal: 13.9; PotencialDeAquecimentoGlobalUsoDoSoloEMudancaDeUsoDoSolo: 0.0246; PotencialDeEutrofizacaoFraccaoDeNutrientesQueAtingemOCompartimentoFinalDeAguaDoce: 0.000189; PotencialDeEutrofizacaoFraccaoDeNutrientesQueAtingemOCompartimentoFinalMarinho: 0.0122; EnergiaRecuperada: 0.00739; ConsumoDeAguaDoce: 0.113; UtilizacaoLiquidaDeAguaDoce: 0.113; ResiduosPerigososEliminados: 0.00221; ResiduosNaoPerigososEliminados: 1.83; MassaTotalDeResiduosRadioactivosEliminados: 0.000394; EnergiaElectricaExportada: 1.55; MateriaisParaRecuperacaoDeEnergia: 0.00739; MateriaisParaReciclagem: 0.0253; UnidadeEPD: 1 m²
Pset_ProvisionForVoid - Shape: Undefined; Width: 1000 mm; Depth: 1000 mm
IFC.REVIGRÉS-Dados do fabricante-Wall Sweeps - Type: Wall Sweep: REVIGRÉS-OMNISTONE-RB-8X60-SOFT-PLATINA
IFC.REVIGRÉS-Dados de desempenho-Wall Sweeps - Type: Wall Sweep: REVIGRÉS-OMNISTONE-RB-8X60-SOFT-PLATINA
IFC.REVIGRÉS-Dados de especificação-Wall Sweeps - Type: Wall Sweep: REVIGRÉS-OMNISTONE-RB-8X60-SOFT-PLATINA
IFC.REVIGRÉS-Dados geométricos-Wall Sweeps - Type: Wall Sweep: REVIGRÉS-OMNISTONE-RB-8X60-SOFT-PLATINA
IFC.REVIGRÉS-Dados de sustentabilidade-Wall Sweeps - Type: Wall Sweep: REVIGRÉS-OMNISTONE-RB-8X60-SOFT-PLATINA

# IfcBuildingElementProxy: Wall Sweep:REVIGRÉS-OMNISTONE-RB-8X60-SOFT-ROPE, Wall Sweep:REVIGRÉS-OMNISTONE-RB-8X60-SOFT-ROPE:181741
In: Level 1
Type - Pset_ManufacturerTypeInformation - Manufacturer: REVIGRÉS
Type - Pset_ProductRequirements - Category: Wall Sweeps
Type - IFC.REVIGRÉS-Dados gerais-Wall Sweeps - Nome: REVIGRÉS-OMNISTONE-RB-8X60-SOFT-ROPE; TipoProduto: Prensado a seco: grupo BIa UGL | Grés porcelânico técnico; NumeroDeRegistoDAP: EPD-REV-20240006-CCC1-EN; ReferenciaDAP: -; UrlDOP: -
Type - IFC.REVIGRÉS-Dados do fabricante-Wall Sweeps - FabricanteURL: https://www.revigres.pt/; ReferenciaModelo: Omnistone; Acabamento: SOFT; IdentificadorDoOperadorEconomico: 501840856; UrlFabricanteArtigo: https://www.revigres.pt/colecoes/omnistone; PaisOrigem: Portugal
Type - IFC.REVIGRÉS-Dados de desempenho-Wall Sweeps - Rectilinearidade: ± 0.2% máx.± 0.8 mm; Ortogonalidade: ± 0.2% máx.± 1.5 mm; PlanaridadeDaSuperficie: ± 0.3% máx. ± 1.8 mm; AbsorcaoDeAgua: < 0.05%; ModuloDeRuptura: > 45 N/mm130; ResistenciaAFlexao: ≥ 3500 N; ResistenciaAAbrasaoProfunda: < 120 mm131; DilatacaoTermicaLinear: ≤ 8,0x10-6 °C-1; ResistenciaAoChoqueTermico: Resiste; DurabilidadeResistenciaAoGeloDegelo: Resiste; ResistenciaAsManchas: Class 5; ResistenciaABaixasConcentracoesDeAcidosEAlcalis: Classe LA; ResistenciaAAltasConcentracoesDeAcidosEAlcalis: Classe HA; LibertacaoDeCadmio: 0; LibertacaoDeChumbo: 0
Type - IFC.REVIGRÉS-Dados de especificação-Wall Sweeps - VariacaoTonalidade: 3; NivelDeTrafego: 5; EPavimento: Não; ERevestimento: Sim; EExterno: Sim
Type - IFC.REVIGRÉS-Dados geométricos-Wall Sweeps - AlturaNominal: 9.8 mm; ComprimentoNominal: 8 mm; LarguraNominal: 59.2 mm
Type - IFC.REVIGRÉS-Dados de sustentabilidade-Wall Sweeps - ItemEParcialmenteReciclado: 0; PotencialPrivacaoDeAguaConsumoDeAguaPonderado: 4.5; EnergiaTermicaExportada: 0; ItemENovo: Sim; ItemEReciclado: Não; VidaÚtilEsperada: 50; SubstanciasPerigosas: Não; PotencialDeEsgotamentoAbioticoDosRecursosFosseis: 203; PotencialDeEsgotamentoAbioticoDosRecursosNaoFosseisMineraisEMetais: 0.000701; PotencialDeAquecimentoGlobalBiogenico: -0.48; CombustiveisFosseisComPotencialDeAquecimentoGlobal: 13.9; PotencialDeAquecimentoGlobalUsoDoSoloEMudancaDeUsoDoSolo: 0.0246; PotencialDeEutrofizacaoFraccaoDeNutrientesQueAtingemOCompartimentoFinalDeAguaDoce: 0.000189; PotencialDeEutrofizacaoFraccaoDeNutrientesQueAtingemOCompartimentoFinalMarinho: 0.0122; EnergiaRecuperada: 0.00739; ConsumoDeAguaDoce: 0.113; UtilizacaoLiquidaDeAguaDoce: 0.113; ResiduosPerigososEliminados: 0.00221; ResiduosNaoPerigososEliminados: 1.83; MassaTotalDeResiduosRadioactivosEliminados: 0.000394; EnergiaElectricaExportada: 1.55; MateriaisParaRecuperacaoDeEnergia: 0.00739; MateriaisParaReciclagem: 0.0253; UnidadeEPD: 1 m²
Pset_ProvisionForVoid - Shape: Undefined; Width: 1000 mm; Depth: 1000 mm
IFC.REVIGRÉS-Dados do fabricante-Wall Sweeps - Type: Wall Sweep: REVIGRÉS-OMNISTONE-RB-8X60-SOFT-ROPE
IFC.REVIGRÉS-Dados de desempenho-Wall Sweeps - Type: Wall Sweep: REVIGRÉS-OMNISTONE-RB-8X60-SOFT-ROPE
IFC.REVIGRÉS-Dados de especificação-Wall Sweeps - Type: Wall Sweep: REVIGRÉS-OMNISTONE-RB-8X60-SOFT-ROPE
IFC.REVIGRÉS-Dados geométricos-Wall Sweeps - Type: Wall Sweep: REVIGRÉS-OMNISTONE-RB-8X60-SOFT-ROPE
IFC.REVIGRÉS-Dados de sustentabilidade-Wall Sweeps - Type: Wall Sweep: REVIGRÉS-OMNISTONE-RB-8X60-SOFT-ROPE

# IfcBuildingElementProxy: Wall Sweep:REVIGRÉS-OMNISTONE-RB-8X90-MATTRECT-BONE, Wall Sweep:REVIGRÉS-OMNISTONE-RB-8X90-MATTRECT-BONE:181676
In: Level 1
Type - Pset_ManufacturerTypeInformation - Manufacturer: REVIGRÉS
Type - Pset_ProductRequirements - Category: Wall Sweeps
Type - IFC.REVIGRÉS-Dados gerais-Wall Sweeps - Nome: REVIGRÉS-OMNISTONE-RB-8X90-MATT RECT-BONE; TipoProduto: Prensado a seco: grupo BIa UGL | Grés porcelânico técnico; NumeroDeRegistoDAP: EPD-REV-20240006-CCC1-EN; ReferenciaDAP: -; UrlDOP: -
Type - IFC.REVIGRÉS-Dados do fabricante-Wall Sweeps - FabricanteURL: https://www.revigres.pt/; ReferenciaModelo: Omnistone; Acabamento: MATT RECT; IdentificadorDoOperadorEconomico: 501840856; UrlFabricanteArtigo: https://www.revigres.pt/colecoes/omnistone; PaisOrigem: Portugal
Type - IFC.REVIGRÉS-Dados de desempenho-Wall Sweeps - Rectilinearidade: ± 0.2% máx.± 0.8 mm; Ortogonalidade: ± 0.2% máx.± 1.5 mm; PlanaridadeDaSuperficie: ± 0.3% máx. ± 1.8 mm; AbsorcaoDeAgua: < 0.05%; ModuloDeRuptura: > 45 N/mm130; ResistenciaAFlexao: ≥ 3500 N; ResistenciaAAbrasaoProfunda: < 120 mm131; DilatacaoTermicaLinear: ≤ 8,0x10-6 °C-1; ResistenciaAoChoqueTermico: Resiste; DurabilidadeResistenciaAoGeloDegelo: Resiste; ResistenciaAoEscorregamentoDIN51130: R10; ResistenciaAoEscorregamentoDIN51097: B; ResistenciaAoEscorregamentoENV51097: B; ResistenciaAoDeslizamentoENV12633: Class 2; ResistenciaAoEscorregamentoBS7976: >36; ResistenciaAoEscorregamentoANSIA1371: ≥0,42; ResistenciaAoEscorregamentoENV12633: Class 2; ResistenciaAoDeslizamentoBS7976: >36; ResistenciaAsManchas: Class 5; ResistenciaABaixasConcentracoesDeAcidosEAlcalis: Classe LA; ResistenciaAAltasConcentracoesDeAcidosEAlcalis: Classe HA; LibertacaoDeCadmio: 0; LibertacaoDeChumbo: 0
Type - IFC.REVIGRÉS-Dados de especificação-Wall Sweeps - VariacaoTonalidade: 3; NivelDeTrafego: 5; EPavimento: Não; ERevestimento: Sim; EExterno: Sim
Type - IFC.REVIGRÉS-Dados geométricos-Wall Sweeps - AlturaNominal: 10.5 mm; ComprimentoNominal: 8 mm; LarguraNominal: 88.9 mm
Type - IFC.REVIGRÉS-Dados de sustentabilidade-Wall Sweeps - ItemEParcialmenteReciclado: 0; PotencialPrivacaoDeAguaConsumoDeAguaPonderado: 4.5; EnergiaTermicaExportada: 0; ItemENovo: Sim; ItemEReciclado: Não; VidaÚtilEsperada: 50; SubstanciasPerigosas: Não; PotencialDeEsgotamentoAbioticoDosRecursosFosseis: 203; PotencialDeEsgotamentoAbioticoDosRecursosNaoFosseisMineraisEMetais: 0.000701; PotencialDeAquecimentoGlobalBiogenico: -0.48; CombustiveisFosseisComPotencialDeAquecimentoGlobal: 13.9; PotencialDeAquecimentoGlobalUsoDoSoloEMudancaDeUsoDoSolo: 0.0246; PotencialDeEutrofizacaoFraccaoDeNutrientesQueAtingemOCompartimentoFinalDeAguaDoce: 0.000189; PotencialDeEutrofizacaoFraccaoDeNutrientesQueAtingemOCompartimentoFinalMarinho: 0.0122; EnergiaRecuperada: 0.00739; ConsumoDeAguaDoce: 0.113; UtilizacaoLiquidaDeAguaDoce: 0.113; ResiduosPerigososEliminados: 0.00221; ResiduosNaoPerigososEliminados: 1.83; MassaTotalDeResiduosRadioactivosEliminados: 0.000394; EnergiaElectricaExportada: 1.55; MateriaisParaRecuperacaoDeEnergia: 0.00739; MateriaisParaReciclagem: 0.0253; UnidadeEPD: 1 m²
Pset_ProvisionForVoid - Shape: Undefined; Width: 1000 mm; Depth: 1000 mm
IFC.REVIGRÉS-Dados do fabricante-Wall Sweeps - Type: Wall Sweep: REVIGRÉS-OMNISTONE-RB-8X90-MATTRECT-BONE
IFC.REVIGRÉS-Dados de desempenho-Wall Sweeps - Type: Wall Sweep: REVIGRÉS-OMNISTONE-RB-8X90-MATTRECT-BONE
IFC.REVIGRÉS-Dados de especificação-Wall Sweeps - Type: Wall Sweep: REVIGRÉS-OMNISTONE-RB-8X90-MATTRECT-BONE
IFC.REVIGRÉS-Dados geométricos-Wall Sweeps - Type: Wall Sweep: REVIGRÉS-OMNISTONE-RB-8X90-MATTRECT-BONE
IFC.REVIGRÉS-Dados de sustentabilidade-Wall Sweeps - Type: Wall Sweep: REVIGRÉS-OMNISTONE-RB-8X90-MATTRECT-BONE

# IfcBuildingElementProxy: Wall Sweep:REVIGRÉS-OMNISTONE-RB-8X90-MATTRECT-ICE, Wall Sweep:REVIGRÉS-OMNISTONE-RB-8X90-MATTRECT-ICE:181688
In: Level 1
Type - Pset_ManufacturerTypeInformation - Manufacturer: REVIGRÉS
Type - Pset_ProductRequirements - Category: Wall Sweeps
Type - IFC.REVIGRÉS-Dados gerais-Wall Sweeps - Nome: REVIGRÉS-OMNISTONE-RB-8X90-MATT RECT-ICE; TipoProduto: Prensado a seco: grupo BIa UGL | Grés porcelânico técnico; NumeroDeRegistoDAP: EPD-REV-20240006-CCC1-EN; ReferenciaDAP: -; UrlDOP: -
Type - IFC.REVIGRÉS-Dados do fabricante-Wall Sweeps - FabricanteURL: https://www.revigres.pt/; ReferenciaModelo: Omnistone; Acabamento: MATT RECT; IdentificadorDoOperadorEconomico: 501840856; UrlFabricanteArtigo: https://www.revigres.pt/colecoes/omnistone; PaisOrigem: Portugal
Type - IFC.REVIGRÉS-Dados de desempenho-Wall Sweeps - Rectilinearidade: ± 0.2% máx.± 0.8 mm; Ortogonalidade: ± 0.2% máx.± 1.5 mm; PlanaridadeDaSuperficie: ± 0.3% máx. ± 1.8 mm; AbsorcaoDeAgua: < 0.05%; ModuloDeRuptura: > 45 N/mm130; ResistenciaAFlexao: ≥ 3500 N; ResistenciaAAbrasaoProfunda: < 120 mm131; DilatacaoTermicaLinear: ≤ 8,0x10-6 °C-1; ResistenciaAoChoqueTermico: Resiste; DurabilidadeResistenciaAoGeloDegelo: Resiste; ResistenciaAoEscorregamentoDIN51130: R10; ResistenciaAoEscorregamentoDIN51097: B; ResistenciaAoEscorregamentoENV51097: B; ResistenciaAoDeslizamentoENV12633: Class 2; ResistenciaAoEscorregamentoBS7976: >36; ResistenciaAoEscorregamentoANSIA1371: ≥0,42; ResistenciaAoEscorregamentoENV12633: Class 2; ResistenciaAoDeslizamentoBS7976: >36; ResistenciaAsManchas: Class 5; ResistenciaABaixasConcentracoesDeAcidosEAlcalis: Classe LA; ResistenciaAAltasConcentracoesDeAcidosEAlcalis: Classe HA; LibertacaoDeCadmio: 0; LibertacaoDeChumbo: 0
Type - IFC.REVIGRÉS-Dados de especificação-Wall Sweeps - VariacaoTonalidade: 3; NivelDeTrafego: 5; EPavimento: Não; ERevestimento: Sim; EExterno: Sim
Type - IFC.REVIGRÉS-Dados geométricos-Wall Sweeps - AlturaNominal: 10.5 mm; ComprimentoNominal: 8 mm; LarguraNominal: 88.9 mm
Type - IFC.REVIGRÉS-Dados de sustentabilidade-Wall Sweeps - ItemEParcialmenteReciclado: 0; PotencialPrivacaoDeAguaConsumoDeAguaPonderado: 4.5; EnergiaTermicaExportada: 0; ItemENovo: Sim; ItemEReciclado: Não; VidaÚtilEsperada: 50; SubstanciasPerigosas: Não; PotencialDeEsgotamentoAbioticoDosRecursosFosseis: 203; PotencialDeEsgotamentoAbioticoDosRecursosNaoFosseisMineraisEMetais: 0.000701; PotencialDeAquecimentoGlobalBiogenico: -0.48; CombustiveisFosseisComPotencialDeAquecimentoGlobal: 13.9; PotencialDeAquecimentoGlobalUsoDoSoloEMudancaDeUsoDoSolo: 0.0246; PotencialDeEutrofizacaoFraccaoDeNutrientesQueAtingemOCompartimentoFinalDeAguaDoce: 0.000189; PotencialDeEutrofizacaoFraccaoDeNutrientesQueAtingemOCompartimentoFinalMarinho: 0.0122; EnergiaRecuperada: 0.00739; ConsumoDeAguaDoce: 0.113; UtilizacaoLiquidaDeAguaDoce: 0.113; ResiduosPerigososEliminados: 0.00221; ResiduosNaoPerigososEliminados: 1.83; MassaTotalDeResiduosRadioactivosEliminados: 0.000394; EnergiaElectricaExportada: 1.55; MateriaisParaRecuperacaoDeEnergia: 0.00739; MateriaisParaReciclagem: 0.0253; UnidadeEPD: 1 m²
Pset_ProvisionForVoid - Shape: Undefined; Width: 1000 mm; Depth: 1000 mm
IFC.REVIGRÉS-Dados do fabricante-Wall Sweeps - Type: Wall Sweep: REVIGRÉS-OMNISTONE-RB-8X90-MATTRECT-ICE
IFC.REVIGRÉS-Dados de desempenho-Wall Sweeps - Type: Wall Sweep: REVIGRÉS-OMNISTONE-RB-8X90-MATTRECT-ICE
IFC.REVIGRÉS-Dados de especificação-Wall Sweeps - Type: Wall Sweep: REVIGRÉS-OMNISTONE-RB-8X90-MATTRECT-ICE
IFC.REVIGRÉS-Dados geométricos-Wall Sweeps - Type: Wall Sweep: REVIGRÉS-OMNISTONE-RB-8X90-MATTRECT-ICE
IFC.REVIGRÉS-Dados de sustentabilidade-Wall Sweeps - Type: Wall Sweep: REVIGRÉS-OMNISTONE-RB-8X90-MATTRECT-ICE

# IfcBuildingElementProxy: Wall Sweep:REVIGRÉS-OMNISTONE-RB-8X90-MATTRECT-IRON, Wall Sweep:REVIGRÉS-OMNISTONE-RB-8X90-MATTRECT-IRON:181700
In: Level 1
Type - Pset_ManufacturerTypeInformation - Manufacturer: REVIGRÉS
Type - Pset_ProductRequirements - Category: Wall Sweeps
Type - IFC.REVIGRÉS-Dados gerais-Wall Sweeps - Nome: REVIGRÉS-OMNISTONE-RB-8X90-MATT RECT-IRON; TipoProduto: Prensado a seco: grupo BIa UGL | Grés porcelânico técnico; NumeroDeRegistoDAP: EPD-REV-20240006-CCC1-EN; ReferenciaDAP: -; UrlDOP: -
Type - IFC.REVIGRÉS-Dados do fabricante-Wall Sweeps - FabricanteURL: https://www.revigres.pt/; ReferenciaModelo: Omnistone; Acabamento: MATT RECT; IdentificadorDoOperadorEconomico: 501840856; UrlFabricanteArtigo: https://www.revigres.pt/colecoes/omnistone; PaisOrigem: Portugal
Type - IFC.REVIGRÉS-Dados de desempenho-Wall Sweeps - Rectilinearidade: ± 0.2% máx.± 0.8 mm; Ortogonalidade: ± 0.2% máx.± 1.5 mm; PlanaridadeDaSuperficie: ± 0.3% máx. ± 1.8 mm; AbsorcaoDeAgua: < 0.05%; ModuloDeRuptura: > 45 N/mm130; ResistenciaAFlexao: ≥ 3500 N; ResistenciaAAbrasaoProfunda: < 120 mm131; DilatacaoTermicaLinear: ≤ 8,0x10-6 °C-1; ResistenciaAoChoqueTermico: Resiste; DurabilidadeResistenciaAoGeloDegelo: Resiste; ResistenciaAoEscorregamentoDIN51130: R10; ResistenciaAoEscorregamentoDIN51097: B; ResistenciaAoEscorregamentoENV51097: B; ResistenciaAoDeslizamentoENV12633: Class 2; ResistenciaAoEscorregamentoBS7976: >36; ResistenciaAoEscorregamentoANSIA1371: ≥0,42; ResistenciaAoEscorregamentoENV12633: Class 2; ResistenciaAoDeslizamentoBS7976: >36; ResistenciaAsManchas: Class 5; ResistenciaABaixasConcentracoesDeAcidosEAlcalis: Classe LA; ResistenciaAAltasConcentracoesDeAcidosEAlcalis: Classe HA; LibertacaoDeCadmio: 0; LibertacaoDeChumbo: 0
Type - IFC.REVIGRÉS-Dados de especificação-Wall Sweeps - VariacaoTonalidade: 3; NivelDeTrafego: 5; EPavimento: Não; ERevestimento: Sim; EExterno: Sim
Type - IFC.REVIGRÉS-Dados geométricos-Wall Sweeps - AlturaNominal: 10.5 mm; ComprimentoNominal: 8 mm; LarguraNominal: 88.9 mm
Type - IFC.REVIGRÉS-Dados de sustentabilidade-Wall Sweeps - PotencialPrivacaoDeAguaConsumoDeAguaPonderado: 4.5; EnergiaTermicaExportada: 0; ItemENovo: Sim; ItemEParcialmenteReciclado: 0.14; ItemEReciclado: Sim; VidaÚtilEsperada: 50; SubstanciasPerigosas: Não; PotencialDeEsgotamentoAbioticoDosRecursosFosseis: 203; PotencialDeEsgotamentoAbioticoDosRecursosNaoFosseisMineraisEMetais: 0.000701; PotencialDeAquecimentoGlobalBiogenico: -0.48; CombustiveisFosseisComPotencialDeAquecimentoGlobal: 13.9; PotencialDeAquecimentoGlobalUsoDoSoloEMudancaDeUsoDoSolo: 0.0246; PotencialDeEutrofizacaoFraccaoDeNutrientesQueAtingemOCompartimentoFinalDeAguaDoce: 0.000189; PotencialDeEutrofizacaoFraccaoDeNutrientesQueAtingemOCompartimentoFinalMarinho: 0.0122; EnergiaRecuperada: 0.00739; ConsumoDeAguaDoce: 0.113; UtilizacaoLiquidaDeAguaDoce: 0.113; ResiduosPerigososEliminados: 0.00221; ResiduosNaoPerigososEliminados: 1.83; MassaTotalDeResiduosRadioactivosEliminados: 0.000394; EnergiaElectricaExportada: 1.55; MateriaisParaRecuperacaoDeEnergia: 0.00739; MateriaisParaReciclagem: 0.0253; UnidadeEPD: 1 m²
Pset_ProvisionForVoid - Shape: Undefined; Width: 1000 mm; Depth: 1000 mm
IFC.REVIGRÉS-Dados do fabricante-Wall Sweeps - Type: Wall Sweep: REVIGRÉS-OMNISTONE-RB-8X90-MATTRECT-IRON
IFC.REVIGRÉS-Dados de desempenho-Wall Sweeps - Type: Wall Sweep: REVIGRÉS-OMNISTONE-RB-8X90-MATTRECT-IRON
IFC.REVIGRÉS-Dados de especificação-Wall Sweeps - Type: Wall Sweep: REVIGRÉS-OMNISTONE-RB-8X90-MATTRECT-IRON
IFC.REVIGRÉS-Dados geométricos-Wall Sweeps - Type: Wall Sweep: REVIGRÉS-OMNISTONE-RB-8X90-MATTRECT-IRON
IFC.REVIGRÉS-Dados de sustentabilidade-Wall Sweeps - Type: Wall Sweep: REVIGRÉS-OMNISTONE-RB-8X90-MATTRECT-IRON

# IfcBuildingElementProxy: Wall Sweep:REVIGRÉS-OMNISTONE-RB-8X90-MATTRECT-JET, Wall Sweep:REVIGRÉS-OMNISTONE-RB-8X90-MATTRECT-JET:181712
In: Level 1
Type - Pset_ManufacturerTypeInformation - Manufacturer: REVIGRÉS
Type - Pset_ProductRequirements - Category: Wall Sweeps
Type - IFC.REVIGRÉS-Dados gerais-Wall Sweeps - Nome: REVIGRÉS-OMNISTONE-RB-8X90-MATT RECT-JET; TipoProduto: Prensado a seco: grupo BIa UGL | Grés porcelânico técnico; NumeroDeRegistoDAP: EPD-REV-20240006-CCC1-EN; ReferenciaDAP: -; UrlDOP: -
Type - IFC.REVIGRÉS-Dados do fabricante-Wall Sweeps - FabricanteURL: https://www.revigres.pt/; ReferenciaModelo: Omnistone; Acabamento: MATT RECT; IdentificadorDoOperadorEconomico: 501840856; UrlFabricanteArtigo: https://www.revigres.pt/colecoes/omnistone; PaisOrigem: Portugal
Type - IFC.REVIGRÉS-Dados de desempenho-Wall Sweeps - Rectilinearidade: ± 0.2% máx.± 0.8 mm; Ortogonalidade: ± 0.2% máx.± 1.5 mm; PlanaridadeDaSuperficie: ± 0.3% máx. ± 1.8 mm; AbsorcaoDeAgua: < 0.05%; ModuloDeRuptura: > 45 N/mm130; ResistenciaAFlexao: ≥ 3500 N; ResistenciaAAbrasaoProfunda: < 120 mm131; DilatacaoTermicaLinear: ≤ 8,0x10-6 °C-1; ResistenciaAoChoqueTermico: Resiste; DurabilidadeResistenciaAoGeloDegelo: Resiste; ResistenciaAoEscorregamentoDIN51130: R10; ResistenciaAoEscorregamentoDIN51097: B; ResistenciaAoEscorregamentoENV51097: B; ResistenciaAoDeslizamentoENV12633: Class 2; ResistenciaAoEscorregamentoBS7976: >36; ResistenciaAoEscorregamentoANSIA1371: ≥0,42; ResistenciaAoEscorregamentoENV12633: Class 2; ResistenciaAoDeslizamentoBS7976: >36; ResistenciaAsManchas: Class 5; ResistenciaABaixasConcentracoesDeAcidosEAlcalis: Classe LA; ResistenciaAAltasConcentracoesDeAcidosEAlcalis: Classe HA; LibertacaoDeCadmio: 0; LibertacaoDeChumbo: 0
Type - IFC.REVIGRÉS-Dados de especificação-Wall Sweeps - VariacaoTonalidade: 3; NivelDeTrafego: 5; EPavimento: Não; ERevestimento: Sim; EExterno: Sim
Type - IFC.REVIGRÉS-Dados geométricos-Wall Sweeps - AlturaNominal: 10.5 mm; ComprimentoNominal: 8 mm; LarguraNominal: 88.9 mm
Type - IFC.REVIGRÉS-Dados de sustentabilidade-Wall Sweeps - ItemEParcialmenteReciclado: 0; PotencialPrivacaoDeAguaConsumoDeAguaPonderado: 4.5; EnergiaTermicaExportada: 0; ItemENovo: Sim; ItemEReciclado: Não; VidaÚtilEsperada: 50; SubstanciasPerigosas: Não; PotencialDeEsgotamentoAbioticoDosRecursosFosseis: 203; PotencialDeEsgotamentoAbioticoDosRecursosNaoFosseisMineraisEMetais: 0.000701; PotencialDeAquecimentoGlobalBiogenico: -0.48; CombustiveisFosseisComPotencialDeAquecimentoGlobal: 13.9; PotencialDeAquecimentoGlobalUsoDoSoloEMudancaDeUsoDoSolo: 0.0246; PotencialDeEutrofizacaoFraccaoDeNutrientesQueAtingemOCompartimentoFinalDeAguaDoce: 0.000189; PotencialDeEutrofizacaoFraccaoDeNutrientesQueAtingemOCompartimentoFinalMarinho: 0.0122; EnergiaRecuperada: 0.00739; ConsumoDeAguaDoce: 0.113; UtilizacaoLiquidaDeAguaDoce: 0.113; ResiduosPerigososEliminados: 0.00221; ResiduosNaoPerigososEliminados: 1.83; MassaTotalDeResiduosRadioactivosEliminados: 0.000394; EnergiaElectricaExportada: 1.55; MateriaisParaRecuperacaoDeEnergia: 0.00739; MateriaisParaReciclagem: 0.0253; UnidadeEPD: 1 m²
Pset_ProvisionForVoid - Shape: Undefined; Width: 1000 mm; Depth: 1000 mm
IFC.REVIGRÉS-Dados do fabricante-Wall Sweeps - Type: Wall Sweep: REVIGRÉS-OMNISTONE-RB-8X90-MATTRECT-JET
IFC.REVIGRÉS-Dados de desempenho-Wall Sweeps - Type: Wall Sweep: REVIGRÉS-OMNISTONE-RB-8X90-MATTRECT-JET
IFC.REVIGRÉS-Dados de especificação-Wall Sweeps - Type: Wall Sweep: REVIGRÉS-OMNISTONE-RB-8X90-MATTRECT-JET
IFC.REVIGRÉS-Dados geométricos-Wall Sweeps - Type: Wall Sweep: REVIGRÉS-OMNISTONE-RB-8X90-MATTRECT-JET
IFC.REVIGRÉS-Dados de sustentabilidade-Wall Sweeps - Type: Wall Sweep: REVIGRÉS-OMNISTONE-RB-8X90-MATTRECT-JET

# IfcBuildingElementProxy: Wall Sweep:REVIGRÉS-OMNISTONE-RB-8X90-MATTRECT-PLATINA, Wall Sweep:REVIGRÉS-OMNISTONE-RB-8X90-MATTRECT-PLATINA:181724
In: Level 1
Type - Pset_ManufacturerTypeInformation - Manufacturer: REVIGRÉS
Type - Pset_ProductRequirements - Category: Wall Sweeps
Type - IFC.REVIGRÉS-Dados gerais-Wall Sweeps - Nome: REVIGRÉS-OMNISTONE-RB-8X90-MATT RECT-PLATINA; TipoProduto: Prensado a seco: grupo BIa UGL | Grés porcelânico técnico; NumeroDeRegistoDAP: EPD-REV-20240006-CCC1-EN; ReferenciaDAP: -; UrlDOP: -
Type - IFC.REVIGRÉS-Dados do fabricante-Wall Sweeps - FabricanteURL: https://www.revigres.pt/; ReferenciaModelo: Omnistone; Acabamento: MATT RECT; IdentificadorDoOperadorEconomico: 501840856; UrlFabricanteArtigo: https://www.revigres.pt/colecoes/omnistone; PaisOrigem: Portugal
Type - IFC.REVIGRÉS-Dados de desempenho-Wall Sweeps - Rectilinearidade: ± 0.2% máx.± 0.8 mm; Ortogonalidade: ± 0.2% máx.± 1.5 mm; PlanaridadeDaSuperficie: ± 0.3% máx. ± 1.8 mm; AbsorcaoDeAgua: < 0.05%; ModuloDeRuptura: > 45 N/mm130; ResistenciaAFlexao: ≥ 3500 N; ResistenciaAAbrasaoProfunda: < 120 mm131; DilatacaoTermicaLinear: ≤ 8,0x10-6 °C-1; ResistenciaAoChoqueTermico: Resiste; DurabilidadeResistenciaAoGeloDegelo: Resiste; ResistenciaAoEscorregamentoDIN51130: R10; ResistenciaAoEscorregamentoDIN51097: B; ResistenciaAoEscorregamentoENV51097: B; ResistenciaAoDeslizamentoENV12633: Class 2; ResistenciaAoEscorregamentoBS7976: >36; ResistenciaAoEscorregamentoANSIA1371: ≥0,42; ResistenciaAoEscorregamentoENV12633: Class 2; ResistenciaAoDeslizamentoBS7976: >36; ResistenciaAsManchas: Class 5; ResistenciaABaixasConcentracoesDeAcidosEAlcalis: Classe LA; ResistenciaAAltasConcentracoesDeAcidosEAlcalis: Classe HA; LibertacaoDeCadmio: 0; LibertacaoDeChumbo: 0
Type - IFC.REVIGRÉS-Dados de especificação-Wall Sweeps - VariacaoTonalidade: 3; NivelDeTrafego: 5; EPavimento: Não; ERevestimento: Sim; EExterno: Sim
Type - IFC.REVIGRÉS-Dados geométricos-Wall Sweeps - AlturaNominal: 10.5 mm; ComprimentoNominal: 8 mm; LarguraNominal: 88.9 mm
Type - IFC.REVIGRÉS-Dados de sustentabilidade-Wall Sweeps - ItemEParcialmenteReciclado: 0; PotencialPrivacaoDeAguaConsumoDeAguaPonderado: 4.5; EnergiaTermicaExportada: 0; ItemENovo: Sim; ItemEReciclado: Não; VidaÚtilEsperada: 50; SubstanciasPerigosas: Não; PotencialDeEsgotamentoAbioticoDosRecursosFosseis: 203; PotencialDeEsgotamentoAbioticoDosRecursosNaoFosseisMineraisEMetais: 0.000701; PotencialDeAquecimentoGlobalBiogenico: -0.48; CombustiveisFosseisComPotencialDeAquecimentoGlobal: 13.9; PotencialDeAquecimentoGlobalUsoDoSoloEMudancaDeUsoDoSolo: 0.0246; PotencialDeEutrofizacaoFraccaoDeNutrientesQueAtingemOCompartimentoFinalDeAguaDoce: 0.000189; PotencialDeEutrofizacaoFraccaoDeNutrientesQueAtingemOCompartimentoFinalMarinho: 0.0122; EnergiaRecuperada: 0.00739; ConsumoDeAguaDoce: 0.113; UtilizacaoLiquidaDeAguaDoce: 0.113; ResiduosPerigososEliminados: 0.00221; ResiduosNaoPerigososEliminados: 1.83; MassaTotalDeResiduosRadioactivosEliminados: 0.000394; EnergiaElectricaExportada: 1.55; MateriaisParaRecuperacaoDeEnergia: 0.00739; MateriaisParaReciclagem: 0.0253; UnidadeEPD: 1 m²
Pset_ProvisionForVoid - Shape: Undefined; Width: 1000 mm; Depth: 1000 mm
IFC.REVIGRÉS-Dados do fabricante-Wall Sweeps - Type: Wall Sweep: REVIGRÉS-OMNISTONE-RB-8X90-MATTRECT-PLATINA
IFC.REVIGRÉS-Dados de desempenho-Wall Sweeps - Type: Wall Sweep: REVIGRÉS-OMNISTONE-RB-8X90-MATTRECT-PLATINA
IFC.REVIGRÉS-Dados de especificação-Wall Sweeps - Type: Wall Sweep: REVIGRÉS-OMNISTONE-RB-8X90-MATTRECT-PLATINA
IFC.REVIGRÉS-Dados geométricos-Wall Sweeps - Type: Wall Sweep: REVIGRÉS-OMNISTONE-RB-8X90-MATTRECT-PLATINA
IFC.REVIGRÉS-Dados de sustentabilidade-Wall Sweeps - Type: Wall Sweep: REVIGRÉS-OMNISTONE-RB-8X90-MATTRECT-PLATINA

# IfcBuildingElementProxy: Wall Sweep:REVIGRÉS-OMNISTONE-RB-8X90-MATTRECT-ROPE, Wall Sweep:REVIGRÉS-OMNISTONE-RB-8X90-MATTRECT-ROPE:181736
In: Level 1
Type - Pset_ManufacturerTypeInformation - Manufacturer: REVIGRÉS
Type - Pset_ProductRequirements - Category: Wall Sweeps
Type - IFC.REVIGRÉS-Dados gerais-Wall Sweeps - Nome: REVIGRÉS-OMNISTONE-RB-8X90-MATT RECT-ROPE; TipoProduto: Prensado a seco: grupo BIa UGL | Grés porcelânico técnico; NumeroDeRegistoDAP: EPD-REV-20240006-CCC1-EN; ReferenciaDAP: -; UrlDOP: -
Type - IFC.REVIGRÉS-Dados do fabricante-Wall Sweeps - FabricanteURL: https://www.revigres.pt/; ReferenciaModelo: Omnistone; Acabamento: MATT RECT; IdentificadorDoOperadorEconomico: 501840856; UrlFabricanteArtigo: https://www.revigres.pt/colecoes/omnistone; PaisOrigem: Portugal
Type - IFC.REVIGRÉS-Dados de desempenho-Wall Sweeps - Rectilinearidade: ± 0.2% máx.± 0.8 mm; Ortogonalidade: ± 0.2% máx.± 1.5 mm; PlanaridadeDaSuperficie: ± 0.3% máx. ± 1.8 mm; AbsorcaoDeAgua: < 0.05%; ModuloDeRuptura: > 45 N/mm130; ResistenciaAFlexao: ≥ 3500 N; ResistenciaAAbrasaoProfunda: < 120 mm131; DilatacaoTermicaLinear: ≤ 8,0x10-6 °C-1; ResistenciaAoChoqueTermico: Resiste; DurabilidadeResistenciaAoGeloDegelo: Resiste; ResistenciaAoEscorregamentoDIN51130: R10; ResistenciaAoEscorregamentoDIN51097: B; ResistenciaAoEscorregamentoENV51097: B; ResistenciaAoDeslizamentoENV12633: Class 2; ResistenciaAoEscorregamentoBS7976: >36; ResistenciaAoEscorregamentoANSIA1371: ≥0,42; ResistenciaAoEscorregamentoENV12633: Class 2; ResistenciaAoDeslizamentoBS7976: >36; ResistenciaAsManchas: Class 5; ResistenciaABaixasConcentracoesDeAcidosEAlcalis: Classe LA; ResistenciaAAltasConcentracoesDeAcidosEAlcalis: Classe HA; LibertacaoDeCadmio: 0; LibertacaoDeChumbo: 0
Type - IFC.REVIGRÉS-Dados de especificação-Wall Sweeps - VariacaoTonalidade: 3; NivelDeTrafego: 5; EPavimento: Não; ERevestimento: Sim; EExterno: Sim
Type - IFC.REVIGRÉS-Dados geométricos-Wall Sweeps - AlturaNominal: 10.5 mm; ComprimentoNominal: 8 mm; LarguraNominal: 88.9 mm
Type - IFC.REVIGRÉS-Dados de sustentabilidade-Wall Sweeps - ItemEParcialmenteReciclado: 0; PotencialPrivacaoDeAguaConsumoDeAguaPonderado: 4.5; EnergiaTermicaExportada: 0; ItemENovo: Sim; ItemEReciclado: Não; VidaÚtilEsperada: 50; SubstanciasPerigosas: Não; PotencialDeEsgotamentoAbioticoDosRecursosFosseis: 203; PotencialDeEsgotamentoAbioticoDosRecursosNaoFosseisMineraisEMetais: 0.000701; PotencialDeAquecimentoGlobalBiogenico: -0.48; CombustiveisFosseisComPotencialDeAquecimentoGlobal: 13.9; PotencialDeAquecimentoGlobalUsoDoSoloEMudancaDeUsoDoSolo: 0.0246; PotencialDeEutrofizacaoFraccaoDeNutrientesQueAtingemOCompartimentoFinalDeAguaDoce: 0.000189; PotencialDeEutrofizacaoFraccaoDeNutrientesQueAtingemOCompartimentoFinalMarinho: 0.0122; EnergiaRecuperada: 0.00739; ConsumoDeAguaDoce: 0.113; UtilizacaoLiquidaDeAguaDoce: 0.113; ResiduosPerigososEliminados: 0.00221; ResiduosNaoPerigososEliminados: 1.83; MassaTotalDeResiduosRadioactivosEliminados: 0.000394; EnergiaElectricaExportada: 1.55; MateriaisParaRecuperacaoDeEnergia: 0.00739; MateriaisParaReciclagem: 0.0253; UnidadeEPD: 1 m²
Pset_ProvisionForVoid - Shape: Undefined; Width: 1000 mm; Depth: 1000 mm
IFC.REVIGRÉS-Dados do fabricante-Wall Sweeps - Type: Wall Sweep: REVIGRÉS-OMNISTONE-RB-8X90-MATTRECT-ROPE
IFC.REVIGRÉS-Dados de desempenho-Wall Sweeps - Type: Wall Sweep: REVIGRÉS-OMNISTONE-RB-8X90-MATTRECT-ROPE
IFC.REVIGRÉS-Dados de especificação-Wall Sweeps - Type: Wall Sweep: REVIGRÉS-OMNISTONE-RB-8X90-MATTRECT-ROPE
IFC.REVIGRÉS-Dados geométricos-Wall Sweeps - Type: Wall Sweep: REVIGRÉS-OMNISTONE-RB-8X90-MATTRECT-ROPE
IFC.REVIGRÉS-Dados de sustentabilidade-Wall Sweeps - Type: Wall Sweep: REVIGRÉS-OMNISTONE-RB-8X90-MATTRECT-ROPE

# IfcBuildingElementProxy: Wall Sweep:REVIGRÉS-OMNISTONE-RB-8X90-SOFT-BONE, Wall Sweep:REVIGRÉS-OMNISTONE-RB-8X90-SOFT-BONE:181682
In: Level 1
Type - Pset_ManufacturerTypeInformation - Manufacturer: REVIGRÉS
Type - Pset_ProductRequirements - Category: Wall Sweeps
Type - IFC.REVIGRÉS-Dados gerais-Wall Sweeps - Nome: REVIGRÉS-OMNISTONE-RB-8X90-SOFT-BONE; TipoProduto: Prensado a seco: grupo BIa UGL | Grés porcelânico técnico; NumeroDeRegistoDAP: EPD-REV-20240006-CCC1-EN; ReferenciaDAP: -; UrlDOP: -
Type - IFC.REVIGRÉS-Dados do fabricante-Wall Sweeps - FabricanteURL: https://www.revigres.pt/; ReferenciaModelo: Omnistone; Acabamento: SOFT; IdentificadorDoOperadorEconomico: 501840856; UrlFabricanteArtigo: https://www.revigres.pt/colecoes/omnistone; PaisOrigem: Portugal
Type - IFC.REVIGRÉS-Dados de desempenho-Wall Sweeps - Rectilinearidade: ± 0.2% máx.± 0.8 mm; Ortogonalidade: ± 0.2% máx.± 1.5 mm; PlanaridadeDaSuperficie: ± 0.3% máx. ± 1.8 mm; AbsorcaoDeAgua: < 0.05%; ModuloDeRuptura: > 45 N/mm130; ResistenciaAFlexao: ≥ 3500 N; ResistenciaAAbrasaoProfunda: < 120 mm131; DilatacaoTermicaLinear: ≤ 8,0x10-6 °C-1; ResistenciaAoChoqueTermico: Resiste; DurabilidadeResistenciaAoGeloDegelo: Resiste; ResistenciaAsManchas: Class 5; ResistenciaABaixasConcentracoesDeAcidosEAlcalis: Classe LA; ResistenciaAAltasConcentracoesDeAcidosEAlcalis: Classe HA; LibertacaoDeCadmio: 0; LibertacaoDeChumbo: 0
Type - IFC.REVIGRÉS-Dados de especificação-Wall Sweeps - VariacaoTonalidade: 3; NivelDeTrafego: 5; EPavimento: Não; ERevestimento: Sim; EExterno: Sim
Type - IFC.REVIGRÉS-Dados geométricos-Wall Sweeps - AlturaNominal: 10.5 mm; ComprimentoNominal: 8 mm; LarguraNominal: 88.9 mm
Type - IFC.REVIGRÉS-Dados de sustentabilidade-Wall Sweeps - ItemEParcialmenteReciclado: 0; PotencialPrivacaoDeAguaConsumoDeAguaPonderado: 4.5; EnergiaTermicaExportada: 0; ItemENovo: Sim; ItemEReciclado: Não; VidaÚtilEsperada: 50; SubstanciasPerigosas: Não; PotencialDeEsgotamentoAbioticoDosRecursosFosseis: 203; PotencialDeEsgotamentoAbioticoDosRecursosNaoFosseisMineraisEMetais: 0.000701; PotencialDeAquecimentoGlobalBiogenico: -0.48; CombustiveisFosseisComPotencialDeAquecimentoGlobal: 13.9; PotencialDeAquecimentoGlobalUsoDoSoloEMudancaDeUsoDoSolo: 0.0246; PotencialDeEutrofizacaoFraccaoDeNutrientesQueAtingemOCompartimentoFinalDeAguaDoce: 0.000189; PotencialDeEutrofizacaoFraccaoDeNutrientesQueAtingemOCompartimentoFinalMarinho: 0.0122; EnergiaRecuperada: 0.00739; ConsumoDeAguaDoce: 0.113; UtilizacaoLiquidaDeAguaDoce: 0.113; ResiduosPerigososEliminados: 0.00221; ResiduosNaoPerigososEliminados: 1.83; MassaTotalDeResiduosRadioactivosEliminados: 0.000394; EnergiaElectricaExportada: 1.55; MateriaisParaRecuperacaoDeEnergia: 0.00739; MateriaisParaReciclagem: 0.0253; UnidadeEPD: 1 m²
Pset_ProvisionForVoid - Shape: Undefined; Width: 1000 mm; Depth: 1000 mm
IFC.REVIGRÉS-Dados do fabricante-Wall Sweeps - Type: Wall Sweep: REVIGRÉS-OMNISTONE-RB-8X90-SOFT-BONE
IFC.REVIGRÉS-Dados de desempenho-Wall Sweeps - Type: Wall Sweep: REVIGRÉS-OMNISTONE-RB-8X90-SOFT-BONE
IFC.REVIGRÉS-Dados de especificação-Wall Sweeps - Type: Wall Sweep: REVIGRÉS-OMNISTONE-RB-8X90-SOFT-BONE
IFC.REVIGRÉS-Dados geométricos-Wall Sweeps - Type: Wall Sweep: REVIGRÉS-OMNISTONE-RB-8X90-SOFT-BONE
IFC.REVIGRÉS-Dados de sustentabilidade-Wall Sweeps - Type: Wall Sweep: REVIGRÉS-OMNISTONE-RB-8X90-SOFT-BONE

# IfcBuildingElementProxy: Wall Sweep:REVIGRÉS-OMNISTONE-RB-8X90-SOFT-ICE, Wall Sweep:REVIGRÉS-OMNISTONE-RB-8X90-SOFT-ICE:181694
In: Level 1
Type - Pset_ManufacturerTypeInformation - Manufacturer: REVIGRÉS
Type - Pset_ProductRequirements - Category: Wall Sweeps
Type - IFC.REVIGRÉS-Dados gerais-Wall Sweeps - Nome: REVIGRÉS-OMNISTONE-RB-8X90-SOFT-ICE; TipoProduto: Prensado a seco: grupo BIa UGL | Grés porcelânico técnico; NumeroDeRegistoDAP: EPD-REV-20240006-CCC1-EN; ReferenciaDAP: -; UrlDOP: -
Type - IFC.REVIGRÉS-Dados do fabricante-Wall Sweeps - FabricanteURL: https://www.revigres.pt/; ReferenciaModelo: Omnistone; Acabamento: SOFT; IdentificadorDoOperadorEconomico: 501840856; UrlFabricanteArtigo: https://www.revigres.pt/colecoes/omnistone; PaisOrigem: Portugal
Type - IFC.REVIGRÉS-Dados de desempenho-Wall Sweeps - Rectilinearidade: ± 0.2% máx.± 0.8 mm; Ortogonalidade: ± 0.2% máx.± 1.5 mm; PlanaridadeDaSuperficie: ± 0.3% máx. ± 1.8 mm; AbsorcaoDeAgua: < 0.05%; ModuloDeRuptura: > 45 N/mm130; ResistenciaAFlexao: ≥ 3500 N; ResistenciaAAbrasaoProfunda: < 120 mm131; DilatacaoTermicaLinear: ≤ 8,0x10-6 °C-1; ResistenciaAoChoqueTermico: Resiste; DurabilidadeResistenciaAoGeloDegelo: Resiste; ResistenciaAsManchas: Class 5; ResistenciaABaixasConcentracoesDeAcidosEAlcalis: Classe LA; ResistenciaAAltasConcentracoesDeAcidosEAlcalis: Classe HA; LibertacaoDeCadmio: 0; LibertacaoDeChumbo: 0
Type - IFC.REVIGRÉS-Dados de especificação-Wall Sweeps - VariacaoTonalidade: 3; NivelDeTrafego: 5; EPavimento: Não; ERevestimento: Sim; EExterno: Sim
Type - IFC.REVIGRÉS-Dados geométricos-Wall Sweeps - AlturaNominal: 10.5 mm; ComprimentoNominal: 8 mm; LarguraNominal: 88.9 mm
Type - IFC.REVIGRÉS-Dados de sustentabilidade-Wall Sweeps - ItemEParcialmenteReciclado: 0; PotencialPrivacaoDeAguaConsumoDeAguaPonderado: 4.5; EnergiaTermicaExportada: 0; ItemENovo: Sim; ItemEReciclado: Não; VidaÚtilEsperada: 50; SubstanciasPerigosas: Não; PotencialDeEsgotamentoAbioticoDosRecursosFosseis: 203; PotencialDeEsgotamentoAbioticoDosRecursosNaoFosseisMineraisEMetais: 0.000701; PotencialDeAquecimentoGlobalBiogenico: -0.48; CombustiveisFosseisComPotencialDeAquecimentoGlobal: 13.9; PotencialDeAquecimentoGlobalUsoDoSoloEMudancaDeUsoDoSolo: 0.0246; PotencialDeEutrofizacaoFraccaoDeNutrientesQueAtingemOCompartimentoFinalDeAguaDoce: 0.000189; PotencialDeEutrofizacaoFraccaoDeNutrientesQueAtingemOCompartimentoFinalMarinho: 0.0122; EnergiaRecuperada: 0.00739; ConsumoDeAguaDoce: 0.113; UtilizacaoLiquidaDeAguaDoce: 0.113; ResiduosPerigososEliminados: 0.00221; ResiduosNaoPerigososEliminados: 1.83; MassaTotalDeResiduosRadioactivosEliminados: 0.000394; EnergiaElectricaExportada: 1.55; MateriaisParaRecuperacaoDeEnergia: 0.00739; MateriaisParaReciclagem: 0.0253; UnidadeEPD: 1 m²
Pset_ProvisionForVoid - Shape: Undefined; Width: 1000 mm; Depth: 1000 mm
IFC.REVIGRÉS-Dados do fabricante-Wall Sweeps - Type: Wall Sweep: REVIGRÉS-OMNISTONE-RB-8X90-SOFT-ICE
IFC.REVIGRÉS-Dados de desempenho-Wall Sweeps - Type: Wall Sweep: REVIGRÉS-OMNISTONE-RB-8X90-SOFT-ICE
IFC.REVIGRÉS-Dados de especificação-Wall Sweeps - Type: Wall Sweep: REVIGRÉS-OMNISTONE-RB-8X90-SOFT-ICE
IFC.REVIGRÉS-Dados geométricos-Wall Sweeps - Type: Wall Sweep: REVIGRÉS-OMNISTONE-RB-8X90-SOFT-ICE
IFC.REVIGRÉS-Dados de sustentabilidade-Wall Sweeps - Type: Wall Sweep: REVIGRÉS-OMNISTONE-RB-8X90-SOFT-ICE

# IfcBuildingElementProxy: Wall Sweep:REVIGRÉS-OMNISTONE-RB-8X90-SOFT-IRON, Wall Sweep:REVIGRÉS-OMNISTONE-RB-8X90-SOFT-IRON:181706
In: Level 1
Type - Pset_ManufacturerTypeInformation - Manufacturer: REVIGRÉS
Type - Pset_ProductRequirements - Category: Wall Sweeps
Type - IFC.REVIGRÉS-Dados gerais-Wall Sweeps - Nome: REVIGRÉS-OMNISTONE-RB-8X90-SOFT-IRON; TipoProduto: Prensado a seco: grupo BIa UGL | Grés porcelânico técnico; NumeroDeRegistoDAP: EPD-REV-20240006-CCC1-EN; ReferenciaDAP: -; UrlDOP: -
Type - IFC.REVIGRÉS-Dados do fabricante-Wall Sweeps - FabricanteURL: https://www.revigres.pt/; ReferenciaModelo: Omnistone; Acabamento: SOFT; IdentificadorDoOperadorEconomico: 501840856; UrlFabricanteArtigo: https://www.revigres.pt/colecoes/omnistone; PaisOrigem: Portugal
Type - IFC.REVIGRÉS-Dados de desempenho-Wall Sweeps - Rectilinearidade: ± 0.2% máx.± 0.8 mm; Ortogonalidade: ± 0.2% máx.± 1.5 mm; PlanaridadeDaSuperficie: ± 0.3% máx. ± 1.8 mm; AbsorcaoDeAgua: < 0.05%; ModuloDeRuptura: > 45 N/mm130; ResistenciaAFlexao: ≥ 3500 N; ResistenciaAAbrasaoProfunda: < 120 mm131; DilatacaoTermicaLinear: ≤ 8,0x10-6 °C-1; ResistenciaAoChoqueTermico: Resiste; DurabilidadeResistenciaAoGeloDegelo: Resiste; ResistenciaAsManchas: Class 5; ResistenciaABaixasConcentracoesDeAcidosEAlcalis: Classe LA; ResistenciaAAltasConcentracoesDeAcidosEAlcalis: Classe HA; LibertacaoDeCadmio: 0; LibertacaoDeChumbo: 0
Type - IFC.REVIGRÉS-Dados de especificação-Wall Sweeps - VariacaoTonalidade: 3; NivelDeTrafego: 5; EPavimento: Não; ERevestimento: Sim; EExterno: Sim
Type - IFC.REVIGRÉS-Dados geométricos-Wall Sweeps - AlturaNominal: 10.5 mm; ComprimentoNominal: 8 mm; LarguraNominal: 88.9 mm
Type - IFC.REVIGRÉS-Dados de sustentabilidade-Wall Sweeps - PotencialPrivacaoDeAguaConsumoDeAguaPonderado: 4.5; EnergiaTermicaExportada: 0; ItemENovo: Sim; ItemEParcialmenteReciclado: 0.14; ItemEReciclado: Sim; VidaÚtilEsperada: 50; SubstanciasPerigosas: Não; PotencialDeEsgotamentoAbioticoDosRecursosFosseis: 203; PotencialDeEsgotamentoAbioticoDosRecursosNaoFosseisMineraisEMetais: 0.000701; PotencialDeAquecimentoGlobalBiogenico: -0.48; CombustiveisFosseisComPotencialDeAquecimentoGlobal: 13.9; PotencialDeAquecimentoGlobalUsoDoSoloEMudancaDeUsoDoSolo: 0.0246; PotencialDeEutrofizacaoFraccaoDeNutrientesQueAtingemOCompartimentoFinalDeAguaDoce: 0.000189; PotencialDeEutrofizacaoFraccaoDeNutrientesQueAtingemOCompartimentoFinalMarinho: 0.0122; EnergiaRecuperada: 0.00739; ConsumoDeAguaDoce: 0.113; UtilizacaoLiquidaDeAguaDoce: 0.113; ResiduosPerigososEliminados: 0.00221; ResiduosNaoPerigososEliminados: 1.83; MassaTotalDeResiduosRadioactivosEliminados: 0.000394; EnergiaElectricaExportada: 1.55; MateriaisParaRecuperacaoDeEnergia: 0.00739; MateriaisParaReciclagem: 0.0253; UnidadeEPD: 1 m²
Pset_ProvisionForVoid - Shape: Undefined; Width: 1000 mm; Depth: 1000 mm
IFC.REVIGRÉS-Dados do fabricante-Wall Sweeps - Type: Wall Sweep: REVIGRÉS-OMNISTONE-RB-8X90-SOFT-IRON
IFC.REVIGRÉS-Dados de desempenho-Wall Sweeps - Type: Wall Sweep: REVIGRÉS-OMNISTONE-RB-8X90-SOFT-IRON
IFC.REVIGRÉS-Dados de especificação-Wall Sweeps - Type: Wall Sweep: REVIGRÉS-OMNISTONE-RB-8X90-SOFT-IRON
IFC.REVIGRÉS-Dados geométricos-Wall Sweeps - Type: Wall Sweep: REVIGRÉS-OMNISTONE-RB-8X90-SOFT-IRON
IFC.REVIGRÉS-Dados de sustentabilidade-Wall Sweeps - Type: Wall Sweep: REVIGRÉS-OMNISTONE-RB-8X90-SOFT-IRON

# IfcBuildingElementProxy: Wall Sweep:REVIGRÉS-OMNISTONE-RB-8X90-SOFT-JET, Wall Sweep:REVIGRÉS-OMNISTONE-RB-8X90-SOFT-JET:181718
In: Level 1
Type - Pset_ManufacturerTypeInformation - Manufacturer: REVIGRÉS
Type - Pset_ProductRequirements - Category: Wall Sweeps
Type - IFC.REVIGRÉS-Dados gerais-Wall Sweeps - Nome: REVIGRÉS-OMNISTONE-RB-8X90-SOFT-JET; TipoProduto: Prensado a seco: grupo BIa UGL | Grés porcelânico técnico; NumeroDeRegistoDAP: EPD-REV-20240006-CCC1-EN; ReferenciaDAP: -; UrlDOP: -
Type - IFC.REVIGRÉS-Dados do fabricante-Wall Sweeps - FabricanteURL: https://www.revigres.pt/; ReferenciaModelo: Omnistone; Acabamento: SOFT; IdentificadorDoOperadorEconomico: 501840856; UrlFabricanteArtigo: https://www.revigres.pt/colecoes/omnistone; PaisOrigem: Portugal
Type - IFC.REVIGRÉS-Dados de desempenho-Wall Sweeps - Rectilinearidade: ± 0.2% máx.± 0.8 mm; Ortogonalidade: ± 0.2% máx.± 1.5 mm; PlanaridadeDaSuperficie: ± 0.3% máx. ± 1.8 mm; AbsorcaoDeAgua: < 0.05%; ModuloDeRuptura: > 45 N/mm130; ResistenciaAFlexao: ≥ 3500 N; ResistenciaAAbrasaoProfunda: < 120 mm131; DilatacaoTermicaLinear: ≤ 8,0x10-6 °C-1; ResistenciaAoChoqueTermico: Resiste; DurabilidadeResistenciaAoGeloDegelo: Resiste; ResistenciaAsManchas: Class 5; ResistenciaABaixasConcentracoesDeAcidosEAlcalis: Classe LA; ResistenciaAAltasConcentracoesDeAcidosEAlcalis: Classe HA; LibertacaoDeCadmio: 0; LibertacaoDeChumbo: 0
Type - IFC.REVIGRÉS-Dados de especificação-Wall Sweeps - VariacaoTonalidade: 3; NivelDeTrafego: 5; EPavimento: Não; ERevestimento: Sim; EExterno: Sim
Type - IFC.REVIGRÉS-Dados geométricos-Wall Sweeps - AlturaNominal: 10.5 mm; ComprimentoNominal: 8 mm; LarguraNominal: 88.9 mm
Type - IFC.REVIGRÉS-Dados de sustentabilidade-Wall Sweeps - ItemEParcialmenteReciclado: 0; PotencialPrivacaoDeAguaConsumoDeAguaPonderado: 4.5; EnergiaTermicaExportada: 0; ItemENovo: Sim; ItemEReciclado: Não; VidaÚtilEsperada: 50; SubstanciasPerigosas: Não; PotencialDeEsgotamentoAbioticoDosRecursosFosseis: 203; PotencialDeEsgotamentoAbioticoDosRecursosNaoFosseisMineraisEMetais: 0.000701; PotencialDeAquecimentoGlobalBiogenico: -0.48; CombustiveisFosseisComPotencialDeAquecimentoGlobal: 13.9; PotencialDeAquecimentoGlobalUsoDoSoloEMudancaDeUsoDoSolo: 0.0246; PotencialDeEutrofizacaoFraccaoDeNutrientesQueAtingemOCompartimentoFinalDeAguaDoce: 0.000189; PotencialDeEutrofizacaoFraccaoDeNutrientesQueAtingemOCompartimentoFinalMarinho: 0.0122; EnergiaRecuperada: 0.00739; ConsumoDeAguaDoce: 0.113; UtilizacaoLiquidaDeAguaDoce: 0.113; ResiduosPerigososEliminados: 0.00221; ResiduosNaoPerigososEliminados: 1.83; MassaTotalDeResiduosRadioactivosEliminados: 0.000394; EnergiaElectricaExportada: 1.55; MateriaisParaRecuperacaoDeEnergia: 0.00739; MateriaisParaReciclagem: 0.0253; UnidadeEPD: 1 m²
Pset_ProvisionForVoid - Shape: Undefined; Width: 1000 mm; Depth: 1000 mm
IFC.REVIGRÉS-Dados do fabricante-Wall Sweeps - Type: Wall Sweep: REVIGRÉS-OMNISTONE-RB-8X90-SOFT-JET
IFC.REVIGRÉS-Dados de desempenho-Wall Sweeps - Type: Wall Sweep: REVIGRÉS-OMNISTONE-RB-8X90-SOFT-JET
IFC.REVIGRÉS-Dados de especificação-Wall Sweeps - Type: Wall Sweep: REVIGRÉS-OMNISTONE-RB-8X90-SOFT-JET
IFC.REVIGRÉS-Dados geométricos-Wall Sweeps - Type: Wall Sweep: REVIGRÉS-OMNISTONE-RB-8X90-SOFT-JET
IFC.REVIGRÉS-Dados de sustentabilidade-Wall Sweeps - Type: Wall Sweep: REVIGRÉS-OMNISTONE-RB-8X90-SOFT-JET

# IfcBuildingElementProxy: Wall Sweep:REVIGRÉS-OMNISTONE-RB-8X90-SOFT-PLATINA, Wall Sweep:REVIGRÉS-OMNISTONE-RB-8X90-SOFT-PLATINA:181730
In: Level 1
Type - Pset_ManufacturerTypeInformation - Manufacturer: REVIGRÉS
Type - Pset_ProductRequirements - Category: Wall Sweeps
Type - IFC.REVIGRÉS-Dados gerais-Wall Sweeps - Nome: REVIGRÉS-OMNISTONE-RB-8X90-SOFT-PLATINA; TipoProduto: Prensado a seco: grupo BIa UGL | Grés porcelânico técnico; NumeroDeRegistoDAP: EPD-REV-20240006-CCC1-EN; ReferenciaDAP: -; UrlDOP: -
Type - IFC.REVIGRÉS-Dados do fabricante-Wall Sweeps - FabricanteURL: https://www.revigres.pt/; ReferenciaModelo: Omnistone; Acabamento: SOFT; IdentificadorDoOperadorEconomico: 501840856; UrlFabricanteArtigo: https://www.revigres.pt/colecoes/omnistone; PaisOrigem: Portugal
Type - IFC.REVIGRÉS-Dados de desempenho-Wall Sweeps - Rectilinearidade: ± 0.2% máx.± 0.8 mm; Ortogonalidade: ± 0.2% máx.± 1.5 mm; PlanaridadeDaSuperficie: ± 0.3% máx. ± 1.8 mm; AbsorcaoDeAgua: < 0.05%; ModuloDeRuptura: > 45 N/mm130; ResistenciaAFlexao: ≥ 3500 N; ResistenciaAAbrasaoProfunda: < 120 mm131; DilatacaoTermicaLinear: ≤ 8,0x10-6 °C-1; ResistenciaAoChoqueTermico: Resiste; DurabilidadeResistenciaAoGeloDegelo: Resiste; ResistenciaAsManchas: Class 5; ResistenciaABaixasConcentracoesDeAcidosEAlcalis: Classe LA; ResistenciaAAltasConcentracoesDeAcidosEAlcalis: Classe HA; LibertacaoDeCadmio: 0; LibertacaoDeChumbo: 0
Type - IFC.REVIGRÉS-Dados de especificação-Wall Sweeps - VariacaoTonalidade: 3; NivelDeTrafego: 5; EPavimento: Não; ERevestimento: Sim; EExterno: Sim
Type - IFC.REVIGRÉS-Dados geométricos-Wall Sweeps - AlturaNominal: 10.5 mm; ComprimentoNominal: 8 mm; LarguraNominal: 88.9 mm
Type - IFC.REVIGRÉS-Dados de sustentabilidade-Wall Sweeps - ItemEParcialmenteReciclado: 0; PotencialPrivacaoDeAguaConsumoDeAguaPonderado: 4.5; EnergiaTermicaExportada: 0; ItemENovo: Sim; ItemEReciclado: Não; VidaÚtilEsperada: 50; SubstanciasPerigosas: Não; PotencialDeEsgotamentoAbioticoDosRecursosFosseis: 203; PotencialDeEsgotamentoAbioticoDosRecursosNaoFosseisMineraisEMetais: 0.000701; PotencialDeAquecimentoGlobalBiogenico: -0.48; CombustiveisFosseisComPotencialDeAquecimentoGlobal: 13.9; PotencialDeAquecimentoGlobalUsoDoSoloEMudancaDeUsoDoSolo: 0.0246; PotencialDeEutrofizacaoFraccaoDeNutrientesQueAtingemOCompartimentoFinalDeAguaDoce: 0.000189; PotencialDeEutrofizacaoFraccaoDeNutrientesQueAtingemOCompartimentoFinalMarinho: 0.0122; EnergiaRecuperada: 0.00739; ConsumoDeAguaDoce: 0.113; UtilizacaoLiquidaDeAguaDoce: 0.113; ResiduosPerigososEliminados: 0.00221; ResiduosNaoPerigososEliminados: 1.83; MassaTotalDeResiduosRadioactivosEliminados: 0.000394; EnergiaElectricaExportada: 1.55; MateriaisParaRecuperacaoDeEnergia: 0.00739; MateriaisParaReciclagem: 0.0253; UnidadeEPD: 1 m²
Pset_ProvisionForVoid - Shape: Undefined; Width: 1000 mm; Depth: 1000 mm
IFC.REVIGRÉS-Dados do fabricante-Wall Sweeps - Type: Wall Sweep: REVIGRÉS-OMNISTONE-RB-8X90-SOFT-PLATINA
IFC.REVIGRÉS-Dados de desempenho-Wall Sweeps - Type: Wall Sweep: REVIGRÉS-OMNISTONE-RB-8X90-SOFT-PLATINA
IFC.REVIGRÉS-Dados de especificação-Wall Sweeps - Type: Wall Sweep: REVIGRÉS-OMNISTONE-RB-8X90-SOFT-PLATINA
IFC.REVIGRÉS-Dados geométricos-Wall Sweeps - Type: Wall Sweep: REVIGRÉS-OMNISTONE-RB-8X90-SOFT-PLATINA
IFC.REVIGRÉS-Dados de sustentabilidade-Wall Sweeps - Type: Wall Sweep: REVIGRÉS-OMNISTONE-RB-8X90-SOFT-PLATINA

# IfcBuildingElementProxy: Wall Sweep:REVIGRÉS-OMNISTONE-RB-8X90-SOFT-ROPE, Wall Sweep:REVIGRÉS-OMNISTONE-RB-8X90-SOFT-ROPE:181742
In: Level 1
Type - Pset_ManufacturerTypeInformation - Manufacturer: REVIGRÉS
Type - Pset_ProductRequirements - Category: Wall Sweeps
Type - IFC.REVIGRÉS-Dados gerais-Wall Sweeps - Nome: REVIGRÉS-OMNISTONE-RB-8X90-SOFT-ROPE; TipoProduto: Prensado a seco: grupo BIa UGL | Grés porcelânico técnico; NumeroDeRegistoDAP: EPD-REV-20240006-CCC1-EN; ReferenciaDAP: -; UrlDOP: -
Type - IFC.REVIGRÉS-Dados do fabricante-Wall Sweeps - FabricanteURL: https://www.revigres.pt/; ReferenciaModelo: Omnistone; Acabamento: SOFT; IdentificadorDoOperadorEconomico: 501840856; UrlFabricanteArtigo: https://www.revigres.pt/colecoes/omnistone; PaisOrigem: Portugal
Type - IFC.REVIGRÉS-Dados de desempenho-Wall Sweeps - Rectilinearidade: ± 0.2% máx.± 0.8 mm; Ortogonalidade: ± 0.2% máx.± 1.5 mm; PlanaridadeDaSuperficie: ± 0.3% máx. ± 1.8 mm; AbsorcaoDeAgua: < 0.05%; ModuloDeRuptura: > 45 N/mm130; ResistenciaAFlexao: ≥ 3500 N; ResistenciaAAbrasaoProfunda: < 120 mm131; DilatacaoTermicaLinear: ≤ 8,0x10-6 °C-1; ResistenciaAoChoqueTermico: Resiste; DurabilidadeResistenciaAoGeloDegelo: Resiste; ResistenciaAsManchas: Class 5; ResistenciaABaixasConcentracoesDeAcidosEAlcalis: Classe LA; ResistenciaAAltasConcentracoesDeAcidosEAlcalis: Classe HA; LibertacaoDeCadmio: 0; LibertacaoDeChumbo: 0
Type - IFC.REVIGRÉS-Dados de especificação-Wall Sweeps - VariacaoTonalidade: 3; NivelDeTrafego: 5; EPavimento: Não; ERevestimento: Sim; EExterno: Sim
Type - IFC.REVIGRÉS-Dados geométricos-Wall Sweeps - AlturaNominal: 10.5 mm; ComprimentoNominal: 8 mm; LarguraNominal: 88.9 mm
Type - IFC.REVIGRÉS-Dados de sustentabilidade-Wall Sweeps - ItemEParcialmenteReciclado: 0; PotencialPrivacaoDeAguaConsumoDeAguaPonderado: 4.5; EnergiaTermicaExportada: 0; ItemENovo: Sim; ItemEReciclado: Não; VidaÚtilEsperada: 50; SubstanciasPerigosas: Não; PotencialDeEsgotamentoAbioticoDosRecursosFosseis: 203; PotencialDeEsgotamentoAbioticoDosRecursosNaoFosseisMineraisEMetais: 0.000701; PotencialDeAquecimentoGlobalBiogenico: -0.48; CombustiveisFosseisComPotencialDeAquecimentoGlobal: 13.9; PotencialDeAquecimentoGlobalUsoDoSoloEMudancaDeUsoDoSolo: 0.0246; PotencialDeEutrofizacaoFraccaoDeNutrientesQueAtingemOCompartimentoFinalDeAguaDoce: 0.000189; PotencialDeEutrofizacaoFraccaoDeNutrientesQueAtingemOCompartimentoFinalMarinho: 0.0122; EnergiaRecuperada: 0.00739; ConsumoDeAguaDoce: 0.113; UtilizacaoLiquidaDeAguaDoce: 0.113; ResiduosPerigososEliminados: 0.00221; ResiduosNaoPerigososEliminados: 1.83; MassaTotalDeResiduosRadioactivosEliminados: 0.000394; EnergiaElectricaExportada: 1.55; MateriaisParaRecuperacaoDeEnergia: 0.00739; MateriaisParaReciclagem: 0.0253; UnidadeEPD: 1 m²
Pset_ProvisionForVoid - Shape: Undefined; Width: 1000 mm; Depth: 1000 mm
IFC.REVIGRÉS-Dados do fabricante-Wall Sweeps - Type: Wall Sweep: REVIGRÉS-OMNISTONE-RB-8X90-SOFT-ROPE
IFC.REVIGRÉS-Dados de desempenho-Wall Sweeps - Type: Wall Sweep: REVIGRÉS-OMNISTONE-RB-8X90-SOFT-ROPE
IFC.REVIGRÉS-Dados de especificação-Wall Sweeps - Type: Wall Sweep: REVIGRÉS-OMNISTONE-RB-8X90-SOFT-ROPE
IFC.REVIGRÉS-Dados geométricos-Wall Sweeps - Type: Wall Sweep: REVIGRÉS-OMNISTONE-RB-8X90-SOFT-ROPE
IFC.REVIGRÉS-Dados de sustentabilidade-Wall Sweeps - Type: Wall Sweep: REVIGRÉS-OMNISTONE-RB-8X90-SOFT-ROPE

# IfcBuildingElementProxy: Wall Sweep:REVIGRÉS-OMNISTONE-RB-9.5X30-MATTRECT-BONE, Wall Sweep:REVIGRÉS-OMNISTONE-RB-9.5X30-MATTRECT-BONE:181678
In: Level 1
Type - Pset_ManufacturerTypeInformation - Manufacturer: REVIGRÉS
Type - Pset_ProductRequirements - Category: Wall Sweeps
Type - IFC.REVIGRÉS-Dados gerais-Wall Sweeps - Nome: REVIGRÉS-OMNISTONE-RB-9.5X30-MATT RECT-BONE; TipoProduto: Prensado a seco: grupo BIa UGL | Grés porcelânico técnico; NumeroDeRegistoDAP: EPD-REV-20240006-CCC1-EN; ReferenciaDAP: -; UrlDOP: -
Type - IFC.REVIGRÉS-Dados do fabricante-Wall Sweeps - FabricanteURL: https://www.revigres.pt/; ReferenciaModelo: Omnistone; Acabamento: MATT RECT; IdentificadorDoOperadorEconomico: 501840856; UrlFabricanteArtigo: https://www.revigres.pt/colecoes/omnistone; PaisOrigem: Portugal
Type - IFC.REVIGRÉS-Dados de desempenho-Wall Sweeps - Rectilinearidade: ± 0.2% máx.± 0.8 mm; Ortogonalidade: ± 0.2% máx.± 1.5 mm; PlanaridadeDaSuperficie: ± 0.3% máx. ± 1.8 mm; AbsorcaoDeAgua: < 0.05%; ModuloDeRuptura: > 45 N/mm130; ResistenciaAFlexao: ≥ 3500 N; ResistenciaAAbrasaoProfunda: < 120 mm131; DilatacaoTermicaLinear: ≤ 8,0x10-6 °C-1; ResistenciaAoChoqueTermico: Resiste; DurabilidadeResistenciaAoGeloDegelo: Resiste; ResistenciaAoEscorregamentoDIN51130: R10; ResistenciaAoEscorregamentoDIN51097: B; ResistenciaAoEscorregamentoENV51097: B; ResistenciaAoDeslizamentoENV12633: Class 2; ResistenciaAoEscorregamentoBS7976: >36; ResistenciaAoEscorregamentoANSIA1371: ≥0,42; ResistenciaAoEscorregamentoENV12633: Class 2; ResistenciaAoDeslizamentoBS7976: >36; ResistenciaAsManchas: Class 5; ResistenciaABaixasConcentracoesDeAcidosEAlcalis: Classe LA; ResistenciaAAltasConcentracoesDeAcidosEAlcalis: Classe HA; LibertacaoDeCadmio: 0; LibertacaoDeChumbo: 0
Type - IFC.REVIGRÉS-Dados de especificação-Wall Sweeps - VariacaoTonalidade: 3; NivelDeTrafego: 5; EPavimento: Não; ERevestimento: Sim; EExterno: Sim
Type - IFC.REVIGRÉS-Dados geométricos-Wall Sweeps - AlturaNominal: 9.8 mm; ComprimentoNominal: 9.5 mm; LarguraNominal: 29.5 mm
Type - IFC.REVIGRÉS-Dados de sustentabilidade-Wall Sweeps - ItemEParcialmenteReciclado: 0; PotencialPrivacaoDeAguaConsumoDeAguaPonderado: 4.5; EnergiaTermicaExportada: 0; ItemENovo: Sim; ItemEReciclado: Não; VidaÚtilEsperada: 50; SubstanciasPerigosas: Não; PotencialDeEsgotamentoAbioticoDosRecursosFosseis: 203; PotencialDeEsgotamentoAbioticoDosRecursosNaoFosseisMineraisEMetais: 0.000701; PotencialDeAquecimentoGlobalBiogenico: -0.48; CombustiveisFosseisComPotencialDeAquecimentoGlobal: 13.9; PotencialDeAquecimentoGlobalUsoDoSoloEMudancaDeUsoDoSolo: 0.0246; PotencialDeEutrofizacaoFraccaoDeNutrientesQueAtingemOCompartimentoFinalDeAguaDoce: 0.000189; PotencialDeEutrofizacaoFraccaoDeNutrientesQueAtingemOCompartimentoFinalMarinho: 0.0122; EnergiaRecuperada: 0.00739; ConsumoDeAguaDoce: 0.113; UtilizacaoLiquidaDeAguaDoce: 0.113; ResiduosPerigososEliminados: 0.00221; ResiduosNaoPerigososEliminados: 1.83; MassaTotalDeResiduosRadioactivosEliminados: 0.000394; EnergiaElectricaExportada: 1.55; MateriaisParaRecuperacaoDeEnergia: 0.00739; MateriaisParaReciclagem: 0.0253; UnidadeEPD: 1 m²
Pset_ProvisionForVoid - Shape: Undefined; Width: 1000 mm; Depth: 1000 mm
IFC.REVIGRÉS-Dados do fabricante-Wall Sweeps - Type: Wall Sweep: REVIGRÉS-OMNISTONE-RB-9.5X30-MATTRECT-BONE
IFC.REVIGRÉS-Dados de desempenho-Wall Sweeps - Type: Wall Sweep: REVIGRÉS-OMNISTONE-RB-9.5X30-MATTRECT-BONE
IFC.REVIGRÉS-Dados de especificação-Wall Sweeps - Type: Wall Sweep: REVIGRÉS-OMNISTONE-RB-9.5X30-MATTRECT-BONE
IFC.REVIGRÉS-Dados geométricos-Wall Sweeps - Type: Wall Sweep: REVIGRÉS-OMNISTONE-RB-9.5X30-MATTRECT-BONE
IFC.REVIGRÉS-Dados de sustentabilidade-Wall Sweeps - Type: Wall Sweep: REVIGRÉS-OMNISTONE-RB-9.5X30-MATTRECT-BONE

# IfcBuildingElementProxy: Wall Sweep:REVIGRÉS-OMNISTONE-RB-9.5X30-MATTRECT-ICE, Wall Sweep:REVIGRÉS-OMNISTONE-RB-9.5X30-MATTRECT-ICE:181690
In: Level 1
Type - Pset_ManufacturerTypeInformation - Manufacturer: REVIGRÉS
Type - Pset_ProductRequirements - Category: Wall Sweeps
Type - IFC.REVIGRÉS-Dados gerais-Wall Sweeps - Nome: REVIGRÉS-OMNISTONE-RB-9.5X30-MATT RECT-ICE; TipoProduto: Prensado a seco: grupo BIa UGL | Grés porcelânico técnico; NumeroDeRegistoDAP: EPD-REV-20240006-CCC1-EN; ReferenciaDAP: -; UrlDOP: -
Type - IFC.REVIGRÉS-Dados do fabricante-Wall Sweeps - FabricanteURL: https://www.revigres.pt/; ReferenciaModelo: Omnistone; Acabamento: MATT RECT; IdentificadorDoOperadorEconomico: 501840856; UrlFabricanteArtigo: https://www.revigres.pt/colecoes/omnistone; PaisOrigem: Portugal
Type - IFC.REVIGRÉS-Dados de desempenho-Wall Sweeps - Rectilinearidade: ± 0.2% máx.± 0.8 mm; Ortogonalidade: ± 0.2% máx.± 1.5 mm; PlanaridadeDaSuperficie: ± 0.3% máx. ± 1.8 mm; AbsorcaoDeAgua: < 0.05%; ModuloDeRuptura: > 45 N/mm130; ResistenciaAFlexao: ≥ 3500 N; ResistenciaAAbrasaoProfunda: < 120 mm131; DilatacaoTermicaLinear: ≤ 8,0x10-6 °C-1; ResistenciaAoChoqueTermico: Resiste; DurabilidadeResistenciaAoGeloDegelo: Resiste; ResistenciaAoEscorregamentoDIN51130: R10; ResistenciaAoEscorregamentoDIN51097: B; ResistenciaAoEscorregamentoENV51097: B; ResistenciaAoDeslizamentoENV12633: Class 2; ResistenciaAoEscorregamentoBS7976: >36; ResistenciaAoEscorregamentoANSIA1371: ≥0,42; ResistenciaAoEscorregamentoENV12633: Class 2; ResistenciaAoDeslizamentoBS7976: >36; ResistenciaAsManchas: Class 5; ResistenciaABaixasConcentracoesDeAcidosEAlcalis: Classe LA; ResistenciaAAltasConcentracoesDeAcidosEAlcalis: Classe HA; LibertacaoDeCadmio: 0; LibertacaoDeChumbo: 0
Type - IFC.REVIGRÉS-Dados de especificação-Wall Sweeps - VariacaoTonalidade: 3; NivelDeTrafego: 5; EPavimento: Não; ERevestimento: Sim; EExterno: Sim
Type - IFC.REVIGRÉS-Dados geométricos-Wall Sweeps - AlturaNominal: 9.8 mm; ComprimentoNominal: 9.5 mm; LarguraNominal: 29.5 mm
Type - IFC.REVIGRÉS-Dados de sustentabilidade-Wall Sweeps - ItemEParcialmenteReciclado: 0; PotencialPrivacaoDeAguaConsumoDeAguaPonderado: 4.5; EnergiaTermicaExportada: 0; ItemENovo: Sim; ItemEReciclado: Não; VidaÚtilEsperada: 50; SubstanciasPerigosas: Não; PotencialDeEsgotamentoAbioticoDosRecursosFosseis: 203; PotencialDeEsgotamentoAbioticoDosRecursosNaoFosseisMineraisEMetais: 0.000701; PotencialDeAquecimentoGlobalBiogenico: -0.48; CombustiveisFosseisComPotencialDeAquecimentoGlobal: 13.9; PotencialDeAquecimentoGlobalUsoDoSoloEMudancaDeUsoDoSolo: 0.0246; PotencialDeEutrofizacaoFraccaoDeNutrientesQueAtingemOCompartimentoFinalDeAguaDoce: 0.000189; PotencialDeEutrofizacaoFraccaoDeNutrientesQueAtingemOCompartimentoFinalMarinho: 0.0122; EnergiaRecuperada: 0.00739; ConsumoDeAguaDoce: 0.113; UtilizacaoLiquidaDeAguaDoce: 0.113; ResiduosPerigososEliminados: 0.00221; ResiduosNaoPerigososEliminados: 1.83; MassaTotalDeResiduosRadioactivosEliminados: 0.000394; EnergiaElectricaExportada: 1.55; MateriaisParaRecuperacaoDeEnergia: 0.00739; MateriaisParaReciclagem: 0.0253; UnidadeEPD: 1 m²
Pset_ProvisionForVoid - Shape: Undefined; Width: 1000 mm; Depth: 1000 mm
IFC.REVIGRÉS-Dados do fabricante-Wall Sweeps - Type: Wall Sweep: REVIGRÉS-OMNISTONE-RB-9.5X30-MATTRECT-ICE
IFC.REVIGRÉS-Dados de desempenho-Wall Sweeps - Type: Wall Sweep: REVIGRÉS-OMNISTONE-RB-9.5X30-MATTRECT-ICE
IFC.REVIGRÉS-Dados de especificação-Wall Sweeps - Type: Wall Sweep: REVIGRÉS-OMNISTONE-RB-9.5X30-MATTRECT-ICE
IFC.REVIGRÉS-Dados geométricos-Wall Sweeps - Type: Wall Sweep: REVIGRÉS-OMNISTONE-RB-9.5X30-MATTRECT-ICE
IFC.REVIGRÉS-Dados de sustentabilidade-Wall Sweeps - Type: Wall Sweep: REVIGRÉS-OMNISTONE-RB-9.5X30-MATTRECT-ICE

# IfcBuildingElementProxy: Wall Sweep:REVIGRÉS-OMNISTONE-RB-9.5X30-MATTRECT-IRON, Wall Sweep:REVIGRÉS-OMNISTONE-RB-9.5X30-MATTRECT-IRON:181702
In: Level 1
Type - Pset_ManufacturerTypeInformation - Manufacturer: REVIGRÉS
Type - Pset_ProductRequirements - Category: Wall Sweeps
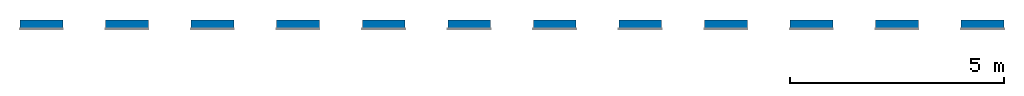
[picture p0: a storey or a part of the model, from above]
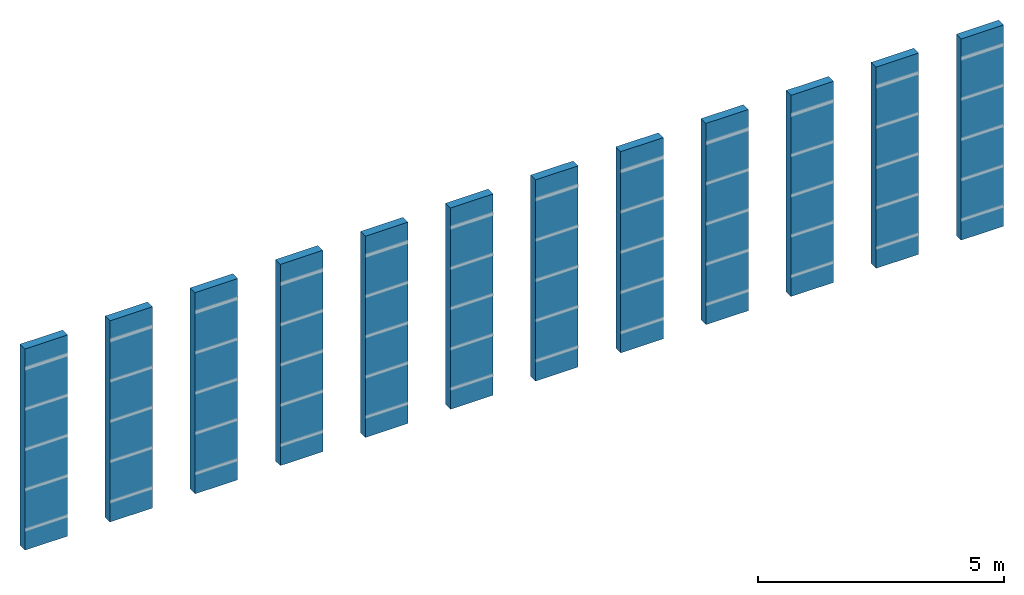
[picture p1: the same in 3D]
Properties of the parts of a building model (IFC2X3), part 4 of 4

# IfcBuildingElementProxy: Wall Sweep:REVIGRÉS-OMNISTONE-RB-9.5X30-MATTRECT-IRON, Wall Sweep:REVIGRÉS-OMNISTONE-RB-9.5X30-MATTRECT-IRON:181702
Type - IFC.REVIGRÉS-Dados gerais-Wall Sweeps - Nome: REVIGRÉS-OMNISTONE-RB-9.5X30-MATT RECT-IRON; TipoProduto: Prensado a seco: grupo BIa UGL | Grés porcelânico técnico; NumeroDeRegistoDAP: EPD-REV-20240006-CCC1-EN; ReferenciaDAP: -; UrlDOP: -
Type - IFC.REVIGRÉS-Dados do fabricante-Wall Sweeps - FabricanteURL: https://www.revigres.pt/; ReferenciaModelo: Omnistone; Acabamento: MATT RECT; IdentificadorDoOperadorEconomico: 501840856; UrlFabricanteArtigo: https://www.revigres.pt/colecoes/omnistone; PaisOrigem: Portugal
Type - IFC.REVIGRÉS-Dados de desempenho-Wall Sweeps - Rectilinearidade: ± 0.2% máx.± 0.8 mm; Ortogonalidade: ± 0.2% máx.± 1.5 mm; PlanaridadeDaSuperficie: ± 0.3% máx. ± 1.8 mm; AbsorcaoDeAgua: < 0.05%; ModuloDeRuptura: > 45 N/mm130; ResistenciaAFlexao: ≥ 3500 N; ResistenciaAAbrasaoProfunda: < 120 mm131; DilatacaoTermicaLinear: ≤ 8,0x10-6 °C-1; ResistenciaAoChoqueTermico: Resiste; DurabilidadeResistenciaAoGeloDegelo: Resiste; ResistenciaAoEscorregamentoDIN51130: R10; ResistenciaAoEscorregamentoDIN51097: B; ResistenciaAoEscorregamentoENV51097: B; ResistenciaAoDeslizamentoENV12633: Class 2; ResistenciaAoEscorregamentoBS7976: >36; ResistenciaAoEscorregamentoANSIA1371: ≥0,42; ResistenciaAoEscorregamentoENV12633: Class 2; ResistenciaAoDeslizamentoBS7976: >36; ResistenciaAsManchas: Class 5; ResistenciaABaixasConcentracoesDeAcidosEAlcalis: Classe LA; ResistenciaAAltasConcentracoesDeAcidosEAlcalis: Classe HA; LibertacaoDeCadmio: 0; LibertacaoDeChumbo: 0
Type - IFC.REVIGRÉS-Dados de especificação-Wall Sweeps - VariacaoTonalidade: 3; NivelDeTrafego: 5; EPavimento: Não; ERevestimento: Sim; EExterno: Sim
Type - IFC.REVIGRÉS-Dados geométricos-Wall Sweeps - AlturaNominal: 9.8 mm; ComprimentoNominal: 9.5 mm; LarguraNominal: 29.5 mm
Type - IFC.REVIGRÉS-Dados de sustentabilidade-Wall Sweeps - PotencialPrivacaoDeAguaConsumoDeAguaPonderado: 4.5; EnergiaTermicaExportada: 0; ItemENovo: Sim; ItemEParcialmenteReciclado: 0.14; ItemEReciclado: Sim; VidaÚtilEsperada: 50; SubstanciasPerigosas: Não; PotencialDeEsgotamentoAbioticoDosRecursosFosseis: 203; PotencialDeEsgotamentoAbioticoDosRecursosNaoFosseisMineraisEMetais: 0.000701; PotencialDeAquecimentoGlobalBiogenico: -0.48; CombustiveisFosseisComPotencialDeAquecimentoGlobal: 13.9; PotencialDeAquecimentoGlobalUsoDoSoloEMudancaDeUsoDoSolo: 0.0246; PotencialDeEutrofizacaoFraccaoDeNutrientesQueAtingemOCompartimentoFinalDeAguaDoce: 0.000189; PotencialDeEutrofizacaoFraccaoDeNutrientesQueAtingemOCompartimentoFinalMarinho: 0.0122; EnergiaRecuperada: 0.00739; ConsumoDeAguaDoce: 0.113; UtilizacaoLiquidaDeAguaDoce: 0.113; ResiduosPerigososEliminados: 0.00221; ResiduosNaoPerigososEliminados: 1.83; MassaTotalDeResiduosRadioactivosEliminados: 0.000394; EnergiaElectricaExportada: 1.55; MateriaisParaRecuperacaoDeEnergia: 0.00739; MateriaisParaReciclagem: 0.0253; UnidadeEPD: 1 m²
Pset_ProvisionForVoid - Shape: Undefined; Width: 1000 mm; Depth: 1000 mm
IFC.REVIGRÉS-Dados do fabricante-Wall Sweeps - Type: Wall Sweep: REVIGRÉS-OMNISTONE-RB-9.5X30-MATTRECT-IRON
IFC.REVIGRÉS-Dados de desempenho-Wall Sweeps - Type: Wall Sweep: REVIGRÉS-OMNISTONE-RB-9.5X30-MATTRECT-IRON
IFC.REVIGRÉS-Dados de especificação-Wall Sweeps - Type: Wall Sweep: REVIGRÉS-OMNISTONE-RB-9.5X30-MATTRECT-IRON
IFC.REVIGRÉS-Dados geométricos-Wall Sweeps - Type: Wall Sweep: REVIGRÉS-OMNISTONE-RB-9.5X30-MATTRECT-IRON
IFC.REVIGRÉS-Dados de sustentabilidade-Wall Sweeps - Type: Wall Sweep: REVIGRÉS-OMNISTONE-RB-9.5X30-MATTRECT-IRON

# IfcBuildingElementProxy: Wall Sweep:REVIGRÉS-OMNISTONE-RB-9.5X30-MATTRECT-JET, Wall Sweep:REVIGRÉS-OMNISTONE-RB-9.5X30-MATTRECT-JET:181714
In: Level 1
Type - Pset_ManufacturerTypeInformation - Manufacturer: REVIGRÉS
Type - Pset_ProductRequirements - Category: Wall Sweeps
Type - IFC.REVIGRÉS-Dados gerais-Wall Sweeps - Nome: REVIGRÉS-OMNISTONE-RB-9.5X30-MATT RECT-JET; TipoProduto: Prensado a seco: grupo BIa UGL | Grés porcelânico técnico; NumeroDeRegistoDAP: EPD-REV-20240006-CCC1-EN; ReferenciaDAP: -; UrlDOP: -
Type - IFC.REVIGRÉS-Dados do fabricante-Wall Sweeps - FabricanteURL: https://www.revigres.pt/; ReferenciaModelo: Omnistone; Acabamento: MATT RECT; IdentificadorDoOperadorEconomico: 501840856; UrlFabricanteArtigo: https://www.revigres.pt/colecoes/omnistone; PaisOrigem: Portugal
Type - IFC.REVIGRÉS-Dados de desempenho-Wall Sweeps - Rectilinearidade: ± 0.2% máx.± 0.8 mm; Ortogonalidade: ± 0.2% máx.± 1.5 mm; PlanaridadeDaSuperficie: ± 0.3% máx. ± 1.8 mm; AbsorcaoDeAgua: < 0.05%; ModuloDeRuptura: > 45 N/mm130; ResistenciaAFlexao: ≥ 3500 N; ResistenciaAAbrasaoProfunda: < 120 mm131; DilatacaoTermicaLinear: ≤ 8,0x10-6 °C-1; ResistenciaAoChoqueTermico: Resiste; DurabilidadeResistenciaAoGeloDegelo: Resiste; ResistenciaAoEscorregamentoDIN51130: R10; ResistenciaAoEscorregamentoDIN51097: B; ResistenciaAoEscorregamentoENV51097: B; ResistenciaAoDeslizamentoENV12633: Class 2; ResistenciaAoEscorregamentoBS7976: >36; ResistenciaAoEscorregamentoANSIA1371: ≥0,42; ResistenciaAoEscorregamentoENV12633: Class 2; ResistenciaAoDeslizamentoBS7976: >36; ResistenciaAsManchas: Class 5; ResistenciaABaixasConcentracoesDeAcidosEAlcalis: Classe LA; ResistenciaAAltasConcentracoesDeAcidosEAlcalis: Classe HA; LibertacaoDeCadmio: 0; LibertacaoDeChumbo: 0
Type - IFC.REVIGRÉS-Dados de especificação-Wall Sweeps - VariacaoTonalidade: 3; NivelDeTrafego: 5; EPavimento: Não; ERevestimento: Sim; EExterno: Sim
Type - IFC.REVIGRÉS-Dados geométricos-Wall Sweeps - AlturaNominal: 9.8 mm; ComprimentoNominal: 9.5 mm; LarguraNominal: 29.5 mm
Type - IFC.REVIGRÉS-Dados de sustentabilidade-Wall Sweeps - ItemEParcialmenteReciclado: 0; PotencialPrivacaoDeAguaConsumoDeAguaPonderado: 4.5; EnergiaTermicaExportada: 0; ItemENovo: Sim; ItemEReciclado: Não; VidaÚtilEsperada: 50; SubstanciasPerigosas: Não; PotencialDeEsgotamentoAbioticoDosRecursosFosseis: 203; PotencialDeEsgotamentoAbioticoDosRecursosNaoFosseisMineraisEMetais: 0.000701; PotencialDeAquecimentoGlobalBiogenico: -0.48; CombustiveisFosseisComPotencialDeAquecimentoGlobal: 13.9; PotencialDeAquecimentoGlobalUsoDoSoloEMudancaDeUsoDoSolo: 0.0246; PotencialDeEutrofizacaoFraccaoDeNutrientesQueAtingemOCompartimentoFinalDeAguaDoce: 0.000189; PotencialDeEutrofizacaoFraccaoDeNutrientesQueAtingemOCompartimentoFinalMarinho: 0.0122; EnergiaRecuperada: 0.00739; ConsumoDeAguaDoce: 0.113; UtilizacaoLiquidaDeAguaDoce: 0.113; ResiduosPerigososEliminados: 0.00221; ResiduosNaoPerigososEliminados: 1.83; MassaTotalDeResiduosRadioactivosEliminados: 0.000394; EnergiaElectricaExportada: 1.55; MateriaisParaRecuperacaoDeEnergia: 0.00739; MateriaisParaReciclagem: 0.0253; UnidadeEPD: 1 m²
Pset_ProvisionForVoid - Shape: Undefined; Width: 1000 mm; Depth: 1000 mm
IFC.REVIGRÉS-Dados do fabricante-Wall Sweeps - Type: Wall Sweep: REVIGRÉS-OMNISTONE-RB-9.5X30-MATTRECT-JET
IFC.REVIGRÉS-Dados de desempenho-Wall Sweeps - Type: Wall Sweep: REVIGRÉS-OMNISTONE-RB-9.5X30-MATTRECT-JET
IFC.REVIGRÉS-Dados de especificação-Wall Sweeps - Type: Wall Sweep: REVIGRÉS-OMNISTONE-RB-9.5X30-MATTRECT-JET
IFC.REVIGRÉS-Dados geométricos-Wall Sweeps - Type: Wall Sweep: REVIGRÉS-OMNISTONE-RB-9.5X30-MATTRECT-JET
IFC.REVIGRÉS-Dados de sustentabilidade-Wall Sweeps - Type: Wall Sweep: REVIGRÉS-OMNISTONE-RB-9.5X30-MATTRECT-JET

# IfcBuildingElementProxy: Wall Sweep:REVIGRÉS-OMNISTONE-RB-9.5X30-MATTRECT-PLATINA, Wall Sweep:REVIGRÉS-OMNISTONE-RB-9.5X30-MATTRECT-PLATINA:181726
In: Level 1
Type - Pset_ManufacturerTypeInformation - Manufacturer: REVIGRÉS
Type - Pset_ProductRequirements - Category: Wall Sweeps
Type - IFC.REVIGRÉS-Dados gerais-Wall Sweeps - Nome: REVIGRÉS-OMNISTONE-RB-9.5X30-MATT RECT-PLATINA; TipoProduto: Prensado a seco: grupo BIa UGL | Grés porcelânico técnico; NumeroDeRegistoDAP: EPD-REV-20240006-CCC1-EN; ReferenciaDAP: -; UrlDOP: -
Type - IFC.REVIGRÉS-Dados do fabricante-Wall Sweeps - FabricanteURL: https://www.revigres.pt/; ReferenciaModelo: Omnistone; Acabamento: MATT RECT; IdentificadorDoOperadorEconomico: 501840856; UrlFabricanteArtigo: https://www.revigres.pt/colecoes/omnistone; PaisOrigem: Portugal
Type - IFC.REVIGRÉS-Dados de desempenho-Wall Sweeps - Rectilinearidade: ± 0.2% máx.± 0.8 mm; Ortogonalidade: ± 0.2% máx.± 1.5 mm; PlanaridadeDaSuperficie: ± 0.3% máx. ± 1.8 mm; AbsorcaoDeAgua: < 0.05%; ModuloDeRuptura: > 45 N/mm130; ResistenciaAFlexao: ≥ 3500 N; ResistenciaAAbrasaoProfunda: < 120 mm131; DilatacaoTermicaLinear: ≤ 8,0x10-6 °C-1; ResistenciaAoChoqueTermico: Resiste; DurabilidadeResistenciaAoGeloDegelo: Resiste; ResistenciaAoEscorregamentoDIN51130: R10; ResistenciaAoEscorregamentoDIN51097: B; ResistenciaAoEscorregamentoENV51097: B; ResistenciaAoDeslizamentoENV12633: Class 2; ResistenciaAoEscorregamentoBS7976: >36; ResistenciaAoEscorregamentoANSIA1371: ≥0,42; ResistenciaAoEscorregamentoENV12633: Class 2; ResistenciaAoDeslizamentoBS7976: >36; ResistenciaAsManchas: Class 5; ResistenciaABaixasConcentracoesDeAcidosEAlcalis: Classe LA; ResistenciaAAltasConcentracoesDeAcidosEAlcalis: Classe HA; LibertacaoDeCadmio: 0; LibertacaoDeChumbo: 0
Type - IFC.REVIGRÉS-Dados de especificação-Wall Sweeps - VariacaoTonalidade: 3; NivelDeTrafego: 5; EPavimento: Não; ERevestimento: Sim; EExterno: Sim
Type - IFC.REVIGRÉS-Dados geométricos-Wall Sweeps - AlturaNominal: 9.8 mm; ComprimentoNominal: 9.5 mm; LarguraNominal: 29.5 mm
Type - IFC.REVIGRÉS-Dados de sustentabilidade-Wall Sweeps - ItemEParcialmenteReciclado: 0; PotencialPrivacaoDeAguaConsumoDeAguaPonderado: 4.5; EnergiaTermicaExportada: 0; ItemENovo: Sim; ItemEReciclado: Não; VidaÚtilEsperada: 50; SubstanciasPerigosas: Não; PotencialDeEsgotamentoAbioticoDosRecursosFosseis: 203; PotencialDeEsgotamentoAbioticoDosRecursosNaoFosseisMineraisEMetais: 0.000701; PotencialDeAquecimentoGlobalBiogenico: -0.48; CombustiveisFosseisComPotencialDeAquecimentoGlobal: 13.9; PotencialDeAquecimentoGlobalUsoDoSoloEMudancaDeUsoDoSolo: 0.0246; PotencialDeEutrofizacaoFraccaoDeNutrientesQueAtingemOCompartimentoFinalDeAguaDoce: 0.000189; PotencialDeEutrofizacaoFraccaoDeNutrientesQueAtingemOCompartimentoFinalMarinho: 0.0122; EnergiaRecuperada: 0.00739; ConsumoDeAguaDoce: 0.113; UtilizacaoLiquidaDeAguaDoce: 0.113; ResiduosPerigososEliminados: 0.00221; ResiduosNaoPerigososEliminados: 1.83; MassaTotalDeResiduosRadioactivosEliminados: 0.000394; EnergiaElectricaExportada: 1.55; MateriaisParaRecuperacaoDeEnergia: 0.00739; MateriaisParaReciclagem: 0.0253; UnidadeEPD: 1 m²
Pset_ProvisionForVoid - Shape: Undefined; Width: 1000 mm; Depth: 1000 mm
IFC.REVIGRÉS-Dados do fabricante-Wall Sweeps - Type: Wall Sweep: REVIGRÉS-OMNISTONE-RB-9.5X30-MATTRECT-PLATINA
IFC.REVIGRÉS-Dados de desempenho-Wall Sweeps - Type: Wall Sweep: REVIGRÉS-OMNISTONE-RB-9.5X30-MATTRECT-PLATINA
IFC.REVIGRÉS-Dados de especificação-Wall Sweeps - Type: Wall Sweep: REVIGRÉS-OMNISTONE-RB-9.5X30-MATTRECT-PLATINA
IFC.REVIGRÉS-Dados geométricos-Wall Sweeps - Type: Wall Sweep: REVIGRÉS-OMNISTONE-RB-9.5X30-MATTRECT-PLATINA
IFC.REVIGRÉS-Dados de sustentabilidade-Wall Sweeps - Type: Wall Sweep: REVIGRÉS-OMNISTONE-RB-9.5X30-MATTRECT-PLATINA

# IfcBuildingElementProxy: Wall Sweep:REVIGRÉS-OMNISTONE-RB-9.5X30-MATTRECT-ROPE, Wall Sweep:REVIGRÉS-OMNISTONE-RB-9.5X30-MATTRECT-ROPE:181738
In: Level 1
Type - Pset_ManufacturerTypeInformation - Manufacturer: REVIGRÉS
Type - Pset_ProductRequirements - Category: Wall Sweeps
Type - IFC.REVIGRÉS-Dados gerais-Wall Sweeps - Nome: REVIGRÉS-OMNISTONE-RB-9.5X30-MATT RECT-ROPE; TipoProduto: Prensado a seco: grupo BIa UGL | Grés porcelânico técnico; NumeroDeRegistoDAP: EPD-REV-20240006-CCC1-EN; ReferenciaDAP: -; UrlDOP: -
Type - IFC.REVIGRÉS-Dados do fabricante-Wall Sweeps - FabricanteURL: https://www.revigres.pt/; ReferenciaModelo: Omnistone; Acabamento: MATT RECT; IdentificadorDoOperadorEconomico: 501840856; UrlFabricanteArtigo: https://www.revigres.pt/colecoes/omnistone; PaisOrigem: Portugal
Type - IFC.REVIGRÉS-Dados de desempenho-Wall Sweeps - Rectilinearidade: ± 0.2% máx.± 0.8 mm; Ortogonalidade: ± 0.2% máx.± 1.5 mm; PlanaridadeDaSuperficie: ± 0.3% máx. ± 1.8 mm; AbsorcaoDeAgua: < 0.05%; ModuloDeRuptura: > 45 N/mm130; ResistenciaAFlexao: ≥ 3500 N; ResistenciaAAbrasaoProfunda: < 120 mm131; DilatacaoTermicaLinear: ≤ 8,0x10-6 °C-1; ResistenciaAoChoqueTermico: Resiste; DurabilidadeResistenciaAoGeloDegelo: Resiste; ResistenciaAoEscorregamentoDIN51130: R10; ResistenciaAoEscorregamentoDIN51097: B; ResistenciaAoEscorregamentoENV51097: B; ResistenciaAoDeslizamentoENV12633: Class 2; ResistenciaAoEscorregamentoBS7976: >36; ResistenciaAoEscorregamentoANSIA1371: ≥0,42; ResistenciaAoEscorregamentoENV12633: Class 2; ResistenciaAoDeslizamentoBS7976: >36; ResistenciaAsManchas: Class 5; ResistenciaABaixasConcentracoesDeAcidosEAlcalis: Classe LA; ResistenciaAAltasConcentracoesDeAcidosEAlcalis: Classe HA; LibertacaoDeCadmio: 0; LibertacaoDeChumbo: 0
Type - IFC.REVIGRÉS-Dados de especificação-Wall Sweeps - VariacaoTonalidade: 3; NivelDeTrafego: 5; EPavimento: Não; ERevestimento: Sim; EExterno: Sim
Type - IFC.REVIGRÉS-Dados geométricos-Wall Sweeps - AlturaNominal: 9.8 mm; ComprimentoNominal: 9.5 mm; LarguraNominal: 29.5 mm
Type - IFC.REVIGRÉS-Dados de sustentabilidade-Wall Sweeps - ItemEParcialmenteReciclado: 0; PotencialPrivacaoDeAguaConsumoDeAguaPonderado: 4.5; EnergiaTermicaExportada: 0; ItemENovo: Sim; ItemEReciclado: Não; VidaÚtilEsperada: 50; SubstanciasPerigosas: Não; PotencialDeEsgotamentoAbioticoDosRecursosFosseis: 203; PotencialDeEsgotamentoAbioticoDosRecursosNaoFosseisMineraisEMetais: 0.000701; PotencialDeAquecimentoGlobalBiogenico: -0.48; CombustiveisFosseisComPotencialDeAquecimentoGlobal: 13.9; PotencialDeAquecimentoGlobalUsoDoSoloEMudancaDeUsoDoSolo: 0.0246; PotencialDeEutrofizacaoFraccaoDeNutrientesQueAtingemOCompartimentoFinalDeAguaDoce: 0.000189; PotencialDeEutrofizacaoFraccaoDeNutrientesQueAtingemOCompartimentoFinalMarinho: 0.0122; EnergiaRecuperada: 0.00739; ConsumoDeAguaDoce: 0.113; UtilizacaoLiquidaDeAguaDoce: 0.113; ResiduosPerigososEliminados: 0.00221; ResiduosNaoPerigososEliminados: 1.83; MassaTotalDeResiduosRadioactivosEliminados: 0.000394; EnergiaElectricaExportada: 1.55; MateriaisParaRecuperacaoDeEnergia: 0.00739; MateriaisParaReciclagem: 0.0253; UnidadeEPD: 1 m²
Pset_ProvisionForVoid - Shape: Undefined; Width: 1000 mm; Depth: 1000 mm
IFC.REVIGRÉS-Dados do fabricante-Wall Sweeps - Type: Wall Sweep: REVIGRÉS-OMNISTONE-RB-9.5X30-MATTRECT-ROPE
IFC.REVIGRÉS-Dados de desempenho-Wall Sweeps - Type: Wall Sweep: REVIGRÉS-OMNISTONE-RB-9.5X30-MATTRECT-ROPE
IFC.REVIGRÉS-Dados de especificação-Wall Sweeps - Type: Wall Sweep: REVIGRÉS-OMNISTONE-RB-9.5X30-MATTRECT-ROPE
IFC.REVIGRÉS-Dados geométricos-Wall Sweeps - Type: Wall Sweep: REVIGRÉS-OMNISTONE-RB-9.5X30-MATTRECT-ROPE
IFC.REVIGRÉS-Dados de sustentabilidade-Wall Sweeps - Type: Wall Sweep: REVIGRÉS-OMNISTONE-RB-9.5X30-MATTRECT-ROPE

# IfcBuildingElementProxy: Wall Sweep:REVIGRÉS-OMNISTONE-RB-9.5X30-SOFT-BONE, Wall Sweep:REVIGRÉS-OMNISTONE-RB-9.5X30-SOFT-BONE:181684
In: Level 1
Type - Pset_ManufacturerTypeInformation - Manufacturer: REVIGRÉS
Type - Pset_ProductRequirements - Category: Wall Sweeps
Type - IFC.REVIGRÉS-Dados gerais-Wall Sweeps - Nome: REVIGRÉS-OMNISTONE-RB-9.5X30-SOFT-BONE; TipoProduto: Prensado a seco: grupo BIa UGL | Grés porcelânico técnico; NumeroDeRegistoDAP: EPD-REV-20240006-CCC1-EN; ReferenciaDAP: -; UrlDOP: -
Type - IFC.REVIGRÉS-Dados do fabricante-Wall Sweeps - FabricanteURL: https://www.revigres.pt/; ReferenciaModelo: Omnistone; Acabamento: SOFT; IdentificadorDoOperadorEconomico: 501840856; UrlFabricanteArtigo: https://www.revigres.pt/colecoes/omnistone; PaisOrigem: Portugal
Type - IFC.REVIGRÉS-Dados de desempenho-Wall Sweeps - Rectilinearidade: ± 0.2% máx.± 0.8 mm; Ortogonalidade: ± 0.2% máx.± 1.5 mm; PlanaridadeDaSuperficie: ± 0.3% máx. ± 1.8 mm; AbsorcaoDeAgua: < 0.05%; ModuloDeRuptura: > 45 N/mm130; ResistenciaAFlexao: ≥ 3500 N; ResistenciaAAbrasaoProfunda: < 120 mm131; DilatacaoTermicaLinear: ≤ 8,0x10-6 °C-1; ResistenciaAoChoqueTermico: Resiste; DurabilidadeResistenciaAoGeloDegelo: Resiste; ResistenciaAsManchas: Class 5; ResistenciaABaixasConcentracoesDeAcidosEAlcalis: Classe LA; ResistenciaAAltasConcentracoesDeAcidosEAlcalis: Classe HA; LibertacaoDeCadmio: 0; LibertacaoDeChumbo: 0
Type - IFC.REVIGRÉS-Dados de especificação-Wall Sweeps - VariacaoTonalidade: 3; NivelDeTrafego: 5; EPavimento: Não; ERevestimento: Sim; EExterno: Sim
Type - IFC.REVIGRÉS-Dados geométricos-Wall Sweeps - AlturaNominal: 9.8 mm; ComprimentoNominal: 9.5 mm; LarguraNominal: 29.5 mm
Type - IFC.REVIGRÉS-Dados de sustentabilidade-Wall Sweeps - ItemEParcialmenteReciclado: 0; PotencialPrivacaoDeAguaConsumoDeAguaPonderado: 4.5; EnergiaTermicaExportada: 0; ItemENovo: Sim; ItemEReciclado: Não; VidaÚtilEsperada: 50; SubstanciasPerigosas: Não; PotencialDeEsgotamentoAbioticoDosRecursosFosseis: 203; PotencialDeEsgotamentoAbioticoDosRecursosNaoFosseisMineraisEMetais: 0.000701; PotencialDeAquecimentoGlobalBiogenico: -0.48; CombustiveisFosseisComPotencialDeAquecimentoGlobal: 13.9; PotencialDeAquecimentoGlobalUsoDoSoloEMudancaDeUsoDoSolo: 0.0246; PotencialDeEutrofizacaoFraccaoDeNutrientesQueAtingemOCompartimentoFinalDeAguaDoce: 0.000189; PotencialDeEutrofizacaoFraccaoDeNutrientesQueAtingemOCompartimentoFinalMarinho: 0.0122; EnergiaRecuperada: 0.00739; ConsumoDeAguaDoce: 0.113; UtilizacaoLiquidaDeAguaDoce: 0.113; ResiduosPerigososEliminados: 0.00221; ResiduosNaoPerigososEliminados: 1.83; MassaTotalDeResiduosRadioactivosEliminados: 0.000394; EnergiaElectricaExportada: 1.55; MateriaisParaRecuperacaoDeEnergia: 0.00739; MateriaisParaReciclagem: 0.0253; UnidadeEPD: 1 m²
Pset_ProvisionForVoid - Shape: Undefined; Width: 1000 mm; Depth: 1000 mm
IFC.REVIGRÉS-Dados do fabricante-Wall Sweeps - Type: Wall Sweep: REVIGRÉS-OMNISTONE-RB-9.5X30-SOFT-BONE
IFC.REVIGRÉS-Dados de desempenho-Wall Sweeps - Type: Wall Sweep: REVIGRÉS-OMNISTONE-RB-9.5X30-SOFT-BONE
IFC.REVIGRÉS-Dados de especificação-Wall Sweeps - Type: Wall Sweep: REVIGRÉS-OMNISTONE-RB-9.5X30-SOFT-BONE
IFC.REVIGRÉS-Dados geométricos-Wall Sweeps - Type: Wall Sweep: REVIGRÉS-OMNISTONE-RB-9.5X30-SOFT-BONE
IFC.REVIGRÉS-Dados de sustentabilidade-Wall Sweeps - Type: Wall Sweep: REVIGRÉS-OMNISTONE-RB-9.5X30-SOFT-BONE

# IfcBuildingElementProxy: Wall Sweep:REVIGRÉS-OMNISTONE-RB-9.5X30-SOFT-ICE, Wall Sweep:REVIGRÉS-OMNISTONE-RB-9.5X30-SOFT-ICE:181696
In: Level 1
Type - Pset_ManufacturerTypeInformation - Manufacturer: REVIGRÉS
Type - Pset_ProductRequirements - Category: Wall Sweeps
Type - IFC.REVIGRÉS-Dados gerais-Wall Sweeps - Nome: REVIGRÉS-OMNISTONE-RB-9.5X30-SOFT-ICE; TipoProduto: Prensado a seco: grupo BIa UGL | Grés porcelânico técnico; NumeroDeRegistoDAP: EPD-REV-20240006-CCC1-EN; ReferenciaDAP: -; UrlDOP: -
Type - IFC.REVIGRÉS-Dados do fabricante-Wall Sweeps - FabricanteURL: https://www.revigres.pt/; ReferenciaModelo: Omnistone; Acabamento: SOFT; IdentificadorDoOperadorEconomico: 501840856; UrlFabricanteArtigo: https://www.revigres.pt/colecoes/omnistone; PaisOrigem: Portugal
Type - IFC.REVIGRÉS-Dados de desempenho-Wall Sweeps - Rectilinearidade: ± 0.2% máx.± 0.8 mm; Ortogonalidade: ± 0.2% máx.± 1.5 mm; PlanaridadeDaSuperficie: ± 0.3% máx. ± 1.8 mm; AbsorcaoDeAgua: < 0.05%; ModuloDeRuptura: > 45 N/mm130; ResistenciaAFlexao: ≥ 3500 N; ResistenciaAAbrasaoProfunda: < 120 mm131; DilatacaoTermicaLinear: ≤ 8,0x10-6 °C-1; ResistenciaAoChoqueTermico: Resiste; DurabilidadeResistenciaAoGeloDegelo: Resiste; ResistenciaAsManchas: Class 5; ResistenciaABaixasConcentracoesDeAcidosEAlcalis: Classe LA; ResistenciaAAltasConcentracoesDeAcidosEAlcalis: Classe HA; LibertacaoDeCadmio: 0; LibertacaoDeChumbo: 0
Type - IFC.REVIGRÉS-Dados de especificação-Wall Sweeps - VariacaoTonalidade: 3; NivelDeTrafego: 5; EPavimento: Não; ERevestimento: Sim; EExterno: Sim
Type - IFC.REVIGRÉS-Dados geométricos-Wall Sweeps - AlturaNominal: 9.8 mm; ComprimentoNominal: 9.5 mm; LarguraNominal: 29.5 mm
Type - IFC.REVIGRÉS-Dados de sustentabilidade-Wall Sweeps - ItemEParcialmenteReciclado: 0; PotencialPrivacaoDeAguaConsumoDeAguaPonderado: 4.5; EnergiaTermicaExportada: 0; ItemENovo: Sim; ItemEReciclado: Não; VidaÚtilEsperada: 50; SubstanciasPerigosas: Não; PotencialDeEsgotamentoAbioticoDosRecursosFosseis: 203; PotencialDeEsgotamentoAbioticoDosRecursosNaoFosseisMineraisEMetais: 0.000701; PotencialDeAquecimentoGlobalBiogenico: -0.48; CombustiveisFosseisComPotencialDeAquecimentoGlobal: 13.9; PotencialDeAquecimentoGlobalUsoDoSoloEMudancaDeUsoDoSolo: 0.0246; PotencialDeEutrofizacaoFraccaoDeNutrientesQueAtingemOCompartimentoFinalDeAguaDoce: 0.000189; PotencialDeEutrofizacaoFraccaoDeNutrientesQueAtingemOCompartimentoFinalMarinho: 0.0122; EnergiaRecuperada: 0.00739; ConsumoDeAguaDoce: 0.113; UtilizacaoLiquidaDeAguaDoce: 0.113; ResiduosPerigososEliminados: 0.00221; ResiduosNaoPerigososEliminados: 1.83; MassaTotalDeResiduosRadioactivosEliminados: 0.000394; EnergiaElectricaExportada: 1.55; MateriaisParaRecuperacaoDeEnergia: 0.00739; MateriaisParaReciclagem: 0.0253; UnidadeEPD: 1 m²
Pset_ProvisionForVoid - Shape: Undefined; Width: 1000 mm; Depth: 1000 mm
IFC.REVIGRÉS-Dados do fabricante-Wall Sweeps - Type: Wall Sweep: REVIGRÉS-OMNISTONE-RB-9.5X30-SOFT-ICE
IFC.REVIGRÉS-Dados de desempenho-Wall Sweeps - Type: Wall Sweep: REVIGRÉS-OMNISTONE-RB-9.5X30-SOFT-ICE
IFC.REVIGRÉS-Dados de especificação-Wall Sweeps - Type: Wall Sweep: REVIGRÉS-OMNISTONE-RB-9.5X30-SOFT-ICE
IFC.REVIGRÉS-Dados geométricos-Wall Sweeps - Type: Wall Sweep: REVIGRÉS-OMNISTONE-RB-9.5X30-SOFT-ICE
IFC.REVIGRÉS-Dados de sustentabilidade-Wall Sweeps - Type: Wall Sweep: REVIGRÉS-OMNISTONE-RB-9.5X30-SOFT-ICE

# IfcBuildingElementProxy: Wall Sweep:REVIGRÉS-OMNISTONE-RB-9.5X30-SOFT-IRON, Wall Sweep:REVIGRÉS-OMNISTONE-RB-9.5X30-SOFT-IRON:181708
In: Level 1
Type - Pset_ManufacturerTypeInformation - Manufacturer: REVIGRÉS
Type - Pset_ProductRequirements - Category: Wall Sweeps
Type - IFC.REVIGRÉS-Dados gerais-Wall Sweeps - Nome: REVIGRÉS-OMNISTONE-RB-9.5X30-SOFT-IRON; TipoProduto: Prensado a seco: grupo BIa UGL | Grés porcelânico técnico; NumeroDeRegistoDAP: EPD-REV-20240006-CCC1-EN; ReferenciaDAP: -; UrlDOP: -
Type - IFC.REVIGRÉS-Dados do fabricante-Wall Sweeps - FabricanteURL: https://www.revigres.pt/; ReferenciaModelo: Omnistone; Acabamento: SOFT; IdentificadorDoOperadorEconomico: 501840856; UrlFabricanteArtigo: https://www.revigres.pt/colecoes/omnistone; PaisOrigem: Portugal
Type - IFC.REVIGRÉS-Dados de desempenho-Wall Sweeps - Rectilinearidade: ± 0.2% máx.± 0.8 mm; Ortogonalidade: ± 0.2% máx.± 1.5 mm; PlanaridadeDaSuperficie: ± 0.3% máx. ± 1.8 mm; AbsorcaoDeAgua: < 0.05%; ModuloDeRuptura: > 45 N/mm130; ResistenciaAFlexao: ≥ 3500 N; ResistenciaAAbrasaoProfunda: < 120 mm131; DilatacaoTermicaLinear: ≤ 8,0x10-6 °C-1; ResistenciaAoChoqueTermico: Resiste; DurabilidadeResistenciaAoGeloDegelo: Resiste; ResistenciaAsManchas: Class 5; ResistenciaABaixasConcentracoesDeAcidosEAlcalis: Classe LA; ResistenciaAAltasConcentracoesDeAcidosEAlcalis: Classe HA; LibertacaoDeCadmio: 0; LibertacaoDeChumbo: 0
Type - IFC.REVIGRÉS-Dados de especificação-Wall Sweeps - VariacaoTonalidade: 3; NivelDeTrafego: 5; EPavimento: Não; ERevestimento: Sim; EExterno: Sim
Type - IFC.REVIGRÉS-Dados geométricos-Wall Sweeps - AlturaNominal: 9.8 mm; ComprimentoNominal: 9.5 mm; LarguraNominal: 29.5 mm
Type - IFC.REVIGRÉS-Dados de sustentabilidade-Wall Sweeps - PotencialPrivacaoDeAguaConsumoDeAguaPonderado: 4.5; EnergiaTermicaExportada: 0; ItemENovo: Sim; ItemEParcialmenteReciclado: 0.14; ItemEReciclado: Sim; VidaÚtilEsperada: 50; SubstanciasPerigosas: Não; PotencialDeEsgotamentoAbioticoDosRecursosFosseis: 203; PotencialDeEsgotamentoAbioticoDosRecursosNaoFosseisMineraisEMetais: 0.000701; PotencialDeAquecimentoGlobalBiogenico: -0.48; CombustiveisFosseisComPotencialDeAquecimentoGlobal: 13.9; PotencialDeAquecimentoGlobalUsoDoSoloEMudancaDeUsoDoSolo: 0.0246; PotencialDeEutrofizacaoFraccaoDeNutrientesQueAtingemOCompartimentoFinalDeAguaDoce: 0.000189; PotencialDeEutrofizacaoFraccaoDeNutrientesQueAtingemOCompartimentoFinalMarinho: 0.0122; EnergiaRecuperada: 0.00739; ConsumoDeAguaDoce: 0.113; UtilizacaoLiquidaDeAguaDoce: 0.113; ResiduosPerigososEliminados: 0.00221; ResiduosNaoPerigososEliminados: 1.83; MassaTotalDeResiduosRadioactivosEliminados: 0.000394; EnergiaElectricaExportada: 1.55; MateriaisParaRecuperacaoDeEnergia: 0.00739; MateriaisParaReciclagem: 0.0253; UnidadeEPD: 1 m²
Pset_ProvisionForVoid - Shape: Undefined; Width: 1000 mm; Depth: 1000 mm
IFC.REVIGRÉS-Dados do fabricante-Wall Sweeps - Type: Wall Sweep: REVIGRÉS-OMNISTONE-RB-9.5X30-SOFT-IRON
IFC.REVIGRÉS-Dados de desempenho-Wall Sweeps - Type: Wall Sweep: REVIGRÉS-OMNISTONE-RB-9.5X30-SOFT-IRON
IFC.REVIGRÉS-Dados de especificação-Wall Sweeps - Type: Wall Sweep: REVIGRÉS-OMNISTONE-RB-9.5X30-SOFT-IRON
IFC.REVIGRÉS-Dados geométricos-Wall Sweeps - Type: Wall Sweep: REVIGRÉS-OMNISTONE-RB-9.5X30-SOFT-IRON
IFC.REVIGRÉS-Dados de sustentabilidade-Wall Sweeps - Type: Wall Sweep: REVIGRÉS-OMNISTONE-RB-9.5X30-SOFT-IRON

# IfcBuildingElementProxy: Wall Sweep:REVIGRÉS-OMNISTONE-RB-9.5X30-SOFT-JET, Wall Sweep:REVIGRÉS-OMNISTONE-RB-9.5X30-SOFT-JET:181720
In: Level 1
Type - Pset_ManufacturerTypeInformation - Manufacturer: REVIGRÉS
Type - Pset_ProductRequirements - Category: Wall Sweeps
Type - IFC.REVIGRÉS-Dados gerais-Wall Sweeps - Nome: REVIGRÉS-OMNISTONE-RB-9.5X30-SOFT-JET; TipoProduto: Prensado a seco: grupo BIa UGL | Grés porcelânico técnico; NumeroDeRegistoDAP: EPD-REV-20240006-CCC1-EN; ReferenciaDAP: -; UrlDOP: -
Type - IFC.REVIGRÉS-Dados do fabricante-Wall Sweeps - FabricanteURL: https://www.revigres.pt/; ReferenciaModelo: Omnistone; Acabamento: SOFT; IdentificadorDoOperadorEconomico: 501840856; UrlFabricanteArtigo: https://www.revigres.pt/colecoes/omnistone; PaisOrigem: Portugal
Type - IFC.REVIGRÉS-Dados de desempenho-Wall Sweeps - Rectilinearidade: ± 0.2% máx.± 0.8 mm; Ortogonalidade: ± 0.2% máx.± 1.5 mm; PlanaridadeDaSuperficie: ± 0.3% máx. ± 1.8 mm; AbsorcaoDeAgua: < 0.05%; ModuloDeRuptura: > 45 N/mm130; ResistenciaAFlexao: ≥ 3500 N; ResistenciaAAbrasaoProfunda: < 120 mm131; DilatacaoTermicaLinear: ≤ 8,0x10-6 °C-1; ResistenciaAoChoqueTermico: Resiste; DurabilidadeResistenciaAoGeloDegelo: Resiste; ResistenciaAsManchas: Class 5; ResistenciaABaixasConcentracoesDeAcidosEAlcalis: Classe LA; ResistenciaAAltasConcentracoesDeAcidosEAlcalis: Classe HA; LibertacaoDeCadmio: 0; LibertacaoDeChumbo: 0
Type - IFC.REVIGRÉS-Dados de especificação-Wall Sweeps - VariacaoTonalidade: 3; NivelDeTrafego: 5; EPavimento: Não; ERevestimento: Sim; EExterno: Sim
Type - IFC.REVIGRÉS-Dados geométricos-Wall Sweeps - AlturaNominal: 9.8 mm; ComprimentoNominal: 9.5 mm; LarguraNominal: 29.5 mm
Type - IFC.REVIGRÉS-Dados de sustentabilidade-Wall Sweeps - ItemEParcialmenteReciclado: 0; PotencialPrivacaoDeAguaConsumoDeAguaPonderado: 4.5; EnergiaTermicaExportada: 0; ItemENovo: Sim; ItemEReciclado: Não; VidaÚtilEsperada: 50; SubstanciasPerigosas: Não; PotencialDeEsgotamentoAbioticoDosRecursosFosseis: 203; PotencialDeEsgotamentoAbioticoDosRecursosNaoFosseisMineraisEMetais: 0.000701; PotencialDeAquecimentoGlobalBiogenico: -0.48; CombustiveisFosseisComPotencialDeAquecimentoGlobal: 13.9; PotencialDeAquecimentoGlobalUsoDoSoloEMudancaDeUsoDoSolo: 0.0246; PotencialDeEutrofizacaoFraccaoDeNutrientesQueAtingemOCompartimentoFinalDeAguaDoce: 0.000189; PotencialDeEutrofizacaoFraccaoDeNutrientesQueAtingemOCompartimentoFinalMarinho: 0.0122; EnergiaRecuperada: 0.00739; ConsumoDeAguaDoce: 0.113; UtilizacaoLiquidaDeAguaDoce: 0.113; ResiduosPerigososEliminados: 0.00221; ResiduosNaoPerigososEliminados: 1.83; MassaTotalDeResiduosRadioactivosEliminados: 0.000394; EnergiaElectricaExportada: 1.55; MateriaisParaRecuperacaoDeEnergia: 0.00739; MateriaisParaReciclagem: 0.0253; UnidadeEPD: 1 m²
Pset_ProvisionForVoid - Shape: Undefined; Width: 1000 mm; Depth: 1000 mm
IFC.REVIGRÉS-Dados do fabricante-Wall Sweeps - Type: Wall Sweep: REVIGRÉS-OMNISTONE-RB-9.5X30-SOFT-JET
IFC.REVIGRÉS-Dados de desempenho-Wall Sweeps - Type: Wall Sweep: REVIGRÉS-OMNISTONE-RB-9.5X30-SOFT-JET
IFC.REVIGRÉS-Dados de especificação-Wall Sweeps - Type: Wall Sweep: REVIGRÉS-OMNISTONE-RB-9.5X30-SOFT-JET
IFC.REVIGRÉS-Dados geométricos-Wall Sweeps - Type: Wall Sweep: REVIGRÉS-OMNISTONE-RB-9.5X30-SOFT-JET
IFC.REVIGRÉS-Dados de sustentabilidade-Wall Sweeps - Type: Wall Sweep: REVIGRÉS-OMNISTONE-RB-9.5X30-SOFT-JET

# IfcBuildingElementProxy: Wall Sweep:REVIGRÉS-OMNISTONE-RB-9.5X30-SOFT-PLATINA, Wall Sweep:REVIGRÉS-OMNISTONE-RB-9.5X30-SOFT-PLATINA:181732
In: Level 1
Type - Pset_ManufacturerTypeInformation - Manufacturer: REVIGRÉS
Type - Pset_ProductRequirements - Category: Wall Sweeps
Type - IFC.REVIGRÉS-Dados gerais-Wall Sweeps - Nome: REVIGRÉS-OMNISTONE-RB-9.5X30-SOFT-PLATINA; TipoProduto: Prensado a seco: grupo BIa UGL | Grés porcelânico técnico; NumeroDeRegistoDAP: EPD-REV-20240006-CCC1-EN; ReferenciaDAP: -; UrlDOP: -
Type - IFC.REVIGRÉS-Dados do fabricante-Wall Sweeps - FabricanteURL: https://www.revigres.pt/; ReferenciaModelo: Omnistone; Acabamento: SOFT; IdentificadorDoOperadorEconomico: 501840856; UrlFabricanteArtigo: https://www.revigres.pt/colecoes/omnistone; PaisOrigem: Portugal
Type - IFC.REVIGRÉS-Dados de desempenho-Wall Sweeps - Rectilinearidade: ± 0.2% máx.± 0.8 mm; Ortogonalidade: ± 0.2% máx.± 1.5 mm; PlanaridadeDaSuperficie: ± 0.3% máx. ± 1.8 mm; AbsorcaoDeAgua: < 0.05%; ModuloDeRuptura: > 45 N/mm130; ResistenciaAFlexao: ≥ 3500 N; ResistenciaAAbrasaoProfunda: < 120 mm131; DilatacaoTermicaLinear: ≤ 8,0x10-6 °C-1; ResistenciaAoChoqueTermico: Resiste; DurabilidadeResistenciaAoGeloDegelo: Resiste; ResistenciaAsManchas: Class 5; ResistenciaABaixasConcentracoesDeAcidosEAlcalis: Classe LA; ResistenciaAAltasConcentracoesDeAcidosEAlcalis: Classe HA; LibertacaoDeCadmio: 0; LibertacaoDeChumbo: 0
Type - IFC.REVIGRÉS-Dados de especificação-Wall Sweeps - VariacaoTonalidade: 3; NivelDeTrafego: 5; EPavimento: Não; ERevestimento: Sim; EExterno: Sim
Type - IFC.REVIGRÉS-Dados geométricos-Wall Sweeps - AlturaNominal: 9.8 mm; ComprimentoNominal: 9.5 mm; LarguraNominal: 29.5 mm
Type - IFC.REVIGRÉS-Dados de sustentabilidade-Wall Sweeps - ItemEParcialmenteReciclado: 0; PotencialPrivacaoDeAguaConsumoDeAguaPonderado: 4.5; EnergiaTermicaExportada: 0; ItemENovo: Sim; ItemEReciclado: Não; VidaÚtilEsperada: 50; SubstanciasPerigosas: Não; PotencialDeEsgotamentoAbioticoDosRecursosFosseis: 203; PotencialDeEsgotamentoAbioticoDosRecursosNaoFosseisMineraisEMetais: 0.000701; PotencialDeAquecimentoGlobalBiogenico: -0.48; CombustiveisFosseisComPotencialDeAquecimentoGlobal: 13.9; PotencialDeAquecimentoGlobalUsoDoSoloEMudancaDeUsoDoSolo: 0.0246; PotencialDeEutrofizacaoFraccaoDeNutrientesQueAtingemOCompartimentoFinalDeAguaDoce: 0.000189; PotencialDeEutrofizacaoFraccaoDeNutrientesQueAtingemOCompartimentoFinalMarinho: 0.0122; EnergiaRecuperada: 0.00739; ConsumoDeAguaDoce: 0.113; UtilizacaoLiquidaDeAguaDoce: 0.113; ResiduosPerigososEliminados: 0.00221; ResiduosNaoPerigososEliminados: 1.83; MassaTotalDeResiduosRadioactivosEliminados: 0.000394; EnergiaElectricaExportada: 1.55; MateriaisParaRecuperacaoDeEnergia: 0.00739; MateriaisParaReciclagem: 0.0253; UnidadeEPD: 1 m²
Pset_ProvisionForVoid - Shape: Undefined; Width: 1000 mm; Depth: 1000 mm
IFC.REVIGRÉS-Dados do fabricante-Wall Sweeps - Type: Wall Sweep: REVIGRÉS-OMNISTONE-RB-9.5X30-SOFT-PLATINA
IFC.REVIGRÉS-Dados de desempenho-Wall Sweeps - Type: Wall Sweep: REVIGRÉS-OMNISTONE-RB-9.5X30-SOFT-PLATINA
IFC.REVIGRÉS-Dados de especificação-Wall Sweeps - Type: Wall Sweep: REVIGRÉS-OMNISTONE-RB-9.5X30-SOFT-PLATINA
IFC.REVIGRÉS-Dados geométricos-Wall Sweeps - Type: Wall Sweep: REVIGRÉS-OMNISTONE-RB-9.5X30-SOFT-PLATINA
IFC.REVIGRÉS-Dados de sustentabilidade-Wall Sweeps - Type: Wall Sweep: REVIGRÉS-OMNISTONE-RB-9.5X30-SOFT-PLATINA

# IfcBuildingElementProxy: Wall Sweep:REVIGRÉS-OMNISTONE-RB-9.5X30-SOFT-ROPE, Wall Sweep:REVIGRÉS-OMNISTONE-RB-9.5X30-SOFT-ROPE:181744
In: Level 1
Type - Pset_ManufacturerTypeInformation - Manufacturer: REVIGRÉS
Type - Pset_ProductRequirements - Category: Wall Sweeps
Type - IFC.REVIGRÉS-Dados gerais-Wall Sweeps - Nome: REVIGRÉS-OMNISTONE-RB-9.5X30-SOFT-ROPE; TipoProduto: Prensado a seco: grupo BIa UGL | Grés porcelânico técnico; NumeroDeRegistoDAP: EPD-REV-20240006-CCC1-EN; ReferenciaDAP: -; UrlDOP: -
Type - IFC.REVIGRÉS-Dados do fabricante-Wall Sweeps - FabricanteURL: https://www.revigres.pt/; ReferenciaModelo: Omnistone; Acabamento: SOFT; IdentificadorDoOperadorEconomico: 501840856; UrlFabricanteArtigo: https://www.revigres.pt/colecoes/omnistone; PaisOrigem: Portugal
Type - IFC.REVIGRÉS-Dados de desempenho-Wall Sweeps - Rectilinearidade: ± 0.2% máx.± 0.8 mm; Ortogonalidade: ± 0.2% máx.± 1.5 mm; PlanaridadeDaSuperficie: ± 0.3% máx. ± 1.8 mm; AbsorcaoDeAgua: < 0.05%; ModuloDeRuptura: > 45 N/mm130; ResistenciaAFlexao: ≥ 3500 N; ResistenciaAAbrasaoProfunda: < 120 mm131; DilatacaoTermicaLinear: ≤ 8,0x10-6 °C-1; ResistenciaAoChoqueTermico: Resiste; DurabilidadeResistenciaAoGeloDegelo: Resiste; ResistenciaAsManchas: Class 5; ResistenciaABaixasConcentracoesDeAcidosEAlcalis: Classe LA; ResistenciaAAltasConcentracoesDeAcidosEAlcalis: Classe HA; LibertacaoDeCadmio: 0; LibertacaoDeChumbo: 0
Type - IFC.REVIGRÉS-Dados de especificação-Wall Sweeps - VariacaoTonalidade: 3; NivelDeTrafego: 5; EPavimento: Não; ERevestimento: Sim; EExterno: Sim
Type - IFC.REVIGRÉS-Dados geométricos-Wall Sweeps - AlturaNominal: 9.8 mm; ComprimentoNominal: 9.5 mm; LarguraNominal: 29.5 mm
Type - IFC.REVIGRÉS-Dados de sustentabilidade-Wall Sweeps - ItemEParcialmenteReciclado: 0; PotencialPrivacaoDeAguaConsumoDeAguaPonderado: 4.5; EnergiaTermicaExportada: 0; ItemENovo: Sim; ItemEReciclado: Não; VidaÚtilEsperada: 50; SubstanciasPerigosas: Não; PotencialDeEsgotamentoAbioticoDosRecursosFosseis: 203; PotencialDeEsgotamentoAbioticoDosRecursosNaoFosseisMineraisEMetais: 0.000701; PotencialDeAquecimentoGlobalBiogenico: -0.48; CombustiveisFosseisComPotencialDeAquecimentoGlobal: 13.9; PotencialDeAquecimentoGlobalUsoDoSoloEMudancaDeUsoDoSolo: 0.0246; PotencialDeEutrofizacaoFraccaoDeNutrientesQueAtingemOCompartimentoFinalDeAguaDoce: 0.000189; PotencialDeEutrofizacaoFraccaoDeNutrientesQueAtingemOCompartimentoFinalMarinho: 0.0122; EnergiaRecuperada: 0.00739; ConsumoDeAguaDoce: 0.113; UtilizacaoLiquidaDeAguaDoce: 0.113; ResiduosPerigososEliminados: 0.00221; ResiduosNaoPerigososEliminados: 1.83; MassaTotalDeResiduosRadioactivosEliminados: 0.000394; EnergiaElectricaExportada: 1.55; MateriaisParaRecuperacaoDeEnergia: 0.00739; MateriaisParaReciclagem: 0.0253; UnidadeEPD: 1 m²
Pset_ProvisionForVoid - Shape: Undefined; Width: 1000 mm; Depth: 1000 mm
IFC.REVIGRÉS-Dados do fabricante-Wall Sweeps - Type: Wall Sweep: REVIGRÉS-OMNISTONE-RB-9.5X30-SOFT-ROPE
IFC.REVIGRÉS-Dados de desempenho-Wall Sweeps - Type: Wall Sweep: REVIGRÉS-OMNISTONE-RB-9.5X30-SOFT-ROPE
IFC.REVIGRÉS-Dados de especificação-Wall Sweeps - Type: Wall Sweep: REVIGRÉS-OMNISTONE-RB-9.5X30-SOFT-ROPE
IFC.REVIGRÉS-Dados geométricos-Wall Sweeps - Type: Wall Sweep: REVIGRÉS-OMNISTONE-RB-9.5X30-SOFT-ROPE
IFC.REVIGRÉS-Dados de sustentabilidade-Wall Sweeps - Type: Wall Sweep: REVIGRÉS-OMNISTONE-RB-9.5X30-SOFT-ROPE

# IfcWallStandardCase: Basic Wall:Wall 1 (12)
In: Level 1
Type - PredefinedType: STANDARD
Type - Pset_ElementShading - Roughness: 304.8 mm
Type - Pset_ProductRequirements - Category: Walls
Type - Pset_QuantityTakeOff - Reference: Wall 1
Type - Pset_ReinforcementBarPitchOfWall - Reference: Wall 1
Type - Pset_WallCommon - Reference: Wall 1; IsExternal: no
Pset_QuantityTakeOff - sets with these values: 2
Pset_WallCommon - IsExternal: yes; ExtendToStructure: no; LoadBearing: no
Name (Basic Wall:Wall 1:...)
104322
158840
158991
159220
159471
159483
159823
160038
180458
180460
180461
180462
